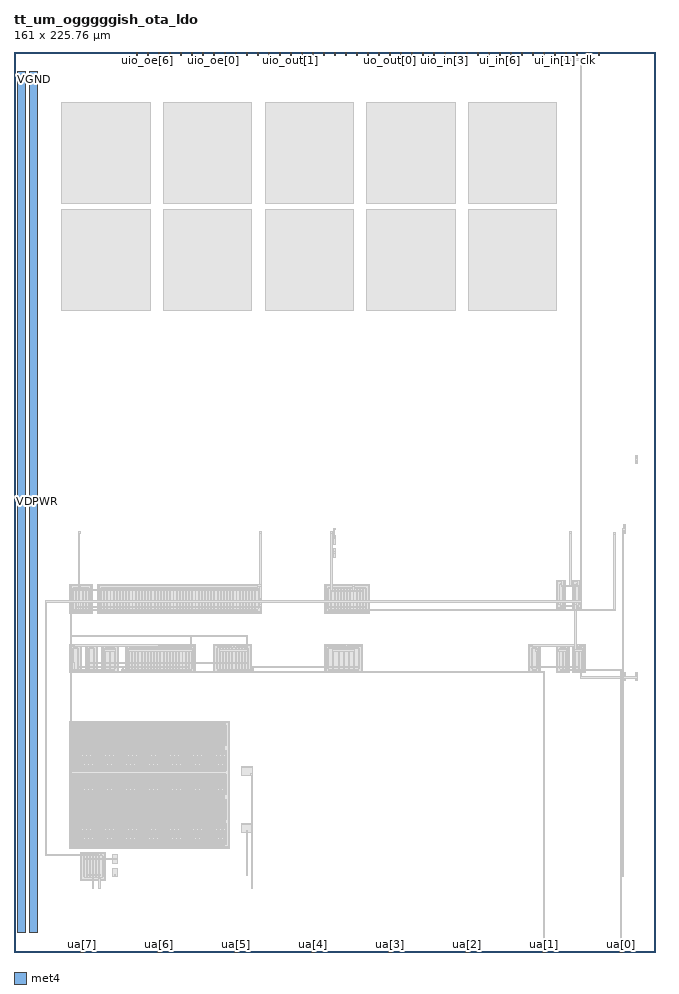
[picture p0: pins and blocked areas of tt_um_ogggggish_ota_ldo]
MACRO tt_um_ogggggish_ota_ldo
  CLASS BLOCK ;
  FOREIGN tt_um_ogggggish_ota_ldo ;
  ORIGIN 0.000 0.000 ;
  SIZE 161.000 BY 225.760 ;
  PIN clk
    DIRECTION INPUT ;
    USE SIGNAL ;
    PORT
      LAYER met4 ;
        RECT 143.830 224.760 144.130 225.760 ;
    END
  END clk
  PIN ena
    DIRECTION INPUT ;
    USE SIGNAL ;
    PORT
      LAYER met4 ;
        RECT 146.590 224.760 146.890 225.760 ;
    END
  END ena
  PIN rst_n
    DIRECTION INPUT ;
    USE SIGNAL ;
    PORT
      LAYER met4 ;
        RECT 141.070 224.760 141.370 225.760 ;
    END
  END rst_n
  PIN ua[0]
    DIRECTION INOUT ;
    USE SIGNAL ;
    ANTENNAGATEAREA 5.000000 ;
    PORT
      LAYER met4 ;
        RECT 151.810 0.000 152.710 1.000 ;
    END
  END ua[0]
  PIN ua[1]
    DIRECTION INOUT ;
    USE SIGNAL ;
    ANTENNAGATEAREA 55.000000 ;
    ANTENNADIFFAREA 1.450000 ;
    PORT
      LAYER met4 ;
        RECT 132.490 0.000 133.390 1.000 ;
    END
  END ua[1]
  PIN ua[2]
    DIRECTION INOUT ;
    USE SIGNAL ;
    ANTENNADIFFAREA 337.250000 ;
    PORT
      LAYER met4 ;
        RECT 113.170 0.000 114.070 1.000 ;
    END
  END ua[2]
  PIN ua[3]
    DIRECTION INOUT ;
    USE SIGNAL ;
    PORT
      LAYER met4 ;
        RECT 93.850 0.000 94.750 1.000 ;
    END
  END ua[3]
  PIN ua[4]
    DIRECTION INOUT ;
    USE SIGNAL ;
    PORT
      LAYER met4 ;
        RECT 74.530 0.000 75.430 1.000 ;
    END
  END ua[4]
  PIN ua[5]
    DIRECTION INOUT ;
    USE SIGNAL ;
    PORT
      LAYER met4 ;
        RECT 55.210 0.000 56.110 1.000 ;
    END
  END ua[5]
  PIN ua[6]
    DIRECTION INOUT ;
    USE SIGNAL ;
    PORT
      LAYER met4 ;
        RECT 35.890 0.000 36.790 1.000 ;
    END
  END ua[6]
  PIN ua[7]
    DIRECTION INOUT ;
    USE SIGNAL ;
    PORT
      LAYER met4 ;
        RECT 16.570 0.000 17.470 1.000 ;
    END
  END ua[7]
  PIN ui_in[0]
    DIRECTION INPUT ;
    USE SIGNAL ;
    ANTENNAGATEAREA 15.000000 ;
    PORT
      LAYER met4 ;
        RECT 138.310 224.760 138.610 225.760 ;
    END
  END ui_in[0]
  PIN ui_in[1]
    DIRECTION INPUT ;
    USE SIGNAL ;
    PORT
      LAYER met4 ;
        RECT 135.550 224.760 135.850 225.760 ;
    END
  END ui_in[1]
  PIN ui_in[2]
    DIRECTION INPUT ;
    USE SIGNAL ;
    PORT
      LAYER met4 ;
        RECT 132.790 224.760 133.090 225.760 ;
    END
  END ui_in[2]
  PIN ui_in[3]
    DIRECTION INPUT ;
    USE SIGNAL ;
    PORT
      LAYER met4 ;
        RECT 130.030 224.760 130.330 225.760 ;
    END
  END ui_in[3]
  PIN ui_in[4]
    DIRECTION INPUT ;
    USE SIGNAL ;
    PORT
      LAYER met4 ;
        RECT 127.270 224.760 127.570 225.760 ;
    END
  END ui_in[4]
  PIN ui_in[5]
    DIRECTION INPUT ;
    USE SIGNAL ;
    PORT
      LAYER met4 ;
        RECT 124.510 224.760 124.810 225.760 ;
    END
  END ui_in[5]
  PIN ui_in[6]
    DIRECTION INPUT ;
    USE SIGNAL ;
    PORT
      LAYER met4 ;
        RECT 121.750 224.760 122.050 225.760 ;
    END
  END ui_in[6]
  PIN ui_in[7]
    DIRECTION INPUT ;
    USE SIGNAL ;
    PORT
      LAYER met4 ;
        RECT 118.990 224.760 119.290 225.760 ;
    END
  END ui_in[7]
  PIN uio_in[0]
    DIRECTION INPUT ;
    USE SIGNAL ;
    PORT
      LAYER met4 ;
        RECT 116.230 224.760 116.530 225.760 ;
    END
  END uio_in[0]
  PIN uio_in[1]
    DIRECTION INPUT ;
    USE SIGNAL ;
    PORT
      LAYER met4 ;
        RECT 113.470 224.760 113.770 225.760 ;
    END
  END uio_in[1]
  PIN uio_in[2]
    DIRECTION INPUT ;
    USE SIGNAL ;
    PORT
      LAYER met4 ;
        RECT 110.710 224.760 111.010 225.760 ;
    END
  END uio_in[2]
  PIN uio_in[3]
    DIRECTION INPUT ;
    USE SIGNAL ;
    PORT
      LAYER met4 ;
        RECT 107.950 224.760 108.250 225.760 ;
    END
  END uio_in[3]
  PIN uio_in[4]
    DIRECTION INPUT ;
    USE SIGNAL ;
    PORT
      LAYER met4 ;
        RECT 105.190 224.760 105.490 225.760 ;
    END
  END uio_in[4]
  PIN uio_in[5]
    DIRECTION INPUT ;
    USE SIGNAL ;
    PORT
      LAYER met4 ;
        RECT 102.430 224.760 102.730 225.760 ;
    END
  END uio_in[5]
  PIN uio_in[6]
    DIRECTION INPUT ;
    USE SIGNAL ;
    PORT
      LAYER met4 ;
        RECT 99.670 224.760 99.970 225.760 ;
    END
  END uio_in[6]
  PIN uio_in[7]
    DIRECTION INPUT ;
    USE SIGNAL ;
    PORT
      LAYER met4 ;
        RECT 96.910 224.760 97.210 225.760 ;
    END
  END uio_in[7]
  PIN uio_oe[0]
    DIRECTION OUTPUT ;
    USE SIGNAL ;
    ANTENNADIFFAREA 65.475197 ;
    PORT
      LAYER met4 ;
        RECT 49.990 224.760 50.290 225.760 ;
    END
  END uio_oe[0]
  PIN uio_oe[1]
    DIRECTION OUTPUT ;
    USE SIGNAL ;
    ANTENNADIFFAREA 65.475197 ;
    PORT
      LAYER met4 ;
        RECT 47.230 224.760 47.530 225.760 ;
    END
  END uio_oe[1]
  PIN uio_oe[2]
    DIRECTION OUTPUT ;
    USE SIGNAL ;
    ANTENNADIFFAREA 65.475197 ;
    PORT
      LAYER met4 ;
        RECT 44.470 224.760 44.770 225.760 ;
    END
  END uio_oe[2]
  PIN uio_oe[3]
    DIRECTION OUTPUT ;
    USE SIGNAL ;
    ANTENNADIFFAREA 65.475197 ;
    PORT
      LAYER met4 ;
        RECT 41.710 224.760 42.010 225.760 ;
    END
  END uio_oe[3]
  PIN uio_oe[4]
    DIRECTION OUTPUT ;
    USE SIGNAL ;
    ANTENNADIFFAREA 65.475197 ;
    PORT
      LAYER met4 ;
        RECT 38.950 224.760 39.250 225.760 ;
    END
  END uio_oe[4]
  PIN uio_oe[5]
    DIRECTION OUTPUT ;
    USE SIGNAL ;
    ANTENNADIFFAREA 65.475197 ;
    PORT
      LAYER met4 ;
        RECT 36.190 224.760 36.490 225.760 ;
    END
  END uio_oe[5]
  PIN uio_oe[6]
    DIRECTION OUTPUT ;
    USE SIGNAL ;
    ANTENNADIFFAREA 65.475197 ;
    PORT
      LAYER met4 ;
        RECT 33.430 224.760 33.730 225.760 ;
    END
  END uio_oe[6]
  PIN uio_oe[7]
    DIRECTION OUTPUT ;
    USE SIGNAL ;
    ANTENNADIFFAREA 65.475197 ;
    PORT
      LAYER met4 ;
        RECT 30.670 224.760 30.970 225.760 ;
    END
  END uio_oe[7]
  PIN uio_out[0]
    DIRECTION OUTPUT ;
    USE SIGNAL ;
    ANTENNADIFFAREA 65.475197 ;
    PORT
      LAYER met4 ;
        RECT 72.070 224.760 72.370 225.760 ;
    END
  END uio_out[0]
  PIN uio_out[1]
    DIRECTION OUTPUT ;
    USE SIGNAL ;
    ANTENNADIFFAREA 65.475197 ;
    PORT
      LAYER met4 ;
        RECT 69.310 224.760 69.610 225.760 ;
    END
  END uio_out[1]
  PIN uio_out[2]
    DIRECTION OUTPUT ;
    USE SIGNAL ;
    ANTENNADIFFAREA 65.475197 ;
    PORT
      LAYER met4 ;
        RECT 66.550 224.760 66.850 225.760 ;
    END
  END uio_out[2]
  PIN uio_out[3]
    DIRECTION OUTPUT ;
    USE SIGNAL ;
    ANTENNADIFFAREA 65.475197 ;
    PORT
      LAYER met4 ;
        RECT 63.790 224.760 64.090 225.760 ;
    END
  END uio_out[3]
  PIN uio_out[4]
    DIRECTION OUTPUT ;
    USE SIGNAL ;
    ANTENNADIFFAREA 65.475197 ;
    PORT
      LAYER met4 ;
        RECT 61.030 224.760 61.330 225.760 ;
    END
  END uio_out[4]
  PIN uio_out[5]
    DIRECTION OUTPUT ;
    USE SIGNAL ;
    ANTENNADIFFAREA 65.475197 ;
    PORT
      LAYER met4 ;
        RECT 58.270 224.760 58.570 225.760 ;
    END
  END uio_out[5]
  PIN uio_out[6]
    DIRECTION OUTPUT ;
    USE SIGNAL ;
    ANTENNADIFFAREA 65.475197 ;
    PORT
      LAYER met4 ;
        RECT 55.510 224.760 55.810 225.760 ;
    END
  END uio_out[6]
  PIN uio_out[7]
    DIRECTION OUTPUT ;
    USE SIGNAL ;
    ANTENNADIFFAREA 65.475197 ;
    PORT
      LAYER met4 ;
        RECT 52.750 224.760 53.050 225.760 ;
    END
  END uio_out[7]
  PIN uo_out[0]
    DIRECTION OUTPUT ;
    USE SIGNAL ;
    ANTENNADIFFAREA 65.475197 ;
    PORT
      LAYER met4 ;
        RECT 94.150 224.760 94.450 225.760 ;
    END
  END uo_out[0]
  PIN uo_out[1]
    DIRECTION OUTPUT ;
    USE SIGNAL ;
    ANTENNADIFFAREA 65.475197 ;
    PORT
      LAYER met4 ;
        RECT 91.390 224.760 91.690 225.760 ;
    END
  END uo_out[1]
  PIN uo_out[2]
    DIRECTION OUTPUT ;
    USE SIGNAL ;
    ANTENNADIFFAREA 65.475197 ;
    PORT
      LAYER met4 ;
        RECT 88.630 224.760 88.930 225.760 ;
    END
  END uo_out[2]
  PIN uo_out[3]
    DIRECTION OUTPUT ;
    USE SIGNAL ;
    ANTENNADIFFAREA 65.475197 ;
    PORT
      LAYER met4 ;
        RECT 85.870 224.760 86.170 225.760 ;
    END
  END uo_out[3]
  PIN uo_out[4]
    DIRECTION OUTPUT ;
    USE SIGNAL ;
    ANTENNADIFFAREA 65.475197 ;
    PORT
      LAYER met4 ;
        RECT 83.110 224.760 83.410 225.760 ;
    END
  END uo_out[4]
  PIN uo_out[5]
    DIRECTION OUTPUT ;
    USE SIGNAL ;
    ANTENNADIFFAREA 65.475197 ;
    PORT
      LAYER met4 ;
        RECT 80.350 224.760 80.650 225.760 ;
    END
  END uo_out[5]
  PIN uo_out[6]
    DIRECTION OUTPUT ;
    USE SIGNAL ;
    ANTENNADIFFAREA 65.475197 ;
    PORT
      LAYER met4 ;
        RECT 77.590 224.760 77.890 225.760 ;
    END
  END uo_out[6]
  PIN uo_out[7]
    DIRECTION OUTPUT ;
    USE SIGNAL ;
    ANTENNADIFFAREA 65.475197 ;
    PORT
      LAYER met4 ;
        RECT 74.830 224.760 75.130 225.760 ;
    END
  END uo_out[7]
  PIN VDPWR
    DIRECTION INOUT ;
    USE POWER ;
    PORT
      LAYER met4 ;
        RECT 1.000 5.005 3.000 220.765 ;
    END
  END VDPWR
  PIN VGND
    DIRECTION INOUT ;
    USE GROUND ;
    PORT
      LAYER met4 ;
        RECT 4.000 5.000 6.000 220.760 ;
    END
  END VGND
  OBS
      LAYER nwell ;
        RECT 14.000 85.000 19.620 92.190 ;
        RECT 21.000 85.000 62.170 92.190 ;
        RECT 78.000 85.000 89.150 92.190 ;
        RECT 136.000 86.000 138.460 93.190 ;
        RECT 140.000 86.000 142.460 93.190 ;
      LAYER pwell ;
        RECT 14.000 70.000 16.960 77.100 ;
        RECT 18.000 70.000 20.960 77.100 ;
        RECT 22.000 70.000 26.250 77.100 ;
        RECT 28.000 70.000 45.470 77.100 ;
      LAYER nwell ;
        RECT 50.000 70.000 59.570 77.190 ;
      LAYER pwell ;
        RECT 78.000 70.000 87.410 77.100 ;
        RECT 129.000 70.000 131.960 77.100 ;
        RECT 136.000 70.000 139.250 77.100 ;
        RECT 140.000 70.000 143.250 77.100 ;
      LAYER nwell ;
        RECT 14.000 26.000 54.070 57.910 ;
      LAYER pwell ;
        RECT 16.650 17.910 23.060 25.010 ;
      LAYER li1 ;
        RECT 156.000 122.495 156.350 124.655 ;
        RECT 153.000 105.000 153.350 107.160 ;
        RECT 80.000 102.200 80.690 104.360 ;
        RECT 80.000 99.000 80.690 101.160 ;
        RECT 137.485 93.010 137.715 93.040 ;
        RECT 141.485 93.010 141.715 93.040 ;
        RECT 136.180 92.840 138.280 93.010 ;
        RECT 16.285 92.010 16.515 92.040 ;
        RECT 61.185 92.010 61.415 92.040 ;
        RECT 85.035 92.010 85.265 92.040 ;
        RECT 14.180 91.840 19.440 92.010 ;
        RECT 14.180 85.350 14.350 91.840 ;
        RECT 16.285 91.810 16.515 91.840 ;
        RECT 14.980 91.330 15.480 91.500 ;
        RECT 15.770 91.330 16.270 91.500 ;
        RECT 16.560 91.330 17.060 91.500 ;
        RECT 17.350 91.330 17.850 91.500 ;
        RECT 18.140 91.330 18.640 91.500 ;
        RECT 14.750 86.075 14.920 91.115 ;
        RECT 15.540 86.075 15.710 91.115 ;
        RECT 16.330 86.075 16.500 91.115 ;
        RECT 17.120 86.075 17.290 91.115 ;
        RECT 17.910 86.075 18.080 91.115 ;
        RECT 18.700 86.075 18.870 91.115 ;
        RECT 14.980 85.690 15.480 85.860 ;
        RECT 15.770 85.690 16.270 85.860 ;
        RECT 16.560 85.690 17.060 85.860 ;
        RECT 17.350 85.690 17.850 85.860 ;
        RECT 18.140 85.690 18.640 85.860 ;
        RECT 19.270 85.350 19.440 91.840 ;
        RECT 14.180 85.180 19.440 85.350 ;
        RECT 21.180 91.840 61.990 92.010 ;
        RECT 21.180 85.350 21.350 91.840 ;
        RECT 61.185 91.810 61.415 91.840 ;
        RECT 21.980 91.330 22.480 91.500 ;
        RECT 22.770 91.330 23.270 91.500 ;
        RECT 23.560 91.330 24.060 91.500 ;
        RECT 24.350 91.330 24.850 91.500 ;
        RECT 25.140 91.330 25.640 91.500 ;
        RECT 25.930 91.330 26.430 91.500 ;
        RECT 26.720 91.330 27.220 91.500 ;
        RECT 27.510 91.330 28.010 91.500 ;
        RECT 28.300 91.330 28.800 91.500 ;
        RECT 29.090 91.330 29.590 91.500 ;
        RECT 29.880 91.330 30.380 91.500 ;
        RECT 30.670 91.330 31.170 91.500 ;
        RECT 31.460 91.330 31.960 91.500 ;
        RECT 32.250 91.330 32.750 91.500 ;
        RECT 33.040 91.330 33.540 91.500 ;
        RECT 33.830 91.330 34.330 91.500 ;
        RECT 34.620 91.330 35.120 91.500 ;
        RECT 35.410 91.330 35.910 91.500 ;
        RECT 36.200 91.330 36.700 91.500 ;
        RECT 36.990 91.330 37.490 91.500 ;
        RECT 37.780 91.330 38.280 91.500 ;
        RECT 38.570 91.330 39.070 91.500 ;
        RECT 39.360 91.330 39.860 91.500 ;
        RECT 40.150 91.330 40.650 91.500 ;
        RECT 40.940 91.330 41.440 91.500 ;
        RECT 41.730 91.330 42.230 91.500 ;
        RECT 42.520 91.330 43.020 91.500 ;
        RECT 43.310 91.330 43.810 91.500 ;
        RECT 44.100 91.330 44.600 91.500 ;
        RECT 44.890 91.330 45.390 91.500 ;
        RECT 45.680 91.330 46.180 91.500 ;
        RECT 46.470 91.330 46.970 91.500 ;
        RECT 47.260 91.330 47.760 91.500 ;
        RECT 48.050 91.330 48.550 91.500 ;
        RECT 48.840 91.330 49.340 91.500 ;
        RECT 49.630 91.330 50.130 91.500 ;
        RECT 50.420 91.330 50.920 91.500 ;
        RECT 51.210 91.330 51.710 91.500 ;
        RECT 52.000 91.330 52.500 91.500 ;
        RECT 52.790 91.330 53.290 91.500 ;
        RECT 53.580 91.330 54.080 91.500 ;
        RECT 54.370 91.330 54.870 91.500 ;
        RECT 55.160 91.330 55.660 91.500 ;
        RECT 55.950 91.330 56.450 91.500 ;
        RECT 56.740 91.330 57.240 91.500 ;
        RECT 57.530 91.330 58.030 91.500 ;
        RECT 58.320 91.330 58.820 91.500 ;
        RECT 59.110 91.330 59.610 91.500 ;
        RECT 59.900 91.330 60.400 91.500 ;
        RECT 60.690 91.330 61.190 91.500 ;
        RECT 21.750 86.075 21.920 91.115 ;
        RECT 22.540 86.075 22.710 91.115 ;
        RECT 23.330 86.075 23.500 91.115 ;
        RECT 24.120 86.075 24.290 91.115 ;
        RECT 24.910 86.075 25.080 91.115 ;
        RECT 25.700 86.075 25.870 91.115 ;
        RECT 26.490 86.075 26.660 91.115 ;
        RECT 27.280 86.075 27.450 91.115 ;
        RECT 28.070 86.075 28.240 91.115 ;
        RECT 28.860 86.075 29.030 91.115 ;
        RECT 29.650 86.075 29.820 91.115 ;
        RECT 30.440 86.075 30.610 91.115 ;
        RECT 31.230 86.075 31.400 91.115 ;
        RECT 32.020 86.075 32.190 91.115 ;
        RECT 32.810 86.075 32.980 91.115 ;
        RECT 33.600 86.075 33.770 91.115 ;
        RECT 34.390 86.075 34.560 91.115 ;
        RECT 35.180 86.075 35.350 91.115 ;
        RECT 35.970 86.075 36.140 91.115 ;
        RECT 36.760 86.075 36.930 91.115 ;
        RECT 37.550 86.075 37.720 91.115 ;
        RECT 38.340 86.075 38.510 91.115 ;
        RECT 39.130 86.075 39.300 91.115 ;
        RECT 39.920 86.075 40.090 91.115 ;
        RECT 40.710 86.075 40.880 91.115 ;
        RECT 41.500 86.075 41.670 91.115 ;
        RECT 42.290 86.075 42.460 91.115 ;
        RECT 43.080 86.075 43.250 91.115 ;
        RECT 43.870 86.075 44.040 91.115 ;
        RECT 44.660 86.075 44.830 91.115 ;
        RECT 45.450 86.075 45.620 91.115 ;
        RECT 46.240 86.075 46.410 91.115 ;
        RECT 47.030 86.075 47.200 91.115 ;
        RECT 47.820 86.075 47.990 91.115 ;
        RECT 48.610 86.075 48.780 91.115 ;
        RECT 49.400 86.075 49.570 91.115 ;
        RECT 50.190 86.075 50.360 91.115 ;
        RECT 50.980 86.075 51.150 91.115 ;
        RECT 51.770 86.075 51.940 91.115 ;
        RECT 52.560 86.075 52.730 91.115 ;
        RECT 53.350 86.075 53.520 91.115 ;
        RECT 54.140 86.075 54.310 91.115 ;
        RECT 54.930 86.075 55.100 91.115 ;
        RECT 55.720 86.075 55.890 91.115 ;
        RECT 56.510 86.075 56.680 91.115 ;
        RECT 57.300 86.075 57.470 91.115 ;
        RECT 58.090 86.075 58.260 91.115 ;
        RECT 58.880 86.075 59.050 91.115 ;
        RECT 59.670 86.075 59.840 91.115 ;
        RECT 60.460 86.075 60.630 91.115 ;
        RECT 61.250 86.075 61.420 91.115 ;
        RECT 21.980 85.690 22.480 85.860 ;
        RECT 22.770 85.690 23.270 85.860 ;
        RECT 23.560 85.690 24.060 85.860 ;
        RECT 24.350 85.690 24.850 85.860 ;
        RECT 25.140 85.690 25.640 85.860 ;
        RECT 25.930 85.690 26.430 85.860 ;
        RECT 26.720 85.690 27.220 85.860 ;
        RECT 27.510 85.690 28.010 85.860 ;
        RECT 28.300 85.690 28.800 85.860 ;
        RECT 29.090 85.690 29.590 85.860 ;
        RECT 29.880 85.690 30.380 85.860 ;
        RECT 30.670 85.690 31.170 85.860 ;
        RECT 31.460 85.690 31.960 85.860 ;
        RECT 32.250 85.690 32.750 85.860 ;
        RECT 33.040 85.690 33.540 85.860 ;
        RECT 33.830 85.690 34.330 85.860 ;
        RECT 34.620 85.690 35.120 85.860 ;
        RECT 35.410 85.690 35.910 85.860 ;
        RECT 36.200 85.690 36.700 85.860 ;
        RECT 36.990 85.690 37.490 85.860 ;
        RECT 37.780 85.690 38.280 85.860 ;
        RECT 38.570 85.690 39.070 85.860 ;
        RECT 39.360 85.690 39.860 85.860 ;
        RECT 40.150 85.690 40.650 85.860 ;
        RECT 40.940 85.690 41.440 85.860 ;
        RECT 41.730 85.690 42.230 85.860 ;
        RECT 42.520 85.690 43.020 85.860 ;
        RECT 43.310 85.690 43.810 85.860 ;
        RECT 44.100 85.690 44.600 85.860 ;
        RECT 44.890 85.690 45.390 85.860 ;
        RECT 45.680 85.690 46.180 85.860 ;
        RECT 46.470 85.690 46.970 85.860 ;
        RECT 47.260 85.690 47.760 85.860 ;
        RECT 48.050 85.690 48.550 85.860 ;
        RECT 48.840 85.690 49.340 85.860 ;
        RECT 49.630 85.690 50.130 85.860 ;
        RECT 50.420 85.690 50.920 85.860 ;
        RECT 51.210 85.690 51.710 85.860 ;
        RECT 52.000 85.690 52.500 85.860 ;
        RECT 52.790 85.690 53.290 85.860 ;
        RECT 53.580 85.690 54.080 85.860 ;
        RECT 54.370 85.690 54.870 85.860 ;
        RECT 55.160 85.690 55.660 85.860 ;
        RECT 55.950 85.690 56.450 85.860 ;
        RECT 56.740 85.690 57.240 85.860 ;
        RECT 57.530 85.690 58.030 85.860 ;
        RECT 58.320 85.690 58.820 85.860 ;
        RECT 59.110 85.690 59.610 85.860 ;
        RECT 59.900 85.690 60.400 85.860 ;
        RECT 60.690 85.690 61.190 85.860 ;
        RECT 61.820 85.350 61.990 91.840 ;
        RECT 21.180 85.180 61.990 85.350 ;
        RECT 78.180 91.840 88.970 92.010 ;
        RECT 78.180 85.350 78.350 91.840 ;
        RECT 85.035 91.810 85.265 91.840 ;
        RECT 78.980 91.330 79.480 91.500 ;
        RECT 79.770 91.330 80.270 91.500 ;
        RECT 80.560 91.330 81.060 91.500 ;
        RECT 81.350 91.330 81.850 91.500 ;
        RECT 82.140 91.330 82.640 91.500 ;
        RECT 82.930 91.330 83.430 91.500 ;
        RECT 83.720 91.330 84.220 91.500 ;
        RECT 84.510 91.330 85.010 91.500 ;
        RECT 85.300 91.330 85.800 91.500 ;
        RECT 86.090 91.330 86.590 91.500 ;
        RECT 86.880 91.330 87.380 91.500 ;
        RECT 87.670 91.330 88.170 91.500 ;
        RECT 78.750 86.075 78.920 91.115 ;
        RECT 79.540 86.075 79.710 91.115 ;
        RECT 80.330 86.075 80.500 91.115 ;
        RECT 81.120 86.075 81.290 91.115 ;
        RECT 81.910 86.075 82.080 91.115 ;
        RECT 82.700 86.075 82.870 91.115 ;
        RECT 83.490 86.075 83.660 91.115 ;
        RECT 84.280 86.075 84.450 91.115 ;
        RECT 85.070 86.075 85.240 91.115 ;
        RECT 85.860 86.075 86.030 91.115 ;
        RECT 86.650 86.075 86.820 91.115 ;
        RECT 87.440 86.075 87.610 91.115 ;
        RECT 88.230 86.075 88.400 91.115 ;
        RECT 78.980 85.690 79.480 85.860 ;
        RECT 79.770 85.690 80.270 85.860 ;
        RECT 80.560 85.690 81.060 85.860 ;
        RECT 81.350 85.690 81.850 85.860 ;
        RECT 82.140 85.690 82.640 85.860 ;
        RECT 82.930 85.690 83.430 85.860 ;
        RECT 83.720 85.690 84.220 85.860 ;
        RECT 84.510 85.690 85.010 85.860 ;
        RECT 85.300 85.690 85.800 85.860 ;
        RECT 86.090 85.690 86.590 85.860 ;
        RECT 86.880 85.690 87.380 85.860 ;
        RECT 87.670 85.690 88.170 85.860 ;
        RECT 88.800 85.350 88.970 91.840 ;
        RECT 136.180 86.350 136.350 92.840 ;
        RECT 137.485 92.810 137.715 92.840 ;
        RECT 136.980 92.330 137.480 92.500 ;
        RECT 136.750 87.075 136.920 92.115 ;
        RECT 137.540 87.075 137.710 92.115 ;
        RECT 136.980 86.690 137.480 86.860 ;
        RECT 138.110 86.350 138.280 92.840 ;
        RECT 136.180 86.180 138.280 86.350 ;
        RECT 140.180 92.840 142.280 93.010 ;
        RECT 140.180 86.350 140.350 92.840 ;
        RECT 141.485 92.810 141.715 92.840 ;
        RECT 140.980 92.330 141.480 92.500 ;
        RECT 140.750 87.075 140.920 92.115 ;
        RECT 141.540 87.075 141.710 92.115 ;
        RECT 140.980 86.690 141.480 86.860 ;
        RECT 142.110 86.350 142.280 92.840 ;
        RECT 140.180 86.180 142.280 86.350 ;
        RECT 78.180 85.180 88.970 85.350 ;
        RECT 58.385 77.010 58.615 77.040 ;
        RECT 15.385 76.920 15.615 76.950 ;
        RECT 18.885 76.920 19.115 76.950 ;
        RECT 23.985 76.920 24.215 76.950 ;
        RECT 35.885 76.920 36.115 76.950 ;
        RECT 14.180 76.750 16.780 76.920 ;
        RECT 14.180 70.350 14.350 76.750 ;
        RECT 15.385 76.720 15.615 76.750 ;
        RECT 14.980 76.240 15.980 76.410 ;
        RECT 14.750 71.030 14.920 76.070 ;
        RECT 16.040 71.030 16.210 76.070 ;
        RECT 14.980 70.690 15.980 70.860 ;
        RECT 16.610 70.350 16.780 76.750 ;
        RECT 14.180 70.180 16.780 70.350 ;
        RECT 18.180 76.750 20.780 76.920 ;
        RECT 18.180 70.350 18.350 76.750 ;
        RECT 18.885 76.720 19.115 76.750 ;
        RECT 18.980 76.240 19.980 76.410 ;
        RECT 18.750 71.030 18.920 76.070 ;
        RECT 20.040 71.030 20.210 76.070 ;
        RECT 18.980 70.690 19.980 70.860 ;
        RECT 20.610 70.350 20.780 76.750 ;
        RECT 18.180 70.180 20.780 70.350 ;
        RECT 22.180 76.750 26.070 76.920 ;
        RECT 22.180 70.350 22.350 76.750 ;
        RECT 23.985 76.720 24.215 76.750 ;
        RECT 22.980 76.240 23.980 76.410 ;
        RECT 24.270 76.240 25.270 76.410 ;
        RECT 22.750 71.030 22.920 76.070 ;
        RECT 24.040 71.030 24.210 76.070 ;
        RECT 25.330 71.030 25.500 76.070 ;
        RECT 22.980 70.690 23.980 70.860 ;
        RECT 24.270 70.690 25.270 70.860 ;
        RECT 25.900 70.350 26.070 76.750 ;
        RECT 22.180 70.180 26.070 70.350 ;
        RECT 28.180 76.750 45.290 76.920 ;
        RECT 28.180 70.350 28.350 76.750 ;
        RECT 35.885 76.720 36.115 76.750 ;
        RECT 28.980 76.240 29.480 76.410 ;
        RECT 29.770 76.240 30.270 76.410 ;
        RECT 30.560 76.240 31.060 76.410 ;
        RECT 31.350 76.240 31.850 76.410 ;
        RECT 32.140 76.240 32.640 76.410 ;
        RECT 32.930 76.240 33.430 76.410 ;
        RECT 33.720 76.240 34.220 76.410 ;
        RECT 34.510 76.240 35.010 76.410 ;
        RECT 35.300 76.240 35.800 76.410 ;
        RECT 36.090 76.240 36.590 76.410 ;
        RECT 36.880 76.240 37.380 76.410 ;
        RECT 37.670 76.240 38.170 76.410 ;
        RECT 38.460 76.240 38.960 76.410 ;
        RECT 39.250 76.240 39.750 76.410 ;
        RECT 40.040 76.240 40.540 76.410 ;
        RECT 40.830 76.240 41.330 76.410 ;
        RECT 41.620 76.240 42.120 76.410 ;
        RECT 42.410 76.240 42.910 76.410 ;
        RECT 43.200 76.240 43.700 76.410 ;
        RECT 43.990 76.240 44.490 76.410 ;
        RECT 28.750 71.030 28.920 76.070 ;
        RECT 29.540 71.030 29.710 76.070 ;
        RECT 30.330 71.030 30.500 76.070 ;
        RECT 31.120 71.030 31.290 76.070 ;
        RECT 31.910 71.030 32.080 76.070 ;
        RECT 32.700 71.030 32.870 76.070 ;
        RECT 33.490 71.030 33.660 76.070 ;
        RECT 34.280 71.030 34.450 76.070 ;
        RECT 35.070 71.030 35.240 76.070 ;
        RECT 35.860 71.030 36.030 76.070 ;
        RECT 36.650 71.030 36.820 76.070 ;
        RECT 37.440 71.030 37.610 76.070 ;
        RECT 38.230 71.030 38.400 76.070 ;
        RECT 39.020 71.030 39.190 76.070 ;
        RECT 39.810 71.030 39.980 76.070 ;
        RECT 40.600 71.030 40.770 76.070 ;
        RECT 41.390 71.030 41.560 76.070 ;
        RECT 42.180 71.030 42.350 76.070 ;
        RECT 42.970 71.030 43.140 76.070 ;
        RECT 43.760 71.030 43.930 76.070 ;
        RECT 44.550 71.030 44.720 76.070 ;
        RECT 28.980 70.690 29.480 70.860 ;
        RECT 29.770 70.690 30.270 70.860 ;
        RECT 30.560 70.690 31.060 70.860 ;
        RECT 31.350 70.690 31.850 70.860 ;
        RECT 32.140 70.690 32.640 70.860 ;
        RECT 32.930 70.690 33.430 70.860 ;
        RECT 33.720 70.690 34.220 70.860 ;
        RECT 34.510 70.690 35.010 70.860 ;
        RECT 35.300 70.690 35.800 70.860 ;
        RECT 36.090 70.690 36.590 70.860 ;
        RECT 36.880 70.690 37.380 70.860 ;
        RECT 37.670 70.690 38.170 70.860 ;
        RECT 38.460 70.690 38.960 70.860 ;
        RECT 39.250 70.690 39.750 70.860 ;
        RECT 40.040 70.690 40.540 70.860 ;
        RECT 40.830 70.690 41.330 70.860 ;
        RECT 41.620 70.690 42.120 70.860 ;
        RECT 42.410 70.690 42.910 70.860 ;
        RECT 43.200 70.690 43.700 70.860 ;
        RECT 43.990 70.690 44.490 70.860 ;
        RECT 45.120 70.350 45.290 76.750 ;
        RECT 28.180 70.180 45.290 70.350 ;
        RECT 50.180 76.840 59.390 77.010 ;
        RECT 83.235 76.920 83.465 76.950 ;
        RECT 130.185 76.920 130.415 76.950 ;
        RECT 137.485 76.920 137.715 76.950 ;
        RECT 141.485 76.920 141.715 76.950 ;
        RECT 50.180 70.350 50.350 76.840 ;
        RECT 58.385 76.810 58.615 76.840 ;
        RECT 50.980 76.330 51.480 76.500 ;
        RECT 51.770 76.330 52.270 76.500 ;
        RECT 52.560 76.330 53.060 76.500 ;
        RECT 53.350 76.330 53.850 76.500 ;
        RECT 54.140 76.330 54.640 76.500 ;
        RECT 54.930 76.330 55.430 76.500 ;
        RECT 55.720 76.330 56.220 76.500 ;
        RECT 56.510 76.330 57.010 76.500 ;
        RECT 57.300 76.330 57.800 76.500 ;
        RECT 58.090 76.330 58.590 76.500 ;
        RECT 50.750 71.075 50.920 76.115 ;
        RECT 51.540 71.075 51.710 76.115 ;
        RECT 52.330 71.075 52.500 76.115 ;
        RECT 53.120 71.075 53.290 76.115 ;
        RECT 53.910 71.075 54.080 76.115 ;
        RECT 54.700 71.075 54.870 76.115 ;
        RECT 55.490 71.075 55.660 76.115 ;
        RECT 56.280 71.075 56.450 76.115 ;
        RECT 57.070 71.075 57.240 76.115 ;
        RECT 57.860 71.075 58.030 76.115 ;
        RECT 58.650 71.075 58.820 76.115 ;
        RECT 50.980 70.690 51.480 70.860 ;
        RECT 51.770 70.690 52.270 70.860 ;
        RECT 52.560 70.690 53.060 70.860 ;
        RECT 53.350 70.690 53.850 70.860 ;
        RECT 54.140 70.690 54.640 70.860 ;
        RECT 54.930 70.690 55.430 70.860 ;
        RECT 55.720 70.690 56.220 70.860 ;
        RECT 56.510 70.690 57.010 70.860 ;
        RECT 57.300 70.690 57.800 70.860 ;
        RECT 58.090 70.690 58.590 70.860 ;
        RECT 59.220 70.350 59.390 76.840 ;
        RECT 50.180 70.180 59.390 70.350 ;
        RECT 78.180 76.750 87.230 76.920 ;
        RECT 78.180 70.350 78.350 76.750 ;
        RECT 83.235 76.720 83.465 76.750 ;
        RECT 78.980 76.240 79.980 76.410 ;
        RECT 80.270 76.240 81.270 76.410 ;
        RECT 81.560 76.240 82.560 76.410 ;
        RECT 82.850 76.240 83.850 76.410 ;
        RECT 84.140 76.240 85.140 76.410 ;
        RECT 85.430 76.240 86.430 76.410 ;
        RECT 78.750 71.030 78.920 76.070 ;
        RECT 80.040 71.030 80.210 76.070 ;
        RECT 81.330 71.030 81.500 76.070 ;
        RECT 82.620 71.030 82.790 76.070 ;
        RECT 83.910 71.030 84.080 76.070 ;
        RECT 85.200 71.030 85.370 76.070 ;
        RECT 86.490 71.030 86.660 76.070 ;
        RECT 78.980 70.690 79.980 70.860 ;
        RECT 80.270 70.690 81.270 70.860 ;
        RECT 81.560 70.690 82.560 70.860 ;
        RECT 82.850 70.690 83.850 70.860 ;
        RECT 84.140 70.690 85.140 70.860 ;
        RECT 85.430 70.690 86.430 70.860 ;
        RECT 87.060 70.350 87.230 76.750 ;
        RECT 78.180 70.180 87.230 70.350 ;
        RECT 129.180 76.750 131.780 76.920 ;
        RECT 129.180 70.350 129.350 76.750 ;
        RECT 130.185 76.720 130.415 76.750 ;
        RECT 129.980 76.240 130.980 76.410 ;
        RECT 129.750 71.030 129.920 76.070 ;
        RECT 131.040 71.030 131.210 76.070 ;
        RECT 129.980 70.690 130.980 70.860 ;
        RECT 131.610 70.350 131.780 76.750 ;
        RECT 129.180 70.180 131.780 70.350 ;
        RECT 136.180 76.750 139.070 76.920 ;
        RECT 136.180 70.350 136.350 76.750 ;
        RECT 137.485 76.720 137.715 76.750 ;
        RECT 136.980 76.240 137.480 76.410 ;
        RECT 137.770 76.240 138.270 76.410 ;
        RECT 136.750 71.030 136.920 76.070 ;
        RECT 137.540 71.030 137.710 76.070 ;
        RECT 138.330 71.030 138.500 76.070 ;
        RECT 136.980 70.690 137.480 70.860 ;
        RECT 137.770 70.690 138.270 70.860 ;
        RECT 138.900 70.350 139.070 76.750 ;
        RECT 136.180 70.180 139.070 70.350 ;
        RECT 140.180 76.750 143.070 76.920 ;
        RECT 140.180 70.350 140.350 76.750 ;
        RECT 141.485 76.720 141.715 76.750 ;
        RECT 140.980 76.240 141.480 76.410 ;
        RECT 141.770 76.240 142.270 76.410 ;
        RECT 140.750 71.030 140.920 76.070 ;
        RECT 141.540 71.030 141.710 76.070 ;
        RECT 142.330 71.030 142.500 76.070 ;
        RECT 140.980 70.690 141.480 70.860 ;
        RECT 141.770 70.690 142.270 70.860 ;
        RECT 142.900 70.350 143.070 76.750 ;
        RECT 140.180 70.180 143.070 70.350 ;
        RECT 153.000 68.000 153.350 70.160 ;
        RECT 156.000 67.995 156.350 70.155 ;
        RECT 14.180 57.560 53.890 57.730 ;
        RECT 14.180 26.350 14.350 57.560 ;
        RECT 15.390 57.050 15.720 57.220 ;
        RECT 16.350 57.050 16.680 57.220 ;
        RECT 17.310 57.050 17.640 57.220 ;
        RECT 18.270 57.050 18.600 57.220 ;
        RECT 19.230 57.050 19.560 57.220 ;
        RECT 20.190 57.050 20.520 57.220 ;
        RECT 21.150 57.050 21.480 57.220 ;
        RECT 22.110 57.050 22.440 57.220 ;
        RECT 23.070 57.050 23.400 57.220 ;
        RECT 24.030 57.050 24.360 57.220 ;
        RECT 24.990 57.050 25.320 57.220 ;
        RECT 25.950 57.050 26.280 57.220 ;
        RECT 26.910 57.050 27.240 57.220 ;
        RECT 27.870 57.050 28.200 57.220 ;
        RECT 28.830 57.050 29.160 57.220 ;
        RECT 29.790 57.050 30.120 57.220 ;
        RECT 30.750 57.050 31.080 57.220 ;
        RECT 31.710 57.050 32.040 57.220 ;
        RECT 32.670 57.050 33.000 57.220 ;
        RECT 33.630 57.050 33.960 57.220 ;
        RECT 34.590 57.050 34.920 57.220 ;
        RECT 35.550 57.050 35.880 57.220 ;
        RECT 36.510 57.050 36.840 57.220 ;
        RECT 37.470 57.050 37.800 57.220 ;
        RECT 38.430 57.050 38.760 57.220 ;
        RECT 39.390 57.050 39.720 57.220 ;
        RECT 40.350 57.050 40.680 57.220 ;
        RECT 41.310 57.050 41.640 57.220 ;
        RECT 42.270 57.050 42.600 57.220 ;
        RECT 43.230 57.050 43.560 57.220 ;
        RECT 44.190 57.050 44.520 57.220 ;
        RECT 45.150 57.050 45.480 57.220 ;
        RECT 46.110 57.050 46.440 57.220 ;
        RECT 47.070 57.050 47.400 57.220 ;
        RECT 48.030 57.050 48.360 57.220 ;
        RECT 48.990 57.050 49.320 57.220 ;
        RECT 49.950 57.050 50.280 57.220 ;
        RECT 50.910 57.050 51.240 57.220 ;
        RECT 51.870 57.050 52.200 57.220 ;
        RECT 52.830 57.050 53.160 57.220 ;
        RECT 14.750 51.795 14.920 56.835 ;
        RECT 15.230 51.795 15.400 56.835 ;
        RECT 15.710 51.795 15.880 56.835 ;
        RECT 16.190 51.795 16.360 56.835 ;
        RECT 16.670 51.795 16.840 56.835 ;
        RECT 17.150 51.795 17.320 56.835 ;
        RECT 17.630 51.795 17.800 56.835 ;
        RECT 18.110 51.795 18.280 56.835 ;
        RECT 18.590 51.795 18.760 56.835 ;
        RECT 19.070 51.795 19.240 56.835 ;
        RECT 19.550 51.795 19.720 56.835 ;
        RECT 20.030 51.795 20.200 56.835 ;
        RECT 20.510 51.795 20.680 56.835 ;
        RECT 20.990 51.795 21.160 56.835 ;
        RECT 21.470 51.795 21.640 56.835 ;
        RECT 21.950 51.795 22.120 56.835 ;
        RECT 22.430 51.795 22.600 56.835 ;
        RECT 22.910 51.795 23.080 56.835 ;
        RECT 23.390 51.795 23.560 56.835 ;
        RECT 23.870 51.795 24.040 56.835 ;
        RECT 24.350 51.795 24.520 56.835 ;
        RECT 24.830 51.795 25.000 56.835 ;
        RECT 25.310 51.795 25.480 56.835 ;
        RECT 25.790 51.795 25.960 56.835 ;
        RECT 26.270 51.795 26.440 56.835 ;
        RECT 26.750 51.795 26.920 56.835 ;
        RECT 27.230 51.795 27.400 56.835 ;
        RECT 27.710 51.795 27.880 56.835 ;
        RECT 28.190 51.795 28.360 56.835 ;
        RECT 28.670 51.795 28.840 56.835 ;
        RECT 29.150 51.795 29.320 56.835 ;
        RECT 29.630 51.795 29.800 56.835 ;
        RECT 30.110 51.795 30.280 56.835 ;
        RECT 30.590 51.795 30.760 56.835 ;
        RECT 31.070 51.795 31.240 56.835 ;
        RECT 31.550 51.795 31.720 56.835 ;
        RECT 32.030 51.795 32.200 56.835 ;
        RECT 32.510 51.795 32.680 56.835 ;
        RECT 32.990 51.795 33.160 56.835 ;
        RECT 33.470 51.795 33.640 56.835 ;
        RECT 33.950 51.795 34.120 56.835 ;
        RECT 34.430 51.795 34.600 56.835 ;
        RECT 34.910 51.795 35.080 56.835 ;
        RECT 35.390 51.795 35.560 56.835 ;
        RECT 35.870 51.795 36.040 56.835 ;
        RECT 36.350 51.795 36.520 56.835 ;
        RECT 36.830 51.795 37.000 56.835 ;
        RECT 37.310 51.795 37.480 56.835 ;
        RECT 37.790 51.795 37.960 56.835 ;
        RECT 38.270 51.795 38.440 56.835 ;
        RECT 38.750 51.795 38.920 56.835 ;
        RECT 39.230 51.795 39.400 56.835 ;
        RECT 39.710 51.795 39.880 56.835 ;
        RECT 40.190 51.795 40.360 56.835 ;
        RECT 40.670 51.795 40.840 56.835 ;
        RECT 41.150 51.795 41.320 56.835 ;
        RECT 41.630 51.795 41.800 56.835 ;
        RECT 42.110 51.795 42.280 56.835 ;
        RECT 42.590 51.795 42.760 56.835 ;
        RECT 43.070 51.795 43.240 56.835 ;
        RECT 43.550 51.795 43.720 56.835 ;
        RECT 44.030 51.795 44.200 56.835 ;
        RECT 44.510 51.795 44.680 56.835 ;
        RECT 44.990 51.795 45.160 56.835 ;
        RECT 45.470 51.795 45.640 56.835 ;
        RECT 45.950 51.795 46.120 56.835 ;
        RECT 46.430 51.795 46.600 56.835 ;
        RECT 46.910 51.795 47.080 56.835 ;
        RECT 47.390 51.795 47.560 56.835 ;
        RECT 47.870 51.795 48.040 56.835 ;
        RECT 48.350 51.795 48.520 56.835 ;
        RECT 48.830 51.795 49.000 56.835 ;
        RECT 49.310 51.795 49.480 56.835 ;
        RECT 49.790 51.795 49.960 56.835 ;
        RECT 50.270 51.795 50.440 56.835 ;
        RECT 50.750 51.795 50.920 56.835 ;
        RECT 51.230 51.795 51.400 56.835 ;
        RECT 51.710 51.795 51.880 56.835 ;
        RECT 52.190 51.795 52.360 56.835 ;
        RECT 52.670 51.795 52.840 56.835 ;
        RECT 53.150 51.795 53.320 56.835 ;
        RECT 14.910 51.410 15.240 51.580 ;
        RECT 15.870 51.410 16.200 51.580 ;
        RECT 16.830 51.410 17.160 51.580 ;
        RECT 17.790 51.410 18.120 51.580 ;
        RECT 18.750 51.410 19.080 51.580 ;
        RECT 19.710 51.410 20.040 51.580 ;
        RECT 20.670 51.410 21.000 51.580 ;
        RECT 21.630 51.410 21.960 51.580 ;
        RECT 22.590 51.410 22.920 51.580 ;
        RECT 23.550 51.410 23.880 51.580 ;
        RECT 24.510 51.410 24.840 51.580 ;
        RECT 25.470 51.410 25.800 51.580 ;
        RECT 26.430 51.410 26.760 51.580 ;
        RECT 27.390 51.410 27.720 51.580 ;
        RECT 28.350 51.410 28.680 51.580 ;
        RECT 29.310 51.410 29.640 51.580 ;
        RECT 30.270 51.410 30.600 51.580 ;
        RECT 31.230 51.410 31.560 51.580 ;
        RECT 32.190 51.410 32.520 51.580 ;
        RECT 33.150 51.410 33.480 51.580 ;
        RECT 34.110 51.410 34.440 51.580 ;
        RECT 35.070 51.410 35.400 51.580 ;
        RECT 36.030 51.410 36.360 51.580 ;
        RECT 36.990 51.410 37.320 51.580 ;
        RECT 37.950 51.410 38.280 51.580 ;
        RECT 38.910 51.410 39.240 51.580 ;
        RECT 39.870 51.410 40.200 51.580 ;
        RECT 40.830 51.410 41.160 51.580 ;
        RECT 41.790 51.410 42.120 51.580 ;
        RECT 42.750 51.410 43.080 51.580 ;
        RECT 43.710 51.410 44.040 51.580 ;
        RECT 44.670 51.410 45.000 51.580 ;
        RECT 45.630 51.410 45.960 51.580 ;
        RECT 46.590 51.410 46.920 51.580 ;
        RECT 47.550 51.410 47.880 51.580 ;
        RECT 48.510 51.410 48.840 51.580 ;
        RECT 49.470 51.410 49.800 51.580 ;
        RECT 50.430 51.410 50.760 51.580 ;
        RECT 51.390 51.410 51.720 51.580 ;
        RECT 52.350 51.410 52.680 51.580 ;
        RECT 14.910 50.870 15.240 51.040 ;
        RECT 15.870 50.870 16.200 51.040 ;
        RECT 16.830 50.870 17.160 51.040 ;
        RECT 17.790 50.870 18.120 51.040 ;
        RECT 18.750 50.870 19.080 51.040 ;
        RECT 19.710 50.870 20.040 51.040 ;
        RECT 20.670 50.870 21.000 51.040 ;
        RECT 21.630 50.870 21.960 51.040 ;
        RECT 22.590 50.870 22.920 51.040 ;
        RECT 23.550 50.870 23.880 51.040 ;
        RECT 24.510 50.870 24.840 51.040 ;
        RECT 25.470 50.870 25.800 51.040 ;
        RECT 26.430 50.870 26.760 51.040 ;
        RECT 27.390 50.870 27.720 51.040 ;
        RECT 28.350 50.870 28.680 51.040 ;
        RECT 29.310 50.870 29.640 51.040 ;
        RECT 30.270 50.870 30.600 51.040 ;
        RECT 31.230 50.870 31.560 51.040 ;
        RECT 32.190 50.870 32.520 51.040 ;
        RECT 33.150 50.870 33.480 51.040 ;
        RECT 34.110 50.870 34.440 51.040 ;
        RECT 35.070 50.870 35.400 51.040 ;
        RECT 36.030 50.870 36.360 51.040 ;
        RECT 36.990 50.870 37.320 51.040 ;
        RECT 37.950 50.870 38.280 51.040 ;
        RECT 38.910 50.870 39.240 51.040 ;
        RECT 39.870 50.870 40.200 51.040 ;
        RECT 40.830 50.870 41.160 51.040 ;
        RECT 41.790 50.870 42.120 51.040 ;
        RECT 42.750 50.870 43.080 51.040 ;
        RECT 43.710 50.870 44.040 51.040 ;
        RECT 44.670 50.870 45.000 51.040 ;
        RECT 45.630 50.870 45.960 51.040 ;
        RECT 46.590 50.870 46.920 51.040 ;
        RECT 47.550 50.870 47.880 51.040 ;
        RECT 48.510 50.870 48.840 51.040 ;
        RECT 49.470 50.870 49.800 51.040 ;
        RECT 50.430 50.870 50.760 51.040 ;
        RECT 51.390 50.870 51.720 51.040 ;
        RECT 52.350 50.870 52.680 51.040 ;
        RECT 14.750 45.615 14.920 50.655 ;
        RECT 15.230 45.615 15.400 50.655 ;
        RECT 15.710 45.615 15.880 50.655 ;
        RECT 16.190 45.615 16.360 50.655 ;
        RECT 16.670 45.615 16.840 50.655 ;
        RECT 17.150 45.615 17.320 50.655 ;
        RECT 17.630 45.615 17.800 50.655 ;
        RECT 18.110 45.615 18.280 50.655 ;
        RECT 18.590 45.615 18.760 50.655 ;
        RECT 19.070 45.615 19.240 50.655 ;
        RECT 19.550 45.615 19.720 50.655 ;
        RECT 20.030 45.615 20.200 50.655 ;
        RECT 20.510 45.615 20.680 50.655 ;
        RECT 20.990 45.615 21.160 50.655 ;
        RECT 21.470 45.615 21.640 50.655 ;
        RECT 21.950 45.615 22.120 50.655 ;
        RECT 22.430 45.615 22.600 50.655 ;
        RECT 22.910 45.615 23.080 50.655 ;
        RECT 23.390 45.615 23.560 50.655 ;
        RECT 23.870 45.615 24.040 50.655 ;
        RECT 24.350 45.615 24.520 50.655 ;
        RECT 24.830 45.615 25.000 50.655 ;
        RECT 25.310 45.615 25.480 50.655 ;
        RECT 25.790 45.615 25.960 50.655 ;
        RECT 26.270 45.615 26.440 50.655 ;
        RECT 26.750 45.615 26.920 50.655 ;
        RECT 27.230 45.615 27.400 50.655 ;
        RECT 27.710 45.615 27.880 50.655 ;
        RECT 28.190 45.615 28.360 50.655 ;
        RECT 28.670 45.615 28.840 50.655 ;
        RECT 29.150 45.615 29.320 50.655 ;
        RECT 29.630 45.615 29.800 50.655 ;
        RECT 30.110 45.615 30.280 50.655 ;
        RECT 30.590 45.615 30.760 50.655 ;
        RECT 31.070 45.615 31.240 50.655 ;
        RECT 31.550 45.615 31.720 50.655 ;
        RECT 32.030 45.615 32.200 50.655 ;
        RECT 32.510 45.615 32.680 50.655 ;
        RECT 32.990 45.615 33.160 50.655 ;
        RECT 33.470 45.615 33.640 50.655 ;
        RECT 33.950 45.615 34.120 50.655 ;
        RECT 34.430 45.615 34.600 50.655 ;
        RECT 34.910 45.615 35.080 50.655 ;
        RECT 35.390 45.615 35.560 50.655 ;
        RECT 35.870 45.615 36.040 50.655 ;
        RECT 36.350 45.615 36.520 50.655 ;
        RECT 36.830 45.615 37.000 50.655 ;
        RECT 37.310 45.615 37.480 50.655 ;
        RECT 37.790 45.615 37.960 50.655 ;
        RECT 38.270 45.615 38.440 50.655 ;
        RECT 38.750 45.615 38.920 50.655 ;
        RECT 39.230 45.615 39.400 50.655 ;
        RECT 39.710 45.615 39.880 50.655 ;
        RECT 40.190 45.615 40.360 50.655 ;
        RECT 40.670 45.615 40.840 50.655 ;
        RECT 41.150 45.615 41.320 50.655 ;
        RECT 41.630 45.615 41.800 50.655 ;
        RECT 42.110 45.615 42.280 50.655 ;
        RECT 42.590 45.615 42.760 50.655 ;
        RECT 43.070 45.615 43.240 50.655 ;
        RECT 43.550 45.615 43.720 50.655 ;
        RECT 44.030 45.615 44.200 50.655 ;
        RECT 44.510 45.615 44.680 50.655 ;
        RECT 44.990 45.615 45.160 50.655 ;
        RECT 45.470 45.615 45.640 50.655 ;
        RECT 45.950 45.615 46.120 50.655 ;
        RECT 46.430 45.615 46.600 50.655 ;
        RECT 46.910 45.615 47.080 50.655 ;
        RECT 47.390 45.615 47.560 50.655 ;
        RECT 47.870 45.615 48.040 50.655 ;
        RECT 48.350 45.615 48.520 50.655 ;
        RECT 48.830 45.615 49.000 50.655 ;
        RECT 49.310 45.615 49.480 50.655 ;
        RECT 49.790 45.615 49.960 50.655 ;
        RECT 50.270 45.615 50.440 50.655 ;
        RECT 50.750 45.615 50.920 50.655 ;
        RECT 51.230 45.615 51.400 50.655 ;
        RECT 51.710 45.615 51.880 50.655 ;
        RECT 52.190 45.615 52.360 50.655 ;
        RECT 52.670 45.615 52.840 50.655 ;
        RECT 53.150 45.615 53.320 50.655 ;
        RECT 15.390 45.230 15.720 45.400 ;
        RECT 16.350 45.230 16.680 45.400 ;
        RECT 17.310 45.230 17.640 45.400 ;
        RECT 18.270 45.230 18.600 45.400 ;
        RECT 19.230 45.230 19.560 45.400 ;
        RECT 20.190 45.230 20.520 45.400 ;
        RECT 21.150 45.230 21.480 45.400 ;
        RECT 22.110 45.230 22.440 45.400 ;
        RECT 23.070 45.230 23.400 45.400 ;
        RECT 24.030 45.230 24.360 45.400 ;
        RECT 24.990 45.230 25.320 45.400 ;
        RECT 25.950 45.230 26.280 45.400 ;
        RECT 26.910 45.230 27.240 45.400 ;
        RECT 27.870 45.230 28.200 45.400 ;
        RECT 28.830 45.230 29.160 45.400 ;
        RECT 29.790 45.230 30.120 45.400 ;
        RECT 30.750 45.230 31.080 45.400 ;
        RECT 31.710 45.230 32.040 45.400 ;
        RECT 32.670 45.230 33.000 45.400 ;
        RECT 33.630 45.230 33.960 45.400 ;
        RECT 34.590 45.230 34.920 45.400 ;
        RECT 35.550 45.230 35.880 45.400 ;
        RECT 36.510 45.230 36.840 45.400 ;
        RECT 37.470 45.230 37.800 45.400 ;
        RECT 38.430 45.230 38.760 45.400 ;
        RECT 39.390 45.230 39.720 45.400 ;
        RECT 40.350 45.230 40.680 45.400 ;
        RECT 41.310 45.230 41.640 45.400 ;
        RECT 42.270 45.230 42.600 45.400 ;
        RECT 43.230 45.230 43.560 45.400 ;
        RECT 44.190 45.230 44.520 45.400 ;
        RECT 45.150 45.230 45.480 45.400 ;
        RECT 46.110 45.230 46.440 45.400 ;
        RECT 47.070 45.230 47.400 45.400 ;
        RECT 48.030 45.230 48.360 45.400 ;
        RECT 48.990 45.230 49.320 45.400 ;
        RECT 49.950 45.230 50.280 45.400 ;
        RECT 50.910 45.230 51.240 45.400 ;
        RECT 51.870 45.230 52.200 45.400 ;
        RECT 52.830 45.230 53.160 45.400 ;
        RECT 15.390 44.690 15.720 44.860 ;
        RECT 16.350 44.690 16.680 44.860 ;
        RECT 17.310 44.690 17.640 44.860 ;
        RECT 18.270 44.690 18.600 44.860 ;
        RECT 19.230 44.690 19.560 44.860 ;
        RECT 20.190 44.690 20.520 44.860 ;
        RECT 21.150 44.690 21.480 44.860 ;
        RECT 22.110 44.690 22.440 44.860 ;
        RECT 23.070 44.690 23.400 44.860 ;
        RECT 24.030 44.690 24.360 44.860 ;
        RECT 24.990 44.690 25.320 44.860 ;
        RECT 25.950 44.690 26.280 44.860 ;
        RECT 26.910 44.690 27.240 44.860 ;
        RECT 27.870 44.690 28.200 44.860 ;
        RECT 28.830 44.690 29.160 44.860 ;
        RECT 29.790 44.690 30.120 44.860 ;
        RECT 30.750 44.690 31.080 44.860 ;
        RECT 31.710 44.690 32.040 44.860 ;
        RECT 32.670 44.690 33.000 44.860 ;
        RECT 33.630 44.690 33.960 44.860 ;
        RECT 34.590 44.690 34.920 44.860 ;
        RECT 35.550 44.690 35.880 44.860 ;
        RECT 36.510 44.690 36.840 44.860 ;
        RECT 37.470 44.690 37.800 44.860 ;
        RECT 38.430 44.690 38.760 44.860 ;
        RECT 39.390 44.690 39.720 44.860 ;
        RECT 40.350 44.690 40.680 44.860 ;
        RECT 41.310 44.690 41.640 44.860 ;
        RECT 42.270 44.690 42.600 44.860 ;
        RECT 43.230 44.690 43.560 44.860 ;
        RECT 44.190 44.690 44.520 44.860 ;
        RECT 45.150 44.690 45.480 44.860 ;
        RECT 46.110 44.690 46.440 44.860 ;
        RECT 47.070 44.690 47.400 44.860 ;
        RECT 48.030 44.690 48.360 44.860 ;
        RECT 48.990 44.690 49.320 44.860 ;
        RECT 49.950 44.690 50.280 44.860 ;
        RECT 50.910 44.690 51.240 44.860 ;
        RECT 51.870 44.690 52.200 44.860 ;
        RECT 52.830 44.690 53.160 44.860 ;
        RECT 14.750 39.435 14.920 44.475 ;
        RECT 15.230 39.435 15.400 44.475 ;
        RECT 15.710 39.435 15.880 44.475 ;
        RECT 16.190 39.435 16.360 44.475 ;
        RECT 16.670 39.435 16.840 44.475 ;
        RECT 17.150 39.435 17.320 44.475 ;
        RECT 17.630 39.435 17.800 44.475 ;
        RECT 18.110 39.435 18.280 44.475 ;
        RECT 18.590 39.435 18.760 44.475 ;
        RECT 19.070 39.435 19.240 44.475 ;
        RECT 19.550 39.435 19.720 44.475 ;
        RECT 20.030 39.435 20.200 44.475 ;
        RECT 20.510 39.435 20.680 44.475 ;
        RECT 20.990 39.435 21.160 44.475 ;
        RECT 21.470 39.435 21.640 44.475 ;
        RECT 21.950 39.435 22.120 44.475 ;
        RECT 22.430 39.435 22.600 44.475 ;
        RECT 22.910 39.435 23.080 44.475 ;
        RECT 23.390 39.435 23.560 44.475 ;
        RECT 23.870 39.435 24.040 44.475 ;
        RECT 24.350 39.435 24.520 44.475 ;
        RECT 24.830 39.435 25.000 44.475 ;
        RECT 25.310 39.435 25.480 44.475 ;
        RECT 25.790 39.435 25.960 44.475 ;
        RECT 26.270 39.435 26.440 44.475 ;
        RECT 26.750 39.435 26.920 44.475 ;
        RECT 27.230 39.435 27.400 44.475 ;
        RECT 27.710 39.435 27.880 44.475 ;
        RECT 28.190 39.435 28.360 44.475 ;
        RECT 28.670 39.435 28.840 44.475 ;
        RECT 29.150 39.435 29.320 44.475 ;
        RECT 29.630 39.435 29.800 44.475 ;
        RECT 30.110 39.435 30.280 44.475 ;
        RECT 30.590 39.435 30.760 44.475 ;
        RECT 31.070 39.435 31.240 44.475 ;
        RECT 31.550 39.435 31.720 44.475 ;
        RECT 32.030 39.435 32.200 44.475 ;
        RECT 32.510 39.435 32.680 44.475 ;
        RECT 32.990 39.435 33.160 44.475 ;
        RECT 33.470 39.435 33.640 44.475 ;
        RECT 33.950 39.435 34.120 44.475 ;
        RECT 34.430 39.435 34.600 44.475 ;
        RECT 34.910 39.435 35.080 44.475 ;
        RECT 35.390 39.435 35.560 44.475 ;
        RECT 35.870 39.435 36.040 44.475 ;
        RECT 36.350 39.435 36.520 44.475 ;
        RECT 36.830 39.435 37.000 44.475 ;
        RECT 37.310 39.435 37.480 44.475 ;
        RECT 37.790 39.435 37.960 44.475 ;
        RECT 38.270 39.435 38.440 44.475 ;
        RECT 38.750 39.435 38.920 44.475 ;
        RECT 39.230 39.435 39.400 44.475 ;
        RECT 39.710 39.435 39.880 44.475 ;
        RECT 40.190 39.435 40.360 44.475 ;
        RECT 40.670 39.435 40.840 44.475 ;
        RECT 41.150 39.435 41.320 44.475 ;
        RECT 41.630 39.435 41.800 44.475 ;
        RECT 42.110 39.435 42.280 44.475 ;
        RECT 42.590 39.435 42.760 44.475 ;
        RECT 43.070 39.435 43.240 44.475 ;
        RECT 43.550 39.435 43.720 44.475 ;
        RECT 44.030 39.435 44.200 44.475 ;
        RECT 44.510 39.435 44.680 44.475 ;
        RECT 44.990 39.435 45.160 44.475 ;
        RECT 45.470 39.435 45.640 44.475 ;
        RECT 45.950 39.435 46.120 44.475 ;
        RECT 46.430 39.435 46.600 44.475 ;
        RECT 46.910 39.435 47.080 44.475 ;
        RECT 47.390 39.435 47.560 44.475 ;
        RECT 47.870 39.435 48.040 44.475 ;
        RECT 48.350 39.435 48.520 44.475 ;
        RECT 48.830 39.435 49.000 44.475 ;
        RECT 49.310 39.435 49.480 44.475 ;
        RECT 49.790 39.435 49.960 44.475 ;
        RECT 50.270 39.435 50.440 44.475 ;
        RECT 50.750 39.435 50.920 44.475 ;
        RECT 51.230 39.435 51.400 44.475 ;
        RECT 51.710 39.435 51.880 44.475 ;
        RECT 52.190 39.435 52.360 44.475 ;
        RECT 52.670 39.435 52.840 44.475 ;
        RECT 53.150 39.435 53.320 44.475 ;
        RECT 14.910 39.050 15.240 39.220 ;
        RECT 15.870 39.050 16.200 39.220 ;
        RECT 16.830 39.050 17.160 39.220 ;
        RECT 17.790 39.050 18.120 39.220 ;
        RECT 18.750 39.050 19.080 39.220 ;
        RECT 19.710 39.050 20.040 39.220 ;
        RECT 20.670 39.050 21.000 39.220 ;
        RECT 21.630 39.050 21.960 39.220 ;
        RECT 22.590 39.050 22.920 39.220 ;
        RECT 23.550 39.050 23.880 39.220 ;
        RECT 24.510 39.050 24.840 39.220 ;
        RECT 25.470 39.050 25.800 39.220 ;
        RECT 26.430 39.050 26.760 39.220 ;
        RECT 27.390 39.050 27.720 39.220 ;
        RECT 28.350 39.050 28.680 39.220 ;
        RECT 29.310 39.050 29.640 39.220 ;
        RECT 30.270 39.050 30.600 39.220 ;
        RECT 31.230 39.050 31.560 39.220 ;
        RECT 32.190 39.050 32.520 39.220 ;
        RECT 33.150 39.050 33.480 39.220 ;
        RECT 34.110 39.050 34.440 39.220 ;
        RECT 35.070 39.050 35.400 39.220 ;
        RECT 36.030 39.050 36.360 39.220 ;
        RECT 36.990 39.050 37.320 39.220 ;
        RECT 37.950 39.050 38.280 39.220 ;
        RECT 38.910 39.050 39.240 39.220 ;
        RECT 39.870 39.050 40.200 39.220 ;
        RECT 40.830 39.050 41.160 39.220 ;
        RECT 41.790 39.050 42.120 39.220 ;
        RECT 42.750 39.050 43.080 39.220 ;
        RECT 43.710 39.050 44.040 39.220 ;
        RECT 44.670 39.050 45.000 39.220 ;
        RECT 45.630 39.050 45.960 39.220 ;
        RECT 46.590 39.050 46.920 39.220 ;
        RECT 47.550 39.050 47.880 39.220 ;
        RECT 48.510 39.050 48.840 39.220 ;
        RECT 49.470 39.050 49.800 39.220 ;
        RECT 50.430 39.050 50.760 39.220 ;
        RECT 51.390 39.050 51.720 39.220 ;
        RECT 52.350 39.050 52.680 39.220 ;
        RECT 14.910 38.510 15.240 38.680 ;
        RECT 15.870 38.510 16.200 38.680 ;
        RECT 16.830 38.510 17.160 38.680 ;
        RECT 17.790 38.510 18.120 38.680 ;
        RECT 18.750 38.510 19.080 38.680 ;
        RECT 19.710 38.510 20.040 38.680 ;
        RECT 20.670 38.510 21.000 38.680 ;
        RECT 21.630 38.510 21.960 38.680 ;
        RECT 22.590 38.510 22.920 38.680 ;
        RECT 23.550 38.510 23.880 38.680 ;
        RECT 24.510 38.510 24.840 38.680 ;
        RECT 25.470 38.510 25.800 38.680 ;
        RECT 26.430 38.510 26.760 38.680 ;
        RECT 27.390 38.510 27.720 38.680 ;
        RECT 28.350 38.510 28.680 38.680 ;
        RECT 29.310 38.510 29.640 38.680 ;
        RECT 30.270 38.510 30.600 38.680 ;
        RECT 31.230 38.510 31.560 38.680 ;
        RECT 32.190 38.510 32.520 38.680 ;
        RECT 33.150 38.510 33.480 38.680 ;
        RECT 34.110 38.510 34.440 38.680 ;
        RECT 35.070 38.510 35.400 38.680 ;
        RECT 36.030 38.510 36.360 38.680 ;
        RECT 36.990 38.510 37.320 38.680 ;
        RECT 37.950 38.510 38.280 38.680 ;
        RECT 38.910 38.510 39.240 38.680 ;
        RECT 39.870 38.510 40.200 38.680 ;
        RECT 40.830 38.510 41.160 38.680 ;
        RECT 41.790 38.510 42.120 38.680 ;
        RECT 42.750 38.510 43.080 38.680 ;
        RECT 43.710 38.510 44.040 38.680 ;
        RECT 44.670 38.510 45.000 38.680 ;
        RECT 45.630 38.510 45.960 38.680 ;
        RECT 46.590 38.510 46.920 38.680 ;
        RECT 47.550 38.510 47.880 38.680 ;
        RECT 48.510 38.510 48.840 38.680 ;
        RECT 49.470 38.510 49.800 38.680 ;
        RECT 50.430 38.510 50.760 38.680 ;
        RECT 51.390 38.510 51.720 38.680 ;
        RECT 52.350 38.510 52.680 38.680 ;
        RECT 14.750 33.255 14.920 38.295 ;
        RECT 15.230 33.255 15.400 38.295 ;
        RECT 15.710 33.255 15.880 38.295 ;
        RECT 16.190 33.255 16.360 38.295 ;
        RECT 16.670 33.255 16.840 38.295 ;
        RECT 17.150 33.255 17.320 38.295 ;
        RECT 17.630 33.255 17.800 38.295 ;
        RECT 18.110 33.255 18.280 38.295 ;
        RECT 18.590 33.255 18.760 38.295 ;
        RECT 19.070 33.255 19.240 38.295 ;
        RECT 19.550 33.255 19.720 38.295 ;
        RECT 20.030 33.255 20.200 38.295 ;
        RECT 20.510 33.255 20.680 38.295 ;
        RECT 20.990 33.255 21.160 38.295 ;
        RECT 21.470 33.255 21.640 38.295 ;
        RECT 21.950 33.255 22.120 38.295 ;
        RECT 22.430 33.255 22.600 38.295 ;
        RECT 22.910 33.255 23.080 38.295 ;
        RECT 23.390 33.255 23.560 38.295 ;
        RECT 23.870 33.255 24.040 38.295 ;
        RECT 24.350 33.255 24.520 38.295 ;
        RECT 24.830 33.255 25.000 38.295 ;
        RECT 25.310 33.255 25.480 38.295 ;
        RECT 25.790 33.255 25.960 38.295 ;
        RECT 26.270 33.255 26.440 38.295 ;
        RECT 26.750 33.255 26.920 38.295 ;
        RECT 27.230 33.255 27.400 38.295 ;
        RECT 27.710 33.255 27.880 38.295 ;
        RECT 28.190 33.255 28.360 38.295 ;
        RECT 28.670 33.255 28.840 38.295 ;
        RECT 29.150 33.255 29.320 38.295 ;
        RECT 29.630 33.255 29.800 38.295 ;
        RECT 30.110 33.255 30.280 38.295 ;
        RECT 30.590 33.255 30.760 38.295 ;
        RECT 31.070 33.255 31.240 38.295 ;
        RECT 31.550 33.255 31.720 38.295 ;
        RECT 32.030 33.255 32.200 38.295 ;
        RECT 32.510 33.255 32.680 38.295 ;
        RECT 32.990 33.255 33.160 38.295 ;
        RECT 33.470 33.255 33.640 38.295 ;
        RECT 33.950 33.255 34.120 38.295 ;
        RECT 34.430 33.255 34.600 38.295 ;
        RECT 34.910 33.255 35.080 38.295 ;
        RECT 35.390 33.255 35.560 38.295 ;
        RECT 35.870 33.255 36.040 38.295 ;
        RECT 36.350 33.255 36.520 38.295 ;
        RECT 36.830 33.255 37.000 38.295 ;
        RECT 37.310 33.255 37.480 38.295 ;
        RECT 37.790 33.255 37.960 38.295 ;
        RECT 38.270 33.255 38.440 38.295 ;
        RECT 38.750 33.255 38.920 38.295 ;
        RECT 39.230 33.255 39.400 38.295 ;
        RECT 39.710 33.255 39.880 38.295 ;
        RECT 40.190 33.255 40.360 38.295 ;
        RECT 40.670 33.255 40.840 38.295 ;
        RECT 41.150 33.255 41.320 38.295 ;
        RECT 41.630 33.255 41.800 38.295 ;
        RECT 42.110 33.255 42.280 38.295 ;
        RECT 42.590 33.255 42.760 38.295 ;
        RECT 43.070 33.255 43.240 38.295 ;
        RECT 43.550 33.255 43.720 38.295 ;
        RECT 44.030 33.255 44.200 38.295 ;
        RECT 44.510 33.255 44.680 38.295 ;
        RECT 44.990 33.255 45.160 38.295 ;
        RECT 45.470 33.255 45.640 38.295 ;
        RECT 45.950 33.255 46.120 38.295 ;
        RECT 46.430 33.255 46.600 38.295 ;
        RECT 46.910 33.255 47.080 38.295 ;
        RECT 47.390 33.255 47.560 38.295 ;
        RECT 47.870 33.255 48.040 38.295 ;
        RECT 48.350 33.255 48.520 38.295 ;
        RECT 48.830 33.255 49.000 38.295 ;
        RECT 49.310 33.255 49.480 38.295 ;
        RECT 49.790 33.255 49.960 38.295 ;
        RECT 50.270 33.255 50.440 38.295 ;
        RECT 50.750 33.255 50.920 38.295 ;
        RECT 51.230 33.255 51.400 38.295 ;
        RECT 51.710 33.255 51.880 38.295 ;
        RECT 52.190 33.255 52.360 38.295 ;
        RECT 52.670 33.255 52.840 38.295 ;
        RECT 53.150 33.255 53.320 38.295 ;
        RECT 15.390 32.870 15.720 33.040 ;
        RECT 16.350 32.870 16.680 33.040 ;
        RECT 17.310 32.870 17.640 33.040 ;
        RECT 18.270 32.870 18.600 33.040 ;
        RECT 19.230 32.870 19.560 33.040 ;
        RECT 20.190 32.870 20.520 33.040 ;
        RECT 21.150 32.870 21.480 33.040 ;
        RECT 22.110 32.870 22.440 33.040 ;
        RECT 23.070 32.870 23.400 33.040 ;
        RECT 24.030 32.870 24.360 33.040 ;
        RECT 24.990 32.870 25.320 33.040 ;
        RECT 25.950 32.870 26.280 33.040 ;
        RECT 26.910 32.870 27.240 33.040 ;
        RECT 27.870 32.870 28.200 33.040 ;
        RECT 28.830 32.870 29.160 33.040 ;
        RECT 29.790 32.870 30.120 33.040 ;
        RECT 30.750 32.870 31.080 33.040 ;
        RECT 31.710 32.870 32.040 33.040 ;
        RECT 32.670 32.870 33.000 33.040 ;
        RECT 33.630 32.870 33.960 33.040 ;
        RECT 34.590 32.870 34.920 33.040 ;
        RECT 35.550 32.870 35.880 33.040 ;
        RECT 36.510 32.870 36.840 33.040 ;
        RECT 37.470 32.870 37.800 33.040 ;
        RECT 38.430 32.870 38.760 33.040 ;
        RECT 39.390 32.870 39.720 33.040 ;
        RECT 40.350 32.870 40.680 33.040 ;
        RECT 41.310 32.870 41.640 33.040 ;
        RECT 42.270 32.870 42.600 33.040 ;
        RECT 43.230 32.870 43.560 33.040 ;
        RECT 44.190 32.870 44.520 33.040 ;
        RECT 45.150 32.870 45.480 33.040 ;
        RECT 46.110 32.870 46.440 33.040 ;
        RECT 47.070 32.870 47.400 33.040 ;
        RECT 48.030 32.870 48.360 33.040 ;
        RECT 48.990 32.870 49.320 33.040 ;
        RECT 49.950 32.870 50.280 33.040 ;
        RECT 50.910 32.870 51.240 33.040 ;
        RECT 51.870 32.870 52.200 33.040 ;
        RECT 52.830 32.870 53.160 33.040 ;
        RECT 15.390 32.330 15.720 32.500 ;
        RECT 16.350 32.330 16.680 32.500 ;
        RECT 17.310 32.330 17.640 32.500 ;
        RECT 18.270 32.330 18.600 32.500 ;
        RECT 19.230 32.330 19.560 32.500 ;
        RECT 20.190 32.330 20.520 32.500 ;
        RECT 21.150 32.330 21.480 32.500 ;
        RECT 22.110 32.330 22.440 32.500 ;
        RECT 23.070 32.330 23.400 32.500 ;
        RECT 24.030 32.330 24.360 32.500 ;
        RECT 24.990 32.330 25.320 32.500 ;
        RECT 25.950 32.330 26.280 32.500 ;
        RECT 26.910 32.330 27.240 32.500 ;
        RECT 27.870 32.330 28.200 32.500 ;
        RECT 28.830 32.330 29.160 32.500 ;
        RECT 29.790 32.330 30.120 32.500 ;
        RECT 30.750 32.330 31.080 32.500 ;
        RECT 31.710 32.330 32.040 32.500 ;
        RECT 32.670 32.330 33.000 32.500 ;
        RECT 33.630 32.330 33.960 32.500 ;
        RECT 34.590 32.330 34.920 32.500 ;
        RECT 35.550 32.330 35.880 32.500 ;
        RECT 36.510 32.330 36.840 32.500 ;
        RECT 37.470 32.330 37.800 32.500 ;
        RECT 38.430 32.330 38.760 32.500 ;
        RECT 39.390 32.330 39.720 32.500 ;
        RECT 40.350 32.330 40.680 32.500 ;
        RECT 41.310 32.330 41.640 32.500 ;
        RECT 42.270 32.330 42.600 32.500 ;
        RECT 43.230 32.330 43.560 32.500 ;
        RECT 44.190 32.330 44.520 32.500 ;
        RECT 45.150 32.330 45.480 32.500 ;
        RECT 46.110 32.330 46.440 32.500 ;
        RECT 47.070 32.330 47.400 32.500 ;
        RECT 48.030 32.330 48.360 32.500 ;
        RECT 48.990 32.330 49.320 32.500 ;
        RECT 49.950 32.330 50.280 32.500 ;
        RECT 50.910 32.330 51.240 32.500 ;
        RECT 51.870 32.330 52.200 32.500 ;
        RECT 52.830 32.330 53.160 32.500 ;
        RECT 14.750 27.075 14.920 32.115 ;
        RECT 15.230 27.075 15.400 32.115 ;
        RECT 15.710 27.075 15.880 32.115 ;
        RECT 16.190 27.075 16.360 32.115 ;
        RECT 16.670 27.075 16.840 32.115 ;
        RECT 17.150 27.075 17.320 32.115 ;
        RECT 17.630 27.075 17.800 32.115 ;
        RECT 18.110 27.075 18.280 32.115 ;
        RECT 18.590 27.075 18.760 32.115 ;
        RECT 19.070 27.075 19.240 32.115 ;
        RECT 19.550 27.075 19.720 32.115 ;
        RECT 20.030 27.075 20.200 32.115 ;
        RECT 20.510 27.075 20.680 32.115 ;
        RECT 20.990 27.075 21.160 32.115 ;
        RECT 21.470 27.075 21.640 32.115 ;
        RECT 21.950 27.075 22.120 32.115 ;
        RECT 22.430 27.075 22.600 32.115 ;
        RECT 22.910 27.075 23.080 32.115 ;
        RECT 23.390 27.075 23.560 32.115 ;
        RECT 23.870 27.075 24.040 32.115 ;
        RECT 24.350 27.075 24.520 32.115 ;
        RECT 24.830 27.075 25.000 32.115 ;
        RECT 25.310 27.075 25.480 32.115 ;
        RECT 25.790 27.075 25.960 32.115 ;
        RECT 26.270 27.075 26.440 32.115 ;
        RECT 26.750 27.075 26.920 32.115 ;
        RECT 27.230 27.075 27.400 32.115 ;
        RECT 27.710 27.075 27.880 32.115 ;
        RECT 28.190 27.075 28.360 32.115 ;
        RECT 28.670 27.075 28.840 32.115 ;
        RECT 29.150 27.075 29.320 32.115 ;
        RECT 29.630 27.075 29.800 32.115 ;
        RECT 30.110 27.075 30.280 32.115 ;
        RECT 30.590 27.075 30.760 32.115 ;
        RECT 31.070 27.075 31.240 32.115 ;
        RECT 31.550 27.075 31.720 32.115 ;
        RECT 32.030 27.075 32.200 32.115 ;
        RECT 32.510 27.075 32.680 32.115 ;
        RECT 32.990 27.075 33.160 32.115 ;
        RECT 33.470 27.075 33.640 32.115 ;
        RECT 33.950 27.075 34.120 32.115 ;
        RECT 34.430 27.075 34.600 32.115 ;
        RECT 34.910 27.075 35.080 32.115 ;
        RECT 35.390 27.075 35.560 32.115 ;
        RECT 35.870 27.075 36.040 32.115 ;
        RECT 36.350 27.075 36.520 32.115 ;
        RECT 36.830 27.075 37.000 32.115 ;
        RECT 37.310 27.075 37.480 32.115 ;
        RECT 37.790 27.075 37.960 32.115 ;
        RECT 38.270 27.075 38.440 32.115 ;
        RECT 38.750 27.075 38.920 32.115 ;
        RECT 39.230 27.075 39.400 32.115 ;
        RECT 39.710 27.075 39.880 32.115 ;
        RECT 40.190 27.075 40.360 32.115 ;
        RECT 40.670 27.075 40.840 32.115 ;
        RECT 41.150 27.075 41.320 32.115 ;
        RECT 41.630 27.075 41.800 32.115 ;
        RECT 42.110 27.075 42.280 32.115 ;
        RECT 42.590 27.075 42.760 32.115 ;
        RECT 43.070 27.075 43.240 32.115 ;
        RECT 43.550 27.075 43.720 32.115 ;
        RECT 44.030 27.075 44.200 32.115 ;
        RECT 44.510 27.075 44.680 32.115 ;
        RECT 44.990 27.075 45.160 32.115 ;
        RECT 45.470 27.075 45.640 32.115 ;
        RECT 45.950 27.075 46.120 32.115 ;
        RECT 46.430 27.075 46.600 32.115 ;
        RECT 46.910 27.075 47.080 32.115 ;
        RECT 47.390 27.075 47.560 32.115 ;
        RECT 47.870 27.075 48.040 32.115 ;
        RECT 48.350 27.075 48.520 32.115 ;
        RECT 48.830 27.075 49.000 32.115 ;
        RECT 49.310 27.075 49.480 32.115 ;
        RECT 49.790 27.075 49.960 32.115 ;
        RECT 50.270 27.075 50.440 32.115 ;
        RECT 50.750 27.075 50.920 32.115 ;
        RECT 51.230 27.075 51.400 32.115 ;
        RECT 51.710 27.075 51.880 32.115 ;
        RECT 52.190 27.075 52.360 32.115 ;
        RECT 52.670 27.075 52.840 32.115 ;
        RECT 53.150 27.075 53.320 32.115 ;
        RECT 14.910 26.690 15.240 26.860 ;
        RECT 15.870 26.690 16.200 26.860 ;
        RECT 16.830 26.690 17.160 26.860 ;
        RECT 17.790 26.690 18.120 26.860 ;
        RECT 18.750 26.690 19.080 26.860 ;
        RECT 19.710 26.690 20.040 26.860 ;
        RECT 20.670 26.690 21.000 26.860 ;
        RECT 21.630 26.690 21.960 26.860 ;
        RECT 22.590 26.690 22.920 26.860 ;
        RECT 23.550 26.690 23.880 26.860 ;
        RECT 24.510 26.690 24.840 26.860 ;
        RECT 25.470 26.690 25.800 26.860 ;
        RECT 26.430 26.690 26.760 26.860 ;
        RECT 27.390 26.690 27.720 26.860 ;
        RECT 28.350 26.690 28.680 26.860 ;
        RECT 29.310 26.690 29.640 26.860 ;
        RECT 30.270 26.690 30.600 26.860 ;
        RECT 31.230 26.690 31.560 26.860 ;
        RECT 32.190 26.690 32.520 26.860 ;
        RECT 33.150 26.690 33.480 26.860 ;
        RECT 34.110 26.690 34.440 26.860 ;
        RECT 35.070 26.690 35.400 26.860 ;
        RECT 36.030 26.690 36.360 26.860 ;
        RECT 36.990 26.690 37.320 26.860 ;
        RECT 37.950 26.690 38.280 26.860 ;
        RECT 38.910 26.690 39.240 26.860 ;
        RECT 39.870 26.690 40.200 26.860 ;
        RECT 40.830 26.690 41.160 26.860 ;
        RECT 41.790 26.690 42.120 26.860 ;
        RECT 42.750 26.690 43.080 26.860 ;
        RECT 43.710 26.690 44.040 26.860 ;
        RECT 44.670 26.690 45.000 26.860 ;
        RECT 45.630 26.690 45.960 26.860 ;
        RECT 46.590 26.690 46.920 26.860 ;
        RECT 47.550 26.690 47.880 26.860 ;
        RECT 48.510 26.690 48.840 26.860 ;
        RECT 49.470 26.690 49.800 26.860 ;
        RECT 50.430 26.690 50.760 26.860 ;
        RECT 51.390 26.690 51.720 26.860 ;
        RECT 52.350 26.690 52.680 26.860 ;
        RECT 53.085 26.350 53.315 26.380 ;
        RECT 53.720 26.350 53.890 57.560 ;
        RECT 57.000 44.300 59.850 46.460 ;
        RECT 57.000 30.000 59.850 32.160 ;
        RECT 14.180 26.180 53.890 26.350 ;
        RECT 53.085 26.150 53.315 26.180 ;
        RECT 16.830 24.660 22.880 24.830 ;
        RECT 16.830 18.260 17.000 24.660 ;
        RECT 17.630 24.150 18.130 24.320 ;
        RECT 18.420 24.150 18.920 24.320 ;
        RECT 19.210 24.150 19.710 24.320 ;
        RECT 20.000 24.150 20.500 24.320 ;
        RECT 20.790 24.150 21.290 24.320 ;
        RECT 21.580 24.150 22.080 24.320 ;
        RECT 17.400 18.940 17.570 23.980 ;
        RECT 18.190 18.940 18.360 23.980 ;
        RECT 18.980 18.940 19.150 23.980 ;
        RECT 19.770 18.940 19.940 23.980 ;
        RECT 20.560 18.940 20.730 23.980 ;
        RECT 21.350 18.940 21.520 23.980 ;
        RECT 22.140 18.940 22.310 23.980 ;
        RECT 17.630 18.600 18.130 18.770 ;
        RECT 18.420 18.600 18.920 18.770 ;
        RECT 19.210 18.600 19.710 18.770 ;
        RECT 20.000 18.600 20.500 18.770 ;
        RECT 20.790 18.600 21.290 18.770 ;
        RECT 21.580 18.600 22.080 18.770 ;
        RECT 21.385 18.260 21.615 18.310 ;
        RECT 22.710 18.260 22.880 24.660 ;
        RECT 24.610 22.260 26.020 24.420 ;
        RECT 24.610 18.900 26.020 21.060 ;
        RECT 16.830 18.090 22.880 18.260 ;
        RECT 21.385 18.080 21.615 18.090 ;
      LAYER met1 ;
        RECT 156.050 123.760 156.300 124.625 ;
        RECT 156.015 123.440 156.335 123.760 ;
        RECT 156.050 122.520 156.300 123.440 ;
        RECT 153.050 106.160 153.300 107.130 ;
        RECT 152.985 105.840 153.365 106.160 ;
        RECT 153.050 105.025 153.300 105.840 ;
        RECT 80.050 102.225 80.640 104.330 ;
        RECT 80.050 99.030 80.640 101.135 ;
        RECT 137.420 92.745 137.780 93.105 ;
        RECT 141.420 92.745 141.780 93.105 ;
        RECT 137.000 92.300 137.460 92.530 ;
        RECT 141.000 92.300 141.460 92.530 ;
        RECT 16.220 91.745 16.580 92.105 ;
        RECT 61.120 91.745 61.480 92.105 ;
        RECT 84.970 91.745 85.330 92.105 ;
        RECT 15.000 91.500 15.460 91.530 ;
        RECT 15.790 91.500 16.250 91.530 ;
        RECT 16.580 91.500 17.040 91.530 ;
        RECT 17.370 91.500 17.830 91.530 ;
        RECT 18.160 91.500 18.620 91.530 ;
        RECT 22.000 91.500 22.460 91.530 ;
        RECT 22.790 91.500 23.250 91.530 ;
        RECT 23.580 91.500 24.040 91.530 ;
        RECT 24.370 91.500 24.830 91.530 ;
        RECT 25.160 91.500 25.620 91.530 ;
        RECT 25.950 91.500 26.410 91.530 ;
        RECT 26.740 91.500 27.200 91.530 ;
        RECT 27.530 91.500 27.990 91.530 ;
        RECT 28.320 91.500 28.780 91.530 ;
        RECT 29.110 91.500 29.570 91.530 ;
        RECT 29.900 91.500 30.360 91.530 ;
        RECT 30.690 91.500 31.150 91.530 ;
        RECT 31.480 91.500 31.940 91.530 ;
        RECT 32.270 91.500 32.730 91.530 ;
        RECT 33.060 91.500 33.520 91.530 ;
        RECT 33.850 91.500 34.310 91.530 ;
        RECT 34.640 91.500 35.100 91.530 ;
        RECT 35.430 91.500 35.890 91.530 ;
        RECT 36.220 91.500 36.680 91.530 ;
        RECT 37.010 91.500 37.470 91.530 ;
        RECT 37.800 91.500 38.260 91.530 ;
        RECT 38.590 91.500 39.050 91.530 ;
        RECT 39.380 91.500 39.840 91.530 ;
        RECT 40.170 91.500 40.630 91.530 ;
        RECT 40.960 91.500 41.420 91.530 ;
        RECT 41.750 91.500 42.210 91.530 ;
        RECT 42.540 91.500 43.000 91.530 ;
        RECT 43.330 91.500 43.790 91.530 ;
        RECT 44.120 91.500 44.580 91.530 ;
        RECT 44.910 91.500 45.370 91.530 ;
        RECT 45.700 91.500 46.160 91.530 ;
        RECT 46.490 91.500 46.950 91.530 ;
        RECT 47.280 91.500 47.740 91.530 ;
        RECT 48.070 91.500 48.530 91.530 ;
        RECT 48.860 91.500 49.320 91.530 ;
        RECT 49.650 91.500 50.110 91.530 ;
        RECT 50.440 91.500 50.900 91.530 ;
        RECT 51.230 91.500 51.690 91.530 ;
        RECT 52.020 91.500 52.480 91.530 ;
        RECT 52.810 91.500 53.270 91.530 ;
        RECT 53.600 91.500 54.060 91.530 ;
        RECT 54.390 91.500 54.850 91.530 ;
        RECT 55.180 91.500 55.640 91.530 ;
        RECT 55.970 91.500 56.430 91.530 ;
        RECT 56.760 91.500 57.220 91.530 ;
        RECT 57.550 91.500 58.010 91.530 ;
        RECT 58.340 91.500 58.800 91.530 ;
        RECT 59.130 91.500 59.590 91.530 ;
        RECT 59.920 91.500 60.380 91.530 ;
        RECT 60.710 91.500 61.170 91.530 ;
        RECT 79.000 91.500 79.460 91.530 ;
        RECT 79.790 91.500 80.250 91.530 ;
        RECT 80.580 91.500 81.040 91.530 ;
        RECT 81.370 91.500 81.830 91.530 ;
        RECT 82.160 91.500 82.620 91.530 ;
        RECT 82.950 91.500 83.410 91.530 ;
        RECT 83.740 91.500 84.200 91.530 ;
        RECT 84.530 91.500 84.990 91.530 ;
        RECT 85.320 91.500 85.780 91.530 ;
        RECT 86.110 91.500 86.570 91.530 ;
        RECT 86.900 91.500 87.360 91.530 ;
        RECT 87.690 91.500 88.150 91.530 ;
        RECT 14.980 91.330 18.640 91.500 ;
        RECT 21.980 91.330 61.190 91.500 ;
        RECT 78.980 91.330 88.170 91.500 ;
        RECT 15.000 91.300 15.460 91.330 ;
        RECT 15.790 91.300 16.250 91.330 ;
        RECT 16.580 91.300 17.040 91.330 ;
        RECT 17.370 91.300 17.830 91.330 ;
        RECT 18.160 91.300 18.620 91.330 ;
        RECT 22.000 91.300 22.460 91.330 ;
        RECT 22.790 91.300 23.250 91.330 ;
        RECT 23.580 91.300 24.040 91.330 ;
        RECT 24.370 91.300 24.830 91.330 ;
        RECT 25.160 91.300 25.620 91.330 ;
        RECT 25.950 91.300 26.410 91.330 ;
        RECT 26.740 91.300 27.200 91.330 ;
        RECT 27.530 91.300 27.990 91.330 ;
        RECT 28.320 91.300 28.780 91.330 ;
        RECT 29.110 91.300 29.570 91.330 ;
        RECT 29.900 91.300 30.360 91.330 ;
        RECT 30.690 91.300 31.150 91.330 ;
        RECT 31.480 91.300 31.940 91.330 ;
        RECT 32.270 91.300 32.730 91.330 ;
        RECT 33.060 91.300 33.520 91.330 ;
        RECT 33.850 91.300 34.310 91.330 ;
        RECT 34.640 91.300 35.100 91.330 ;
        RECT 35.430 91.300 35.890 91.330 ;
        RECT 36.220 91.300 36.680 91.330 ;
        RECT 37.010 91.300 37.470 91.330 ;
        RECT 37.800 91.300 38.260 91.330 ;
        RECT 38.590 91.300 39.050 91.330 ;
        RECT 39.380 91.300 39.840 91.330 ;
        RECT 40.170 91.300 40.630 91.330 ;
        RECT 40.960 91.300 41.420 91.330 ;
        RECT 41.750 91.300 42.210 91.330 ;
        RECT 42.540 91.300 43.000 91.330 ;
        RECT 43.330 91.300 43.790 91.330 ;
        RECT 44.120 91.300 44.580 91.330 ;
        RECT 44.910 91.300 45.370 91.330 ;
        RECT 45.700 91.300 46.160 91.330 ;
        RECT 46.490 91.300 46.950 91.330 ;
        RECT 47.280 91.300 47.740 91.330 ;
        RECT 48.070 91.300 48.530 91.330 ;
        RECT 48.860 91.300 49.320 91.330 ;
        RECT 49.650 91.300 50.110 91.330 ;
        RECT 50.440 91.300 50.900 91.330 ;
        RECT 51.230 91.300 51.690 91.330 ;
        RECT 52.020 91.300 52.480 91.330 ;
        RECT 52.810 91.300 53.270 91.330 ;
        RECT 53.600 91.300 54.060 91.330 ;
        RECT 54.390 91.300 54.850 91.330 ;
        RECT 55.180 91.300 55.640 91.330 ;
        RECT 55.970 91.300 56.430 91.330 ;
        RECT 56.760 91.300 57.220 91.330 ;
        RECT 57.550 91.300 58.010 91.330 ;
        RECT 58.340 91.300 58.800 91.330 ;
        RECT 59.130 91.300 59.590 91.330 ;
        RECT 59.920 91.300 60.380 91.330 ;
        RECT 60.710 91.300 61.170 91.330 ;
        RECT 79.000 91.300 79.460 91.330 ;
        RECT 79.790 91.300 80.250 91.330 ;
        RECT 80.580 91.300 81.040 91.330 ;
        RECT 81.370 91.300 81.830 91.330 ;
        RECT 82.160 91.300 82.620 91.330 ;
        RECT 82.950 91.300 83.410 91.330 ;
        RECT 83.740 91.300 84.200 91.330 ;
        RECT 84.530 91.300 84.990 91.330 ;
        RECT 85.320 91.300 85.780 91.330 ;
        RECT 86.110 91.300 86.570 91.330 ;
        RECT 86.900 91.300 87.360 91.330 ;
        RECT 87.690 91.300 88.150 91.330 ;
        RECT 14.720 87.600 14.950 91.095 ;
        RECT 14.685 85.890 14.985 87.600 ;
        RECT 15.510 86.650 15.740 91.095 ;
        RECT 16.300 87.600 16.530 91.095 ;
        RECT 15.465 86.300 15.785 86.650 ;
        RECT 15.510 86.095 15.740 86.300 ;
        RECT 16.265 85.890 16.565 87.600 ;
        RECT 17.090 86.650 17.320 91.095 ;
        RECT 17.880 87.600 18.110 91.095 ;
        RECT 17.045 86.300 17.365 86.650 ;
        RECT 17.090 86.095 17.320 86.300 ;
        RECT 17.845 85.890 18.145 87.600 ;
        RECT 18.670 86.650 18.900 91.095 ;
        RECT 21.720 90.950 21.950 91.095 ;
        RECT 21.675 90.600 21.995 90.950 ;
        RECT 18.625 86.300 18.945 86.650 ;
        RECT 18.670 86.095 18.900 86.300 ;
        RECT 21.720 86.095 21.950 90.600 ;
        RECT 22.510 86.650 22.740 91.095 ;
        RECT 23.300 90.950 23.530 91.095 ;
        RECT 23.255 90.600 23.575 90.950 ;
        RECT 22.465 86.300 22.785 86.650 ;
        RECT 22.510 86.095 22.740 86.300 ;
        RECT 23.300 86.095 23.530 90.600 ;
        RECT 24.090 86.650 24.320 91.095 ;
        RECT 24.880 90.950 25.110 91.095 ;
        RECT 24.835 90.600 25.155 90.950 ;
        RECT 24.045 86.300 24.365 86.650 ;
        RECT 24.090 86.095 24.320 86.300 ;
        RECT 24.880 86.095 25.110 90.600 ;
        RECT 25.670 86.650 25.900 91.095 ;
        RECT 26.460 90.950 26.690 91.095 ;
        RECT 26.415 90.600 26.735 90.950 ;
        RECT 25.625 86.300 25.945 86.650 ;
        RECT 25.670 86.095 25.900 86.300 ;
        RECT 26.460 86.095 26.690 90.600 ;
        RECT 27.250 86.650 27.480 91.095 ;
        RECT 28.040 90.950 28.270 91.095 ;
        RECT 27.995 90.600 28.315 90.950 ;
        RECT 27.205 86.300 27.525 86.650 ;
        RECT 27.250 86.095 27.480 86.300 ;
        RECT 28.040 86.095 28.270 90.600 ;
        RECT 28.830 86.650 29.060 91.095 ;
        RECT 29.620 90.950 29.850 91.095 ;
        RECT 29.575 90.600 29.895 90.950 ;
        RECT 28.785 86.300 29.105 86.650 ;
        RECT 28.830 86.095 29.060 86.300 ;
        RECT 29.620 86.095 29.850 90.600 ;
        RECT 30.410 86.650 30.640 91.095 ;
        RECT 31.200 90.950 31.430 91.095 ;
        RECT 31.155 90.600 31.475 90.950 ;
        RECT 30.365 86.300 30.685 86.650 ;
        RECT 30.410 86.095 30.640 86.300 ;
        RECT 31.200 86.095 31.430 90.600 ;
        RECT 31.990 86.650 32.220 91.095 ;
        RECT 32.780 90.950 33.010 91.095 ;
        RECT 32.735 90.600 33.055 90.950 ;
        RECT 31.945 86.300 32.265 86.650 ;
        RECT 31.990 86.095 32.220 86.300 ;
        RECT 32.780 86.095 33.010 90.600 ;
        RECT 33.570 86.650 33.800 91.095 ;
        RECT 34.360 90.950 34.590 91.095 ;
        RECT 34.315 90.600 34.635 90.950 ;
        RECT 33.525 86.300 33.845 86.650 ;
        RECT 33.570 86.095 33.800 86.300 ;
        RECT 34.360 86.095 34.590 90.600 ;
        RECT 35.150 86.650 35.380 91.095 ;
        RECT 35.940 90.950 36.170 91.095 ;
        RECT 35.895 90.600 36.215 90.950 ;
        RECT 35.105 86.300 35.425 86.650 ;
        RECT 35.150 86.095 35.380 86.300 ;
        RECT 35.940 86.095 36.170 90.600 ;
        RECT 36.730 86.650 36.960 91.095 ;
        RECT 37.520 90.950 37.750 91.095 ;
        RECT 37.475 90.600 37.795 90.950 ;
        RECT 36.685 86.300 37.005 86.650 ;
        RECT 36.730 86.095 36.960 86.300 ;
        RECT 37.520 86.095 37.750 90.600 ;
        RECT 38.310 86.650 38.540 91.095 ;
        RECT 39.100 90.950 39.330 91.095 ;
        RECT 39.055 90.600 39.375 90.950 ;
        RECT 38.265 86.300 38.585 86.650 ;
        RECT 38.310 86.095 38.540 86.300 ;
        RECT 39.100 86.095 39.330 90.600 ;
        RECT 39.890 86.650 40.120 91.095 ;
        RECT 40.680 90.950 40.910 91.095 ;
        RECT 40.635 90.600 40.955 90.950 ;
        RECT 39.845 86.300 40.165 86.650 ;
        RECT 39.890 86.095 40.120 86.300 ;
        RECT 40.680 86.095 40.910 90.600 ;
        RECT 41.470 86.650 41.700 91.095 ;
        RECT 42.260 90.950 42.490 91.095 ;
        RECT 42.215 90.600 42.535 90.950 ;
        RECT 41.425 86.300 41.745 86.650 ;
        RECT 41.470 86.095 41.700 86.300 ;
        RECT 42.260 86.095 42.490 90.600 ;
        RECT 43.050 86.650 43.280 91.095 ;
        RECT 43.840 90.950 44.070 91.095 ;
        RECT 43.795 90.600 44.115 90.950 ;
        RECT 43.005 86.300 43.325 86.650 ;
        RECT 43.050 86.095 43.280 86.300 ;
        RECT 43.840 86.095 44.070 90.600 ;
        RECT 44.630 86.650 44.860 91.095 ;
        RECT 45.420 90.950 45.650 91.095 ;
        RECT 45.375 90.600 45.695 90.950 ;
        RECT 44.585 86.300 44.905 86.650 ;
        RECT 44.630 86.095 44.860 86.300 ;
        RECT 45.420 86.095 45.650 90.600 ;
        RECT 46.210 86.650 46.440 91.095 ;
        RECT 47.000 90.950 47.230 91.095 ;
        RECT 46.955 90.600 47.275 90.950 ;
        RECT 46.165 86.300 46.485 86.650 ;
        RECT 46.210 86.095 46.440 86.300 ;
        RECT 47.000 86.095 47.230 90.600 ;
        RECT 47.790 86.650 48.020 91.095 ;
        RECT 48.580 90.950 48.810 91.095 ;
        RECT 48.535 90.600 48.855 90.950 ;
        RECT 47.745 86.300 48.065 86.650 ;
        RECT 47.790 86.095 48.020 86.300 ;
        RECT 48.580 86.095 48.810 90.600 ;
        RECT 49.370 86.650 49.600 91.095 ;
        RECT 50.160 90.950 50.390 91.095 ;
        RECT 50.115 90.600 50.435 90.950 ;
        RECT 49.325 86.300 49.645 86.650 ;
        RECT 49.370 86.095 49.600 86.300 ;
        RECT 50.160 86.095 50.390 90.600 ;
        RECT 50.950 86.650 51.180 91.095 ;
        RECT 51.740 90.950 51.970 91.095 ;
        RECT 51.695 90.600 52.015 90.950 ;
        RECT 50.905 86.300 51.225 86.650 ;
        RECT 50.950 86.095 51.180 86.300 ;
        RECT 51.740 86.095 51.970 90.600 ;
        RECT 52.530 86.650 52.760 91.095 ;
        RECT 53.320 90.950 53.550 91.095 ;
        RECT 53.275 90.600 53.595 90.950 ;
        RECT 52.485 86.300 52.805 86.650 ;
        RECT 52.530 86.095 52.760 86.300 ;
        RECT 53.320 86.095 53.550 90.600 ;
        RECT 54.110 86.650 54.340 91.095 ;
        RECT 54.900 90.950 55.130 91.095 ;
        RECT 54.855 90.600 55.175 90.950 ;
        RECT 54.065 86.300 54.385 86.650 ;
        RECT 54.110 86.095 54.340 86.300 ;
        RECT 54.900 86.095 55.130 90.600 ;
        RECT 55.690 86.650 55.920 91.095 ;
        RECT 56.480 90.950 56.710 91.095 ;
        RECT 56.435 90.600 56.755 90.950 ;
        RECT 55.645 86.300 55.965 86.650 ;
        RECT 55.690 86.095 55.920 86.300 ;
        RECT 56.480 86.095 56.710 90.600 ;
        RECT 57.270 86.650 57.500 91.095 ;
        RECT 58.060 90.950 58.290 91.095 ;
        RECT 58.015 90.600 58.335 90.950 ;
        RECT 57.225 86.300 57.545 86.650 ;
        RECT 57.270 86.095 57.500 86.300 ;
        RECT 58.060 86.095 58.290 90.600 ;
        RECT 58.850 86.650 59.080 91.095 ;
        RECT 59.640 90.950 59.870 91.095 ;
        RECT 59.595 90.600 59.915 90.950 ;
        RECT 58.805 86.300 59.125 86.650 ;
        RECT 58.850 86.095 59.080 86.300 ;
        RECT 59.640 86.095 59.870 90.600 ;
        RECT 60.430 86.650 60.660 91.095 ;
        RECT 61.220 90.950 61.450 91.095 ;
        RECT 61.175 90.600 61.495 90.950 ;
        RECT 60.385 86.300 60.705 86.650 ;
        RECT 60.430 86.095 60.660 86.300 ;
        RECT 61.220 86.095 61.450 90.600 ;
        RECT 78.720 86.660 78.950 91.095 ;
        RECT 79.510 90.660 79.740 91.095 ;
        RECT 79.465 90.340 79.785 90.660 ;
        RECT 78.675 86.340 78.995 86.660 ;
        RECT 78.720 86.095 78.950 86.340 ;
        RECT 79.510 86.095 79.740 90.340 ;
        RECT 80.300 86.660 80.530 91.095 ;
        RECT 81.090 90.660 81.320 91.095 ;
        RECT 81.045 90.340 81.365 90.660 ;
        RECT 80.255 86.340 80.575 86.660 ;
        RECT 80.300 86.095 80.530 86.340 ;
        RECT 81.090 86.095 81.320 90.340 ;
        RECT 81.880 86.660 82.110 91.095 ;
        RECT 82.670 90.660 82.900 91.095 ;
        RECT 82.625 90.340 82.945 90.660 ;
        RECT 81.835 86.340 82.155 86.660 ;
        RECT 81.880 86.095 82.110 86.340 ;
        RECT 82.670 86.095 82.900 90.340 ;
        RECT 83.460 86.660 83.690 91.095 ;
        RECT 84.250 90.660 84.480 91.095 ;
        RECT 84.205 90.340 84.525 90.660 ;
        RECT 83.415 86.340 83.735 86.660 ;
        RECT 83.460 86.095 83.690 86.340 ;
        RECT 84.250 86.095 84.480 90.340 ;
        RECT 85.040 86.660 85.270 91.095 ;
        RECT 85.830 90.660 86.060 91.095 ;
        RECT 85.785 90.340 86.105 90.660 ;
        RECT 84.995 86.340 85.315 86.660 ;
        RECT 85.040 86.095 85.270 86.340 ;
        RECT 85.830 86.095 86.060 90.340 ;
        RECT 86.620 86.660 86.850 91.095 ;
        RECT 87.410 90.660 87.640 91.095 ;
        RECT 87.365 90.340 87.685 90.660 ;
        RECT 86.575 86.340 86.895 86.660 ;
        RECT 86.620 86.095 86.850 86.340 ;
        RECT 87.410 86.095 87.640 90.340 ;
        RECT 88.200 86.660 88.430 91.095 ;
        RECT 136.720 87.590 136.950 92.095 ;
        RECT 137.510 91.950 137.740 92.095 ;
        RECT 137.465 91.600 137.785 91.950 ;
        RECT 136.645 87.210 137.025 87.590 ;
        RECT 136.720 87.095 136.950 87.210 ;
        RECT 137.510 87.095 137.740 91.600 ;
        RECT 140.720 87.610 140.950 92.095 ;
        RECT 141.510 91.950 141.740 92.095 ;
        RECT 141.465 91.600 141.785 91.950 ;
        RECT 140.675 87.290 140.995 87.610 ;
        RECT 140.720 87.095 140.950 87.290 ;
        RECT 141.510 87.095 141.740 91.600 ;
        RECT 137.120 86.890 137.480 86.955 ;
        RECT 137.000 86.860 137.480 86.890 ;
        RECT 141.000 86.860 141.460 86.890 ;
        RECT 136.980 86.690 141.480 86.860 ;
        RECT 137.000 86.660 137.480 86.690 ;
        RECT 141.000 86.660 141.460 86.690 ;
        RECT 88.155 86.340 88.475 86.660 ;
        RECT 137.120 86.595 137.480 86.660 ;
        RECT 88.200 86.095 88.430 86.340 ;
        RECT 14.685 85.860 15.460 85.890 ;
        RECT 15.790 85.860 17.040 85.890 ;
        RECT 17.370 85.860 18.620 85.890 ;
        RECT 22.000 85.860 22.460 85.890 ;
        RECT 22.790 85.860 23.250 85.890 ;
        RECT 23.580 85.860 24.040 85.890 ;
        RECT 24.370 85.860 24.830 85.890 ;
        RECT 25.160 85.860 25.620 85.890 ;
        RECT 25.950 85.860 26.410 85.890 ;
        RECT 26.740 85.860 27.200 85.890 ;
        RECT 27.530 85.860 27.990 85.890 ;
        RECT 28.320 85.860 28.780 85.890 ;
        RECT 29.110 85.860 29.570 85.890 ;
        RECT 29.900 85.860 30.360 85.890 ;
        RECT 30.690 85.860 31.150 85.890 ;
        RECT 31.480 85.860 31.940 85.890 ;
        RECT 32.270 85.860 32.730 85.890 ;
        RECT 33.060 85.860 33.520 85.890 ;
        RECT 33.850 85.860 34.310 85.890 ;
        RECT 34.640 85.860 35.100 85.890 ;
        RECT 35.430 85.860 35.890 85.890 ;
        RECT 36.220 85.860 36.680 85.890 ;
        RECT 37.010 85.860 37.470 85.890 ;
        RECT 37.800 85.860 38.260 85.890 ;
        RECT 38.590 85.860 39.050 85.890 ;
        RECT 39.380 85.860 39.840 85.890 ;
        RECT 40.170 85.860 40.630 85.890 ;
        RECT 40.960 85.860 41.420 85.890 ;
        RECT 41.750 85.860 42.210 85.890 ;
        RECT 42.540 85.860 43.000 85.890 ;
        RECT 43.330 85.860 43.790 85.890 ;
        RECT 44.120 85.860 44.580 85.890 ;
        RECT 44.910 85.860 45.370 85.890 ;
        RECT 45.700 85.860 46.160 85.890 ;
        RECT 46.490 85.860 46.950 85.890 ;
        RECT 47.280 85.860 47.740 85.890 ;
        RECT 48.070 85.860 48.530 85.890 ;
        RECT 48.860 85.860 49.320 85.890 ;
        RECT 49.650 85.860 50.110 85.890 ;
        RECT 50.440 85.860 50.900 85.890 ;
        RECT 51.230 85.860 51.690 85.890 ;
        RECT 52.020 85.860 52.480 85.890 ;
        RECT 52.810 85.860 53.270 85.890 ;
        RECT 53.600 85.860 54.060 85.890 ;
        RECT 54.390 85.860 54.850 85.890 ;
        RECT 55.180 85.860 55.640 85.890 ;
        RECT 55.970 85.860 56.430 85.890 ;
        RECT 56.760 85.860 57.220 85.890 ;
        RECT 57.550 85.860 58.010 85.890 ;
        RECT 58.340 85.860 58.800 85.890 ;
        RECT 59.130 85.860 59.590 85.890 ;
        RECT 59.920 85.860 60.380 85.890 ;
        RECT 60.710 85.860 61.170 85.890 ;
        RECT 79.000 85.860 79.460 85.890 ;
        RECT 79.790 85.860 80.250 85.890 ;
        RECT 80.580 85.860 81.040 85.890 ;
        RECT 81.370 85.860 81.830 85.890 ;
        RECT 82.160 85.860 82.620 85.890 ;
        RECT 82.950 85.860 83.410 85.890 ;
        RECT 83.740 85.860 84.200 85.890 ;
        RECT 84.530 85.860 84.990 85.890 ;
        RECT 85.320 85.860 85.780 85.890 ;
        RECT 86.110 85.860 86.570 85.890 ;
        RECT 86.900 85.860 87.360 85.890 ;
        RECT 87.690 85.860 88.150 85.890 ;
        RECT 89.390 85.860 89.740 85.950 ;
        RECT 14.685 85.690 61.190 85.860 ;
        RECT 78.980 85.690 89.740 85.860 ;
        RECT 15.000 85.660 15.460 85.690 ;
        RECT 15.790 85.660 16.250 85.690 ;
        RECT 16.580 85.660 17.040 85.690 ;
        RECT 17.370 85.660 17.830 85.690 ;
        RECT 18.160 85.660 18.620 85.690 ;
        RECT 22.000 85.660 22.460 85.690 ;
        RECT 22.685 85.660 23.250 85.690 ;
        RECT 23.580 85.660 24.040 85.690 ;
        RECT 24.370 85.660 24.830 85.690 ;
        RECT 25.160 85.660 25.620 85.690 ;
        RECT 25.950 85.660 26.410 85.690 ;
        RECT 26.740 85.660 27.200 85.690 ;
        RECT 27.530 85.660 27.990 85.690 ;
        RECT 28.320 85.660 28.780 85.690 ;
        RECT 29.110 85.660 29.570 85.690 ;
        RECT 29.900 85.660 30.360 85.690 ;
        RECT 30.690 85.660 31.150 85.690 ;
        RECT 31.480 85.660 31.940 85.690 ;
        RECT 32.270 85.660 32.730 85.690 ;
        RECT 33.060 85.660 33.520 85.690 ;
        RECT 33.850 85.660 34.310 85.690 ;
        RECT 34.640 85.660 35.100 85.690 ;
        RECT 35.430 85.660 35.890 85.690 ;
        RECT 36.220 85.660 36.680 85.690 ;
        RECT 37.010 85.660 37.470 85.690 ;
        RECT 37.800 85.660 38.260 85.690 ;
        RECT 38.590 85.660 39.050 85.690 ;
        RECT 39.380 85.660 39.840 85.690 ;
        RECT 40.170 85.660 40.630 85.690 ;
        RECT 40.960 85.660 41.420 85.690 ;
        RECT 41.750 85.660 42.210 85.690 ;
        RECT 42.540 85.660 43.000 85.690 ;
        RECT 43.330 85.660 43.790 85.690 ;
        RECT 44.120 85.660 44.580 85.690 ;
        RECT 44.910 85.660 45.370 85.690 ;
        RECT 45.700 85.660 46.160 85.690 ;
        RECT 46.490 85.660 46.950 85.690 ;
        RECT 47.280 85.660 47.740 85.690 ;
        RECT 48.070 85.660 48.530 85.690 ;
        RECT 48.860 85.660 49.320 85.690 ;
        RECT 49.650 85.660 50.110 85.690 ;
        RECT 50.440 85.660 50.900 85.690 ;
        RECT 51.230 85.660 51.690 85.690 ;
        RECT 52.020 85.660 52.480 85.690 ;
        RECT 52.810 85.660 53.270 85.690 ;
        RECT 53.600 85.660 54.060 85.690 ;
        RECT 54.390 85.660 54.850 85.690 ;
        RECT 55.180 85.660 55.640 85.690 ;
        RECT 55.970 85.660 56.430 85.690 ;
        RECT 56.760 85.660 57.220 85.690 ;
        RECT 57.550 85.660 58.010 85.690 ;
        RECT 58.340 85.660 58.800 85.690 ;
        RECT 59.130 85.660 59.590 85.690 ;
        RECT 59.920 85.660 60.380 85.690 ;
        RECT 60.710 85.660 61.170 85.690 ;
        RECT 79.000 85.660 79.460 85.690 ;
        RECT 79.790 85.660 80.250 85.690 ;
        RECT 80.580 85.660 81.040 85.690 ;
        RECT 81.370 85.660 81.830 85.690 ;
        RECT 82.160 85.660 82.620 85.690 ;
        RECT 82.950 85.660 83.410 85.690 ;
        RECT 83.740 85.660 84.200 85.690 ;
        RECT 84.530 85.660 84.990 85.690 ;
        RECT 85.320 85.660 85.780 85.690 ;
        RECT 86.110 85.660 86.570 85.690 ;
        RECT 86.900 85.660 87.360 85.690 ;
        RECT 87.690 85.660 88.150 85.690 ;
        RECT 22.685 85.270 22.985 85.660 ;
        RECT 89.390 85.600 89.740 85.690 ;
        RECT 22.650 84.900 23.020 85.270 ;
        RECT 15.320 76.655 15.680 77.015 ;
        RECT 18.820 76.655 19.180 77.015 ;
        RECT 23.920 76.655 24.280 77.015 ;
        RECT 35.820 76.655 36.180 77.015 ;
        RECT 58.320 76.745 58.680 77.105 ;
        RECT 83.170 76.655 83.530 77.015 ;
        RECT 130.120 76.655 130.480 77.015 ;
        RECT 137.420 76.655 137.780 77.015 ;
        RECT 141.420 76.655 141.780 77.015 ;
        RECT 51.000 76.500 51.460 76.530 ;
        RECT 51.790 76.500 52.250 76.530 ;
        RECT 52.580 76.500 53.040 76.530 ;
        RECT 53.370 76.500 53.830 76.530 ;
        RECT 54.160 76.500 54.620 76.530 ;
        RECT 54.950 76.500 55.410 76.530 ;
        RECT 55.740 76.500 56.200 76.530 ;
        RECT 56.530 76.500 56.990 76.530 ;
        RECT 57.320 76.500 57.780 76.530 ;
        RECT 58.110 76.500 58.570 76.530 ;
        RECT 15.000 76.210 15.960 76.440 ;
        RECT 19.000 76.210 19.960 76.440 ;
        RECT 23.000 76.410 23.960 76.440 ;
        RECT 24.290 76.410 25.250 76.440 ;
        RECT 29.000 76.410 29.460 76.440 ;
        RECT 29.790 76.410 30.250 76.440 ;
        RECT 30.580 76.410 31.040 76.440 ;
        RECT 31.370 76.410 31.830 76.440 ;
        RECT 32.160 76.410 32.620 76.440 ;
        RECT 32.950 76.410 33.410 76.440 ;
        RECT 33.740 76.410 34.200 76.440 ;
        RECT 34.530 76.410 34.990 76.440 ;
        RECT 35.320 76.410 35.780 76.440 ;
        RECT 36.110 76.410 36.570 76.440 ;
        RECT 36.900 76.410 37.360 76.440 ;
        RECT 37.690 76.410 38.150 76.440 ;
        RECT 38.480 76.410 38.940 76.440 ;
        RECT 39.270 76.410 39.730 76.440 ;
        RECT 40.060 76.410 40.520 76.440 ;
        RECT 40.850 76.410 41.310 76.440 ;
        RECT 41.640 76.410 42.100 76.440 ;
        RECT 42.430 76.410 42.890 76.440 ;
        RECT 43.220 76.410 43.680 76.440 ;
        RECT 44.010 76.410 44.470 76.440 ;
        RECT 22.980 76.240 25.270 76.410 ;
        RECT 28.980 76.240 44.490 76.410 ;
        RECT 50.980 76.330 58.590 76.500 ;
        RECT 79.000 76.410 79.960 76.440 ;
        RECT 80.290 76.410 81.250 76.440 ;
        RECT 81.580 76.410 82.540 76.440 ;
        RECT 82.870 76.410 83.830 76.440 ;
        RECT 84.160 76.410 85.120 76.440 ;
        RECT 85.450 76.410 86.410 76.440 ;
        RECT 51.000 76.300 51.460 76.330 ;
        RECT 51.790 76.300 52.250 76.330 ;
        RECT 52.580 76.300 53.040 76.330 ;
        RECT 53.370 76.300 53.830 76.330 ;
        RECT 54.160 76.300 54.620 76.330 ;
        RECT 54.950 76.300 55.410 76.330 ;
        RECT 55.740 76.300 56.200 76.330 ;
        RECT 56.530 76.300 56.990 76.330 ;
        RECT 57.320 76.300 57.780 76.330 ;
        RECT 58.110 76.300 58.570 76.330 ;
        RECT 78.980 76.240 86.430 76.410 ;
        RECT 23.000 76.210 23.960 76.240 ;
        RECT 24.290 76.210 25.250 76.240 ;
        RECT 29.000 76.210 29.460 76.240 ;
        RECT 29.790 76.210 30.250 76.240 ;
        RECT 30.580 76.210 31.040 76.240 ;
        RECT 31.370 76.210 31.830 76.240 ;
        RECT 32.160 76.210 32.620 76.240 ;
        RECT 32.950 76.210 33.410 76.240 ;
        RECT 33.740 76.210 34.200 76.240 ;
        RECT 34.530 76.210 34.990 76.240 ;
        RECT 35.320 76.210 35.780 76.240 ;
        RECT 36.110 76.210 36.570 76.240 ;
        RECT 36.900 76.210 37.360 76.240 ;
        RECT 37.690 76.210 38.150 76.240 ;
        RECT 38.480 76.210 38.940 76.240 ;
        RECT 39.270 76.210 39.730 76.240 ;
        RECT 40.060 76.210 40.520 76.240 ;
        RECT 40.850 76.210 41.310 76.240 ;
        RECT 41.640 76.210 42.100 76.240 ;
        RECT 42.430 76.210 42.890 76.240 ;
        RECT 43.220 76.210 43.680 76.240 ;
        RECT 44.010 76.210 44.470 76.240 ;
        RECT 79.000 76.210 79.960 76.240 ;
        RECT 80.290 76.210 81.250 76.240 ;
        RECT 81.580 76.210 82.540 76.240 ;
        RECT 82.870 76.210 83.830 76.240 ;
        RECT 84.160 76.210 85.120 76.240 ;
        RECT 85.450 76.210 86.410 76.240 ;
        RECT 130.000 76.210 130.960 76.440 ;
        RECT 137.000 76.410 137.460 76.440 ;
        RECT 137.790 76.410 138.250 76.440 ;
        RECT 141.000 76.410 141.460 76.440 ;
        RECT 141.790 76.410 142.250 76.440 ;
        RECT 136.980 76.240 138.270 76.410 ;
        RECT 140.980 76.240 142.270 76.410 ;
        RECT 137.000 76.210 137.460 76.240 ;
        RECT 137.790 76.210 138.250 76.240 ;
        RECT 141.000 76.210 141.460 76.240 ;
        RECT 141.790 76.210 142.250 76.240 ;
        RECT 14.720 72.500 14.950 76.050 ;
        RECT 14.720 70.890 15.200 72.500 ;
        RECT 16.010 71.650 16.240 76.050 ;
        RECT 18.720 72.650 18.950 76.050 ;
        RECT 18.675 72.300 18.995 72.650 ;
        RECT 15.965 71.300 16.285 71.650 ;
        RECT 16.010 71.050 16.240 71.300 ;
        RECT 18.720 71.050 18.950 72.300 ;
        RECT 20.010 71.650 20.240 76.050 ;
        RECT 22.720 75.760 22.950 76.050 ;
        RECT 22.675 75.440 22.995 75.760 ;
        RECT 19.965 71.300 20.285 71.650 ;
        RECT 20.010 71.050 20.240 71.300 ;
        RECT 22.720 71.050 22.950 75.440 ;
        RECT 24.010 71.650 24.240 76.050 ;
        RECT 25.300 75.760 25.530 76.050 ;
        RECT 28.720 75.760 28.950 76.050 ;
        RECT 25.255 75.440 25.575 75.760 ;
        RECT 28.675 75.440 28.995 75.760 ;
        RECT 23.965 71.300 24.285 71.650 ;
        RECT 24.010 71.050 24.240 71.300 ;
        RECT 25.300 71.050 25.530 75.440 ;
        RECT 28.720 71.050 28.950 75.440 ;
        RECT 29.510 71.650 29.740 76.050 ;
        RECT 30.300 75.760 30.530 76.050 ;
        RECT 30.255 75.440 30.575 75.760 ;
        RECT 29.465 71.300 29.785 71.650 ;
        RECT 29.510 71.050 29.740 71.300 ;
        RECT 30.300 71.050 30.530 75.440 ;
        RECT 31.090 71.650 31.320 76.050 ;
        RECT 31.880 75.760 32.110 76.050 ;
        RECT 31.835 75.440 32.155 75.760 ;
        RECT 31.045 71.300 31.365 71.650 ;
        RECT 31.090 71.050 31.320 71.300 ;
        RECT 31.880 71.050 32.110 75.440 ;
        RECT 32.670 71.650 32.900 76.050 ;
        RECT 33.460 75.760 33.690 76.050 ;
        RECT 33.415 75.440 33.735 75.760 ;
        RECT 32.625 71.300 32.945 71.650 ;
        RECT 32.670 71.050 32.900 71.300 ;
        RECT 33.460 71.050 33.690 75.440 ;
        RECT 34.250 71.650 34.480 76.050 ;
        RECT 35.040 75.760 35.270 76.050 ;
        RECT 34.995 75.440 35.315 75.760 ;
        RECT 34.205 71.300 34.525 71.650 ;
        RECT 34.250 71.050 34.480 71.300 ;
        RECT 35.040 71.050 35.270 75.440 ;
        RECT 35.830 71.650 36.060 76.050 ;
        RECT 36.620 75.760 36.850 76.050 ;
        RECT 36.575 75.440 36.895 75.760 ;
        RECT 35.785 71.300 36.105 71.650 ;
        RECT 35.830 71.050 36.060 71.300 ;
        RECT 36.620 71.050 36.850 75.440 ;
        RECT 37.410 71.650 37.640 76.050 ;
        RECT 38.200 75.760 38.430 76.050 ;
        RECT 38.155 75.440 38.475 75.760 ;
        RECT 37.365 71.300 37.685 71.650 ;
        RECT 37.410 71.050 37.640 71.300 ;
        RECT 38.200 71.050 38.430 75.440 ;
        RECT 38.990 71.650 39.220 76.050 ;
        RECT 39.780 75.760 40.010 76.050 ;
        RECT 39.735 75.440 40.055 75.760 ;
        RECT 38.945 71.300 39.265 71.650 ;
        RECT 38.990 71.050 39.220 71.300 ;
        RECT 39.780 71.050 40.010 75.440 ;
        RECT 40.570 71.650 40.800 76.050 ;
        RECT 41.360 75.760 41.590 76.050 ;
        RECT 41.315 75.440 41.635 75.760 ;
        RECT 40.525 71.300 40.845 71.650 ;
        RECT 40.570 71.050 40.800 71.300 ;
        RECT 41.360 71.050 41.590 75.440 ;
        RECT 42.150 71.650 42.380 76.050 ;
        RECT 42.940 75.760 43.170 76.050 ;
        RECT 42.895 75.440 43.215 75.760 ;
        RECT 42.105 71.300 42.425 71.650 ;
        RECT 42.150 71.050 42.380 71.300 ;
        RECT 42.940 71.050 43.170 75.440 ;
        RECT 43.730 71.650 43.960 76.050 ;
        RECT 44.520 75.760 44.750 76.050 ;
        RECT 44.475 75.440 44.795 75.760 ;
        RECT 43.685 71.300 44.005 71.650 ;
        RECT 43.730 71.050 43.960 71.300 ;
        RECT 44.520 71.050 44.750 75.440 ;
        RECT 50.720 72.650 50.950 76.095 ;
        RECT 51.510 75.760 51.740 76.095 ;
        RECT 51.465 75.440 51.785 75.760 ;
        RECT 50.675 72.300 50.995 72.650 ;
        RECT 50.720 71.095 50.950 72.300 ;
        RECT 51.510 71.095 51.740 75.440 ;
        RECT 52.300 72.650 52.530 76.095 ;
        RECT 53.090 75.760 53.320 76.095 ;
        RECT 53.045 75.440 53.365 75.760 ;
        RECT 52.255 72.300 52.575 72.650 ;
        RECT 52.300 71.095 52.530 72.300 ;
        RECT 53.090 71.095 53.320 75.440 ;
        RECT 53.880 72.650 54.110 76.095 ;
        RECT 54.670 75.760 54.900 76.095 ;
        RECT 54.625 75.440 54.945 75.760 ;
        RECT 53.835 72.300 54.155 72.650 ;
        RECT 53.880 71.095 54.110 72.300 ;
        RECT 54.670 71.095 54.900 75.440 ;
        RECT 55.460 72.650 55.690 76.095 ;
        RECT 56.250 75.760 56.480 76.095 ;
        RECT 56.205 75.440 56.525 75.760 ;
        RECT 55.415 72.300 55.735 72.650 ;
        RECT 55.460 71.095 55.690 72.300 ;
        RECT 56.250 71.095 56.480 75.440 ;
        RECT 57.040 72.650 57.270 76.095 ;
        RECT 57.830 75.760 58.060 76.095 ;
        RECT 57.785 75.440 58.105 75.760 ;
        RECT 56.995 72.300 57.315 72.650 ;
        RECT 57.040 71.095 57.270 72.300 ;
        RECT 57.830 71.095 58.060 75.440 ;
        RECT 58.620 72.650 58.850 76.095 ;
        RECT 58.575 72.300 58.895 72.650 ;
        RECT 58.620 71.095 58.850 72.300 ;
        RECT 14.720 70.860 15.960 70.890 ;
        RECT 19.000 70.860 19.960 70.890 ;
        RECT 23.000 70.860 23.960 70.890 ;
        RECT 24.290 70.860 25.250 70.890 ;
        RECT 27.160 70.860 27.540 71.035 ;
        RECT 29.000 70.860 29.460 70.890 ;
        RECT 29.790 70.860 30.250 70.890 ;
        RECT 30.580 70.860 31.040 70.890 ;
        RECT 31.370 70.860 31.830 70.890 ;
        RECT 32.160 70.860 32.620 70.890 ;
        RECT 32.950 70.860 33.410 70.890 ;
        RECT 33.740 70.860 34.200 70.890 ;
        RECT 34.530 70.860 34.990 70.890 ;
        RECT 35.320 70.860 35.780 70.890 ;
        RECT 36.110 70.860 36.570 70.890 ;
        RECT 36.900 70.860 37.360 70.890 ;
        RECT 37.690 70.860 38.150 70.890 ;
        RECT 38.480 70.860 38.940 70.890 ;
        RECT 39.270 70.860 39.730 70.890 ;
        RECT 40.060 70.860 40.520 70.890 ;
        RECT 40.850 70.860 41.310 70.890 ;
        RECT 41.640 70.860 42.100 70.890 ;
        RECT 42.430 70.860 42.890 70.890 ;
        RECT 43.220 70.860 43.680 70.890 ;
        RECT 44.010 70.860 44.470 70.890 ;
        RECT 51.000 70.860 51.460 70.890 ;
        RECT 51.790 70.860 52.250 70.890 ;
        RECT 52.580 70.860 53.040 70.890 ;
        RECT 53.370 70.860 53.830 70.890 ;
        RECT 54.160 70.860 54.620 70.890 ;
        RECT 54.950 70.860 55.410 70.890 ;
        RECT 55.740 70.860 56.200 70.890 ;
        RECT 56.530 70.860 56.990 70.890 ;
        RECT 57.320 70.860 57.780 70.890 ;
        RECT 58.110 70.860 58.570 70.890 ;
        RECT 59.760 70.860 60.140 71.640 ;
        RECT 78.720 71.610 78.950 76.050 ;
        RECT 80.010 75.760 80.240 76.050 ;
        RECT 79.965 75.440 80.285 75.760 ;
        RECT 78.675 71.290 78.995 71.610 ;
        RECT 78.720 71.050 78.950 71.290 ;
        RECT 80.010 71.050 80.240 75.440 ;
        RECT 81.300 71.610 81.530 76.050 ;
        RECT 82.590 75.760 82.820 76.050 ;
        RECT 82.545 75.440 82.865 75.760 ;
        RECT 81.255 71.290 81.575 71.610 ;
        RECT 81.300 71.050 81.530 71.290 ;
        RECT 82.590 71.050 82.820 75.440 ;
        RECT 83.880 71.610 84.110 76.050 ;
        RECT 85.170 75.760 85.400 76.050 ;
        RECT 85.125 75.440 85.445 75.760 ;
        RECT 83.835 71.290 84.155 71.610 ;
        RECT 83.880 71.050 84.110 71.290 ;
        RECT 85.170 71.050 85.400 75.440 ;
        RECT 86.460 71.610 86.690 76.050 ;
        RECT 129.720 71.650 129.950 76.050 ;
        RECT 131.010 75.775 131.240 76.050 ;
        RECT 136.720 75.790 136.950 76.050 ;
        RECT 130.965 75.425 131.285 75.775 ;
        RECT 86.415 71.290 86.735 71.610 ;
        RECT 129.675 71.300 129.995 71.650 ;
        RECT 86.460 71.050 86.690 71.290 ;
        RECT 129.720 71.050 129.950 71.300 ;
        RECT 131.010 71.050 131.240 75.425 ;
        RECT 136.645 75.410 137.025 75.790 ;
        RECT 136.720 71.050 136.950 75.410 ;
        RECT 137.510 71.650 137.740 76.050 ;
        RECT 138.300 75.790 138.530 76.050 ;
        RECT 138.225 75.410 138.605 75.790 ;
        RECT 140.720 75.760 140.950 76.050 ;
        RECT 140.675 75.440 140.995 75.760 ;
        RECT 137.465 71.300 137.785 71.650 ;
        RECT 137.510 71.050 137.740 71.300 ;
        RECT 138.300 71.050 138.530 75.410 ;
        RECT 140.720 71.050 140.950 75.440 ;
        RECT 141.510 71.650 141.740 76.050 ;
        RECT 142.300 75.760 142.530 76.050 ;
        RECT 142.265 75.440 142.565 75.760 ;
        RECT 141.465 71.300 141.785 71.650 ;
        RECT 141.510 71.050 141.740 71.300 ;
        RECT 142.300 71.050 142.530 75.440 ;
        RECT 79.000 70.860 79.960 70.890 ;
        RECT 80.290 70.860 81.250 70.890 ;
        RECT 81.580 70.860 82.540 70.890 ;
        RECT 82.870 70.860 83.830 70.890 ;
        RECT 84.160 70.860 85.120 70.890 ;
        RECT 85.450 70.860 86.410 70.890 ;
        RECT 14.720 70.690 25.270 70.860 ;
        RECT 27.000 70.690 44.490 70.860 ;
        RECT 50.980 70.690 60.140 70.860 ;
        RECT 78.980 70.690 86.430 70.860 ;
        RECT 15.000 70.660 15.960 70.690 ;
        RECT 19.000 70.660 19.960 70.690 ;
        RECT 23.000 70.660 23.960 70.690 ;
        RECT 24.290 70.660 25.250 70.690 ;
        RECT 15.300 70.000 15.660 70.660 ;
        RECT 27.160 70.655 27.540 70.690 ;
        RECT 29.000 70.660 29.460 70.690 ;
        RECT 29.790 70.660 30.250 70.690 ;
        RECT 30.580 70.660 31.040 70.690 ;
        RECT 31.370 70.660 31.830 70.690 ;
        RECT 32.160 70.660 32.620 70.690 ;
        RECT 32.950 70.660 33.410 70.690 ;
        RECT 33.740 70.660 34.200 70.690 ;
        RECT 34.530 70.660 34.990 70.690 ;
        RECT 35.320 70.660 35.780 70.690 ;
        RECT 36.110 70.660 36.570 70.690 ;
        RECT 36.900 70.660 37.360 70.690 ;
        RECT 37.690 70.660 38.150 70.690 ;
        RECT 38.480 70.660 38.940 70.690 ;
        RECT 39.270 70.660 39.730 70.690 ;
        RECT 40.060 70.660 40.520 70.690 ;
        RECT 40.850 70.660 41.310 70.690 ;
        RECT 41.640 70.660 42.100 70.690 ;
        RECT 42.430 70.660 42.890 70.690 ;
        RECT 43.220 70.660 43.680 70.690 ;
        RECT 44.010 70.660 44.470 70.690 ;
        RECT 51.000 70.660 51.460 70.690 ;
        RECT 51.790 70.660 52.250 70.690 ;
        RECT 52.580 70.660 53.040 70.690 ;
        RECT 53.370 70.660 53.830 70.690 ;
        RECT 54.160 70.660 54.620 70.690 ;
        RECT 54.950 70.660 55.410 70.690 ;
        RECT 55.740 70.660 56.200 70.690 ;
        RECT 56.530 70.660 56.990 70.690 ;
        RECT 57.320 70.660 57.780 70.690 ;
        RECT 58.110 70.660 58.570 70.690 ;
        RECT 79.000 70.660 79.960 70.690 ;
        RECT 80.290 70.660 81.250 70.690 ;
        RECT 81.580 70.660 82.540 70.690 ;
        RECT 82.870 70.660 83.830 70.690 ;
        RECT 84.160 70.660 85.120 70.690 ;
        RECT 85.450 70.660 86.410 70.690 ;
        RECT 130.000 70.660 130.960 70.890 ;
        RECT 137.000 70.860 138.250 70.890 ;
        RECT 141.000 70.860 141.460 70.890 ;
        RECT 141.790 70.860 142.250 70.890 ;
        RECT 136.980 70.690 138.270 70.860 ;
        RECT 140.980 70.690 142.270 70.860 ;
        RECT 137.000 70.660 138.250 70.690 ;
        RECT 141.000 70.660 141.460 70.690 ;
        RECT 141.790 70.660 142.270 70.690 ;
        RECT 80.590 70.000 80.950 70.660 ;
        RECT 130.300 70.000 130.660 70.660 ;
        RECT 137.420 70.540 137.790 70.660 ;
        RECT 141.980 69.000 142.270 70.660 ;
        RECT 153.050 69.000 153.300 70.135 ;
        RECT 156.050 69.000 156.300 70.130 ;
        RECT 141.980 68.500 156.300 69.000 ;
        RECT 153.050 68.030 153.300 68.500 ;
        RECT 156.050 68.025 156.300 68.500 ;
        RECT 14.140 57.260 14.460 57.295 ;
        RECT 14.140 57.015 53.140 57.260 ;
        RECT 14.140 56.975 14.460 57.015 ;
        RECT 14.720 53.320 14.950 56.815 ;
        RECT 15.200 55.620 15.430 56.815 ;
        RECT 15.155 55.300 15.475 55.620 ;
        RECT 14.675 53.000 14.995 53.320 ;
        RECT 14.720 51.815 14.950 53.000 ;
        RECT 15.200 51.815 15.430 55.300 ;
        RECT 15.680 53.320 15.910 56.815 ;
        RECT 16.160 55.620 16.390 56.815 ;
        RECT 16.115 55.300 16.435 55.620 ;
        RECT 15.635 53.000 15.955 53.320 ;
        RECT 15.680 51.815 15.910 53.000 ;
        RECT 16.160 51.815 16.390 55.300 ;
        RECT 16.640 53.320 16.870 56.815 ;
        RECT 17.120 55.620 17.350 56.815 ;
        RECT 17.075 55.300 17.395 55.620 ;
        RECT 16.595 53.000 16.915 53.320 ;
        RECT 16.640 51.815 16.870 53.000 ;
        RECT 17.120 51.815 17.350 55.300 ;
        RECT 17.600 53.320 17.830 56.815 ;
        RECT 18.080 55.620 18.310 56.815 ;
        RECT 18.035 55.300 18.355 55.620 ;
        RECT 17.555 53.000 17.875 53.320 ;
        RECT 17.600 51.815 17.830 53.000 ;
        RECT 18.080 51.815 18.310 55.300 ;
        RECT 18.560 53.320 18.790 56.815 ;
        RECT 19.040 55.620 19.270 56.815 ;
        RECT 18.995 55.300 19.315 55.620 ;
        RECT 18.515 53.000 18.835 53.320 ;
        RECT 18.560 51.815 18.790 53.000 ;
        RECT 19.040 51.815 19.270 55.300 ;
        RECT 19.520 53.320 19.750 56.815 ;
        RECT 20.000 55.620 20.230 56.815 ;
        RECT 19.955 55.300 20.275 55.620 ;
        RECT 19.475 53.000 19.795 53.320 ;
        RECT 19.520 51.815 19.750 53.000 ;
        RECT 20.000 51.815 20.230 55.300 ;
        RECT 20.480 53.320 20.710 56.815 ;
        RECT 20.960 55.620 21.190 56.815 ;
        RECT 20.915 55.300 21.235 55.620 ;
        RECT 20.435 53.000 20.755 53.320 ;
        RECT 20.480 51.815 20.710 53.000 ;
        RECT 20.960 51.815 21.190 55.300 ;
        RECT 21.440 53.320 21.670 56.815 ;
        RECT 21.920 55.620 22.150 56.815 ;
        RECT 21.875 55.300 22.195 55.620 ;
        RECT 21.395 53.000 21.715 53.320 ;
        RECT 21.440 51.815 21.670 53.000 ;
        RECT 21.920 51.815 22.150 55.300 ;
        RECT 22.400 53.320 22.630 56.815 ;
        RECT 22.880 55.620 23.110 56.815 ;
        RECT 22.835 55.300 23.155 55.620 ;
        RECT 22.355 53.000 22.675 53.320 ;
        RECT 22.400 51.815 22.630 53.000 ;
        RECT 22.880 51.815 23.110 55.300 ;
        RECT 23.360 53.320 23.590 56.815 ;
        RECT 23.840 55.620 24.070 56.815 ;
        RECT 23.795 55.300 24.115 55.620 ;
        RECT 23.315 53.000 23.635 53.320 ;
        RECT 23.360 51.815 23.590 53.000 ;
        RECT 23.840 51.815 24.070 55.300 ;
        RECT 24.320 53.320 24.550 56.815 ;
        RECT 24.800 55.620 25.030 56.815 ;
        RECT 24.755 55.300 25.075 55.620 ;
        RECT 24.275 53.000 24.595 53.320 ;
        RECT 24.320 51.815 24.550 53.000 ;
        RECT 24.800 51.815 25.030 55.300 ;
        RECT 25.280 53.320 25.510 56.815 ;
        RECT 25.760 55.620 25.990 56.815 ;
        RECT 25.715 55.300 26.035 55.620 ;
        RECT 25.235 53.000 25.555 53.320 ;
        RECT 25.280 51.815 25.510 53.000 ;
        RECT 25.760 51.815 25.990 55.300 ;
        RECT 26.240 53.320 26.470 56.815 ;
        RECT 26.720 55.620 26.950 56.815 ;
        RECT 26.675 55.300 26.995 55.620 ;
        RECT 26.195 53.000 26.515 53.320 ;
        RECT 26.240 51.815 26.470 53.000 ;
        RECT 26.720 51.815 26.950 55.300 ;
        RECT 27.200 53.320 27.430 56.815 ;
        RECT 27.680 55.620 27.910 56.815 ;
        RECT 27.635 55.300 27.955 55.620 ;
        RECT 27.155 53.000 27.475 53.320 ;
        RECT 27.200 51.815 27.430 53.000 ;
        RECT 27.680 51.815 27.910 55.300 ;
        RECT 28.160 53.320 28.390 56.815 ;
        RECT 28.640 55.620 28.870 56.815 ;
        RECT 28.595 55.300 28.915 55.620 ;
        RECT 28.115 53.000 28.435 53.320 ;
        RECT 28.160 51.815 28.390 53.000 ;
        RECT 28.640 51.815 28.870 55.300 ;
        RECT 29.120 53.320 29.350 56.815 ;
        RECT 29.600 55.620 29.830 56.815 ;
        RECT 29.555 55.300 29.875 55.620 ;
        RECT 29.075 53.000 29.395 53.320 ;
        RECT 29.120 51.815 29.350 53.000 ;
        RECT 29.600 51.815 29.830 55.300 ;
        RECT 30.080 53.320 30.310 56.815 ;
        RECT 30.560 55.620 30.790 56.815 ;
        RECT 30.515 55.300 30.835 55.620 ;
        RECT 30.035 53.000 30.355 53.320 ;
        RECT 30.080 51.815 30.310 53.000 ;
        RECT 30.560 51.815 30.790 55.300 ;
        RECT 31.040 53.320 31.270 56.815 ;
        RECT 31.520 55.620 31.750 56.815 ;
        RECT 31.475 55.300 31.795 55.620 ;
        RECT 30.995 53.000 31.315 53.320 ;
        RECT 31.040 51.815 31.270 53.000 ;
        RECT 31.520 51.815 31.750 55.300 ;
        RECT 32.000 53.320 32.230 56.815 ;
        RECT 32.480 55.620 32.710 56.815 ;
        RECT 32.435 55.300 32.755 55.620 ;
        RECT 31.955 53.000 32.275 53.320 ;
        RECT 32.000 51.815 32.230 53.000 ;
        RECT 32.480 51.815 32.710 55.300 ;
        RECT 32.960 53.320 33.190 56.815 ;
        RECT 33.440 55.620 33.670 56.815 ;
        RECT 33.395 55.300 33.715 55.620 ;
        RECT 32.915 53.000 33.235 53.320 ;
        RECT 32.960 51.815 33.190 53.000 ;
        RECT 33.440 51.815 33.670 55.300 ;
        RECT 33.920 53.320 34.150 56.815 ;
        RECT 34.400 55.620 34.630 56.815 ;
        RECT 34.355 55.300 34.675 55.620 ;
        RECT 33.875 53.000 34.195 53.320 ;
        RECT 33.920 51.815 34.150 53.000 ;
        RECT 34.400 51.815 34.630 55.300 ;
        RECT 34.880 53.320 35.110 56.815 ;
        RECT 35.360 55.620 35.590 56.815 ;
        RECT 35.315 55.300 35.635 55.620 ;
        RECT 34.835 53.000 35.155 53.320 ;
        RECT 34.880 51.815 35.110 53.000 ;
        RECT 35.360 51.815 35.590 55.300 ;
        RECT 35.840 53.320 36.070 56.815 ;
        RECT 36.320 55.620 36.550 56.815 ;
        RECT 36.275 55.300 36.595 55.620 ;
        RECT 35.795 53.000 36.115 53.320 ;
        RECT 35.840 51.815 36.070 53.000 ;
        RECT 36.320 51.815 36.550 55.300 ;
        RECT 36.800 53.320 37.030 56.815 ;
        RECT 37.280 55.620 37.510 56.815 ;
        RECT 37.235 55.300 37.555 55.620 ;
        RECT 36.755 53.000 37.075 53.320 ;
        RECT 36.800 51.815 37.030 53.000 ;
        RECT 37.280 51.815 37.510 55.300 ;
        RECT 37.760 53.320 37.990 56.815 ;
        RECT 38.240 55.620 38.470 56.815 ;
        RECT 38.195 55.300 38.515 55.620 ;
        RECT 37.715 53.000 38.035 53.320 ;
        RECT 37.760 51.815 37.990 53.000 ;
        RECT 38.240 51.815 38.470 55.300 ;
        RECT 38.720 53.320 38.950 56.815 ;
        RECT 39.200 55.620 39.430 56.815 ;
        RECT 39.155 55.300 39.475 55.620 ;
        RECT 38.675 53.000 38.995 53.320 ;
        RECT 38.720 51.815 38.950 53.000 ;
        RECT 39.200 51.815 39.430 55.300 ;
        RECT 39.680 53.320 39.910 56.815 ;
        RECT 40.160 55.620 40.390 56.815 ;
        RECT 40.115 55.300 40.435 55.620 ;
        RECT 39.635 53.000 39.955 53.320 ;
        RECT 39.680 51.815 39.910 53.000 ;
        RECT 40.160 51.815 40.390 55.300 ;
        RECT 40.640 53.320 40.870 56.815 ;
        RECT 41.120 55.620 41.350 56.815 ;
        RECT 41.075 55.300 41.395 55.620 ;
        RECT 40.595 53.000 40.915 53.320 ;
        RECT 40.640 51.815 40.870 53.000 ;
        RECT 41.120 51.815 41.350 55.300 ;
        RECT 41.600 53.320 41.830 56.815 ;
        RECT 42.080 55.620 42.310 56.815 ;
        RECT 42.035 55.300 42.355 55.620 ;
        RECT 41.555 53.000 41.875 53.320 ;
        RECT 41.600 51.815 41.830 53.000 ;
        RECT 42.080 51.815 42.310 55.300 ;
        RECT 42.560 53.320 42.790 56.815 ;
        RECT 43.040 55.620 43.270 56.815 ;
        RECT 42.995 55.300 43.315 55.620 ;
        RECT 42.515 53.000 42.835 53.320 ;
        RECT 42.560 51.815 42.790 53.000 ;
        RECT 43.040 51.815 43.270 55.300 ;
        RECT 43.520 53.320 43.750 56.815 ;
        RECT 44.000 55.620 44.230 56.815 ;
        RECT 43.955 55.300 44.275 55.620 ;
        RECT 43.475 53.000 43.795 53.320 ;
        RECT 43.520 51.815 43.750 53.000 ;
        RECT 44.000 51.815 44.230 55.300 ;
        RECT 44.480 53.320 44.710 56.815 ;
        RECT 44.960 55.620 45.190 56.815 ;
        RECT 44.915 55.300 45.235 55.620 ;
        RECT 44.435 53.000 44.755 53.320 ;
        RECT 44.480 51.815 44.710 53.000 ;
        RECT 44.960 51.815 45.190 55.300 ;
        RECT 45.440 53.320 45.670 56.815 ;
        RECT 45.920 55.620 46.150 56.815 ;
        RECT 45.875 55.300 46.195 55.620 ;
        RECT 45.395 53.000 45.715 53.320 ;
        RECT 45.440 51.815 45.670 53.000 ;
        RECT 45.920 51.815 46.150 55.300 ;
        RECT 46.400 53.320 46.630 56.815 ;
        RECT 46.880 55.620 47.110 56.815 ;
        RECT 46.835 55.300 47.155 55.620 ;
        RECT 46.355 53.000 46.675 53.320 ;
        RECT 46.400 51.815 46.630 53.000 ;
        RECT 46.880 51.815 47.110 55.300 ;
        RECT 47.360 53.320 47.590 56.815 ;
        RECT 47.840 55.620 48.070 56.815 ;
        RECT 47.795 55.300 48.115 55.620 ;
        RECT 47.315 53.000 47.635 53.320 ;
        RECT 47.360 51.815 47.590 53.000 ;
        RECT 47.840 51.815 48.070 55.300 ;
        RECT 48.320 53.320 48.550 56.815 ;
        RECT 48.800 55.620 49.030 56.815 ;
        RECT 48.755 55.300 49.075 55.620 ;
        RECT 48.275 53.000 48.595 53.320 ;
        RECT 48.320 51.815 48.550 53.000 ;
        RECT 48.800 51.815 49.030 55.300 ;
        RECT 49.280 53.320 49.510 56.815 ;
        RECT 49.760 55.620 49.990 56.815 ;
        RECT 49.715 55.300 50.035 55.620 ;
        RECT 49.235 53.000 49.555 53.320 ;
        RECT 49.280 51.815 49.510 53.000 ;
        RECT 49.760 51.815 49.990 55.300 ;
        RECT 50.240 53.320 50.470 56.815 ;
        RECT 50.720 55.620 50.950 56.815 ;
        RECT 50.675 55.300 50.995 55.620 ;
        RECT 50.195 53.000 50.515 53.320 ;
        RECT 50.240 51.815 50.470 53.000 ;
        RECT 50.720 51.815 50.950 55.300 ;
        RECT 51.200 53.320 51.430 56.815 ;
        RECT 51.680 55.620 51.910 56.815 ;
        RECT 51.635 55.300 51.955 55.620 ;
        RECT 51.155 53.000 51.475 53.320 ;
        RECT 51.200 51.815 51.430 53.000 ;
        RECT 51.680 51.815 51.910 55.300 ;
        RECT 52.160 53.320 52.390 56.815 ;
        RECT 52.640 55.620 52.870 56.815 ;
        RECT 52.595 55.300 52.915 55.620 ;
        RECT 52.115 53.000 52.435 53.320 ;
        RECT 52.160 51.815 52.390 53.000 ;
        RECT 52.640 51.815 52.870 55.300 ;
        RECT 53.120 53.320 53.350 56.815 ;
        RECT 53.075 53.000 53.395 53.320 ;
        RECT 53.120 51.815 53.350 53.000 ;
        RECT 14.140 51.615 14.460 51.650 ;
        RECT 14.925 51.615 52.660 51.620 ;
        RECT 14.140 51.375 52.660 51.615 ;
        RECT 14.140 51.370 15.500 51.375 ;
        RECT 14.140 51.330 14.460 51.370 ;
        RECT 14.140 51.080 14.460 51.115 ;
        RECT 14.140 51.075 15.500 51.080 ;
        RECT 14.140 50.835 52.660 51.075 ;
        RECT 14.140 50.795 14.460 50.835 ;
        RECT 14.925 50.830 52.660 50.835 ;
        RECT 14.720 47.140 14.950 50.635 ;
        RECT 15.200 49.440 15.430 50.635 ;
        RECT 15.155 49.120 15.475 49.440 ;
        RECT 14.675 46.820 14.995 47.140 ;
        RECT 14.720 45.635 14.950 46.820 ;
        RECT 15.200 45.635 15.430 49.120 ;
        RECT 15.680 47.140 15.910 50.635 ;
        RECT 16.160 49.440 16.390 50.635 ;
        RECT 16.115 49.120 16.435 49.440 ;
        RECT 15.635 46.820 15.955 47.140 ;
        RECT 15.680 45.635 15.910 46.820 ;
        RECT 16.160 45.635 16.390 49.120 ;
        RECT 16.640 47.140 16.870 50.635 ;
        RECT 17.120 49.440 17.350 50.635 ;
        RECT 17.075 49.120 17.395 49.440 ;
        RECT 16.595 46.820 16.915 47.140 ;
        RECT 16.640 45.635 16.870 46.820 ;
        RECT 17.120 45.635 17.350 49.120 ;
        RECT 17.600 47.140 17.830 50.635 ;
        RECT 18.080 49.440 18.310 50.635 ;
        RECT 18.035 49.120 18.355 49.440 ;
        RECT 17.555 46.820 17.875 47.140 ;
        RECT 17.600 45.635 17.830 46.820 ;
        RECT 18.080 45.635 18.310 49.120 ;
        RECT 18.560 47.140 18.790 50.635 ;
        RECT 19.040 49.440 19.270 50.635 ;
        RECT 18.995 49.120 19.315 49.440 ;
        RECT 18.515 46.820 18.835 47.140 ;
        RECT 18.560 45.635 18.790 46.820 ;
        RECT 19.040 45.635 19.270 49.120 ;
        RECT 19.520 47.140 19.750 50.635 ;
        RECT 20.000 49.440 20.230 50.635 ;
        RECT 19.955 49.120 20.275 49.440 ;
        RECT 19.475 46.820 19.795 47.140 ;
        RECT 19.520 45.635 19.750 46.820 ;
        RECT 20.000 45.635 20.230 49.120 ;
        RECT 20.480 47.140 20.710 50.635 ;
        RECT 20.960 49.440 21.190 50.635 ;
        RECT 20.915 49.120 21.235 49.440 ;
        RECT 20.435 46.820 20.755 47.140 ;
        RECT 20.480 45.635 20.710 46.820 ;
        RECT 20.960 45.635 21.190 49.120 ;
        RECT 21.440 47.140 21.670 50.635 ;
        RECT 21.920 49.440 22.150 50.635 ;
        RECT 21.875 49.120 22.195 49.440 ;
        RECT 21.395 46.820 21.715 47.140 ;
        RECT 21.440 45.635 21.670 46.820 ;
        RECT 21.920 45.635 22.150 49.120 ;
        RECT 22.400 47.140 22.630 50.635 ;
        RECT 22.880 49.440 23.110 50.635 ;
        RECT 22.835 49.120 23.155 49.440 ;
        RECT 22.355 46.820 22.675 47.140 ;
        RECT 22.400 45.635 22.630 46.820 ;
        RECT 22.880 45.635 23.110 49.120 ;
        RECT 23.360 47.140 23.590 50.635 ;
        RECT 23.840 49.440 24.070 50.635 ;
        RECT 23.795 49.120 24.115 49.440 ;
        RECT 23.315 46.820 23.635 47.140 ;
        RECT 23.360 45.635 23.590 46.820 ;
        RECT 23.840 45.635 24.070 49.120 ;
        RECT 24.320 47.140 24.550 50.635 ;
        RECT 24.800 49.440 25.030 50.635 ;
        RECT 24.755 49.120 25.075 49.440 ;
        RECT 24.275 46.820 24.595 47.140 ;
        RECT 24.320 45.635 24.550 46.820 ;
        RECT 24.800 45.635 25.030 49.120 ;
        RECT 25.280 47.140 25.510 50.635 ;
        RECT 25.760 49.440 25.990 50.635 ;
        RECT 25.715 49.120 26.035 49.440 ;
        RECT 25.235 46.820 25.555 47.140 ;
        RECT 25.280 45.635 25.510 46.820 ;
        RECT 25.760 45.635 25.990 49.120 ;
        RECT 26.240 47.140 26.470 50.635 ;
        RECT 26.720 49.440 26.950 50.635 ;
        RECT 26.675 49.120 26.995 49.440 ;
        RECT 26.195 46.820 26.515 47.140 ;
        RECT 26.240 45.635 26.470 46.820 ;
        RECT 26.720 45.635 26.950 49.120 ;
        RECT 27.200 47.140 27.430 50.635 ;
        RECT 27.680 49.440 27.910 50.635 ;
        RECT 27.635 49.120 27.955 49.440 ;
        RECT 27.155 46.820 27.475 47.140 ;
        RECT 27.200 45.635 27.430 46.820 ;
        RECT 27.680 45.635 27.910 49.120 ;
        RECT 28.160 47.140 28.390 50.635 ;
        RECT 28.640 49.440 28.870 50.635 ;
        RECT 28.595 49.120 28.915 49.440 ;
        RECT 28.115 46.820 28.435 47.140 ;
        RECT 28.160 45.635 28.390 46.820 ;
        RECT 28.640 45.635 28.870 49.120 ;
        RECT 29.120 47.140 29.350 50.635 ;
        RECT 29.600 49.440 29.830 50.635 ;
        RECT 29.555 49.120 29.875 49.440 ;
        RECT 29.075 46.820 29.395 47.140 ;
        RECT 29.120 45.635 29.350 46.820 ;
        RECT 29.600 45.635 29.830 49.120 ;
        RECT 30.080 47.140 30.310 50.635 ;
        RECT 30.560 49.440 30.790 50.635 ;
        RECT 30.515 49.120 30.835 49.440 ;
        RECT 30.035 46.820 30.355 47.140 ;
        RECT 30.080 45.635 30.310 46.820 ;
        RECT 30.560 45.635 30.790 49.120 ;
        RECT 31.040 47.140 31.270 50.635 ;
        RECT 31.520 49.440 31.750 50.635 ;
        RECT 31.475 49.120 31.795 49.440 ;
        RECT 30.995 46.820 31.315 47.140 ;
        RECT 31.040 45.635 31.270 46.820 ;
        RECT 31.520 45.635 31.750 49.120 ;
        RECT 32.000 47.140 32.230 50.635 ;
        RECT 32.480 49.440 32.710 50.635 ;
        RECT 32.435 49.120 32.755 49.440 ;
        RECT 31.955 46.820 32.275 47.140 ;
        RECT 32.000 45.635 32.230 46.820 ;
        RECT 32.480 45.635 32.710 49.120 ;
        RECT 32.960 47.140 33.190 50.635 ;
        RECT 33.440 49.440 33.670 50.635 ;
        RECT 33.395 49.120 33.715 49.440 ;
        RECT 32.915 46.820 33.235 47.140 ;
        RECT 32.960 45.635 33.190 46.820 ;
        RECT 33.440 45.635 33.670 49.120 ;
        RECT 33.920 47.140 34.150 50.635 ;
        RECT 34.400 49.440 34.630 50.635 ;
        RECT 34.355 49.120 34.675 49.440 ;
        RECT 33.875 46.820 34.195 47.140 ;
        RECT 33.920 45.635 34.150 46.820 ;
        RECT 34.400 45.635 34.630 49.120 ;
        RECT 34.880 47.140 35.110 50.635 ;
        RECT 35.360 49.440 35.590 50.635 ;
        RECT 35.315 49.120 35.635 49.440 ;
        RECT 34.835 46.820 35.155 47.140 ;
        RECT 34.880 45.635 35.110 46.820 ;
        RECT 35.360 45.635 35.590 49.120 ;
        RECT 35.840 47.140 36.070 50.635 ;
        RECT 36.320 49.440 36.550 50.635 ;
        RECT 36.275 49.120 36.595 49.440 ;
        RECT 35.795 46.820 36.115 47.140 ;
        RECT 35.840 45.635 36.070 46.820 ;
        RECT 36.320 45.635 36.550 49.120 ;
        RECT 36.800 47.140 37.030 50.635 ;
        RECT 37.280 49.440 37.510 50.635 ;
        RECT 37.235 49.120 37.555 49.440 ;
        RECT 36.755 46.820 37.075 47.140 ;
        RECT 36.800 45.635 37.030 46.820 ;
        RECT 37.280 45.635 37.510 49.120 ;
        RECT 37.760 47.140 37.990 50.635 ;
        RECT 38.240 49.440 38.470 50.635 ;
        RECT 38.195 49.120 38.515 49.440 ;
        RECT 37.715 46.820 38.035 47.140 ;
        RECT 37.760 45.635 37.990 46.820 ;
        RECT 38.240 45.635 38.470 49.120 ;
        RECT 38.720 47.140 38.950 50.635 ;
        RECT 39.200 49.440 39.430 50.635 ;
        RECT 39.155 49.120 39.475 49.440 ;
        RECT 38.675 46.820 38.995 47.140 ;
        RECT 38.720 45.635 38.950 46.820 ;
        RECT 39.200 45.635 39.430 49.120 ;
        RECT 39.680 47.140 39.910 50.635 ;
        RECT 40.160 49.440 40.390 50.635 ;
        RECT 40.115 49.120 40.435 49.440 ;
        RECT 39.635 46.820 39.955 47.140 ;
        RECT 39.680 45.635 39.910 46.820 ;
        RECT 40.160 45.635 40.390 49.120 ;
        RECT 40.640 47.140 40.870 50.635 ;
        RECT 41.120 49.440 41.350 50.635 ;
        RECT 41.075 49.120 41.395 49.440 ;
        RECT 40.595 46.820 40.915 47.140 ;
        RECT 40.640 45.635 40.870 46.820 ;
        RECT 41.120 45.635 41.350 49.120 ;
        RECT 41.600 47.140 41.830 50.635 ;
        RECT 42.080 49.440 42.310 50.635 ;
        RECT 42.035 49.120 42.355 49.440 ;
        RECT 41.555 46.820 41.875 47.140 ;
        RECT 41.600 45.635 41.830 46.820 ;
        RECT 42.080 45.635 42.310 49.120 ;
        RECT 42.560 47.140 42.790 50.635 ;
        RECT 43.040 49.440 43.270 50.635 ;
        RECT 42.995 49.120 43.315 49.440 ;
        RECT 42.515 46.820 42.835 47.140 ;
        RECT 42.560 45.635 42.790 46.820 ;
        RECT 43.040 45.635 43.270 49.120 ;
        RECT 43.520 47.140 43.750 50.635 ;
        RECT 44.000 49.440 44.230 50.635 ;
        RECT 43.955 49.120 44.275 49.440 ;
        RECT 43.475 46.820 43.795 47.140 ;
        RECT 43.520 45.635 43.750 46.820 ;
        RECT 44.000 45.635 44.230 49.120 ;
        RECT 44.480 47.140 44.710 50.635 ;
        RECT 44.960 49.440 45.190 50.635 ;
        RECT 44.915 49.120 45.235 49.440 ;
        RECT 44.435 46.820 44.755 47.140 ;
        RECT 44.480 45.635 44.710 46.820 ;
        RECT 44.960 45.635 45.190 49.120 ;
        RECT 45.440 47.140 45.670 50.635 ;
        RECT 45.920 49.440 46.150 50.635 ;
        RECT 45.875 49.120 46.195 49.440 ;
        RECT 45.395 46.820 45.715 47.140 ;
        RECT 45.440 45.635 45.670 46.820 ;
        RECT 45.920 45.635 46.150 49.120 ;
        RECT 46.400 47.140 46.630 50.635 ;
        RECT 46.880 49.440 47.110 50.635 ;
        RECT 46.835 49.120 47.155 49.440 ;
        RECT 46.355 46.820 46.675 47.140 ;
        RECT 46.400 45.635 46.630 46.820 ;
        RECT 46.880 45.635 47.110 49.120 ;
        RECT 47.360 47.140 47.590 50.635 ;
        RECT 47.840 49.440 48.070 50.635 ;
        RECT 47.795 49.120 48.115 49.440 ;
        RECT 47.315 46.820 47.635 47.140 ;
        RECT 47.360 45.635 47.590 46.820 ;
        RECT 47.840 45.635 48.070 49.120 ;
        RECT 48.320 47.140 48.550 50.635 ;
        RECT 48.800 49.440 49.030 50.635 ;
        RECT 48.755 49.120 49.075 49.440 ;
        RECT 48.275 46.820 48.595 47.140 ;
        RECT 48.320 45.635 48.550 46.820 ;
        RECT 48.800 45.635 49.030 49.120 ;
        RECT 49.280 47.140 49.510 50.635 ;
        RECT 49.760 49.440 49.990 50.635 ;
        RECT 49.715 49.120 50.035 49.440 ;
        RECT 49.235 46.820 49.555 47.140 ;
        RECT 49.280 45.635 49.510 46.820 ;
        RECT 49.760 45.635 49.990 49.120 ;
        RECT 50.240 47.140 50.470 50.635 ;
        RECT 50.720 49.440 50.950 50.635 ;
        RECT 50.675 49.120 50.995 49.440 ;
        RECT 50.195 46.820 50.515 47.140 ;
        RECT 50.240 45.635 50.470 46.820 ;
        RECT 50.720 45.635 50.950 49.120 ;
        RECT 51.200 47.140 51.430 50.635 ;
        RECT 51.680 49.440 51.910 50.635 ;
        RECT 51.635 49.120 51.955 49.440 ;
        RECT 51.155 46.820 51.475 47.140 ;
        RECT 51.200 45.635 51.430 46.820 ;
        RECT 51.680 45.635 51.910 49.120 ;
        RECT 52.160 47.140 52.390 50.635 ;
        RECT 52.640 49.440 52.870 50.635 ;
        RECT 52.595 49.120 52.915 49.440 ;
        RECT 52.115 46.820 52.435 47.140 ;
        RECT 52.160 45.635 52.390 46.820 ;
        RECT 52.640 45.635 52.870 49.120 ;
        RECT 53.120 47.140 53.350 50.635 ;
        RECT 53.075 46.820 53.395 47.140 ;
        RECT 53.120 45.635 53.350 46.820 ;
        RECT 14.140 45.435 14.460 45.470 ;
        RECT 15.405 45.435 53.140 45.440 ;
        RECT 14.140 45.195 53.140 45.435 ;
        RECT 14.140 45.190 15.500 45.195 ;
        RECT 14.140 45.150 14.460 45.190 ;
        RECT 14.140 44.895 14.460 44.930 ;
        RECT 14.140 44.650 53.140 44.895 ;
        RECT 14.140 44.610 14.460 44.650 ;
        RECT 14.720 40.960 14.950 44.455 ;
        RECT 15.200 43.260 15.430 44.455 ;
        RECT 15.155 42.940 15.475 43.260 ;
        RECT 14.675 40.640 14.995 40.960 ;
        RECT 14.720 39.455 14.950 40.640 ;
        RECT 15.200 39.455 15.430 42.940 ;
        RECT 15.680 40.960 15.910 44.455 ;
        RECT 16.160 43.260 16.390 44.455 ;
        RECT 16.115 42.940 16.435 43.260 ;
        RECT 15.635 40.640 15.955 40.960 ;
        RECT 15.680 39.455 15.910 40.640 ;
        RECT 16.160 39.455 16.390 42.940 ;
        RECT 16.640 40.960 16.870 44.455 ;
        RECT 17.120 43.260 17.350 44.455 ;
        RECT 17.075 42.940 17.395 43.260 ;
        RECT 16.595 40.640 16.915 40.960 ;
        RECT 16.640 39.455 16.870 40.640 ;
        RECT 17.120 39.455 17.350 42.940 ;
        RECT 17.600 40.960 17.830 44.455 ;
        RECT 18.080 43.260 18.310 44.455 ;
        RECT 18.035 42.940 18.355 43.260 ;
        RECT 17.555 40.640 17.875 40.960 ;
        RECT 17.600 39.455 17.830 40.640 ;
        RECT 18.080 39.455 18.310 42.940 ;
        RECT 18.560 40.960 18.790 44.455 ;
        RECT 19.040 43.260 19.270 44.455 ;
        RECT 18.995 42.940 19.315 43.260 ;
        RECT 18.515 40.640 18.835 40.960 ;
        RECT 18.560 39.455 18.790 40.640 ;
        RECT 19.040 39.455 19.270 42.940 ;
        RECT 19.520 40.960 19.750 44.455 ;
        RECT 20.000 43.260 20.230 44.455 ;
        RECT 19.955 42.940 20.275 43.260 ;
        RECT 19.475 40.640 19.795 40.960 ;
        RECT 19.520 39.455 19.750 40.640 ;
        RECT 20.000 39.455 20.230 42.940 ;
        RECT 20.480 40.960 20.710 44.455 ;
        RECT 20.960 43.260 21.190 44.455 ;
        RECT 20.915 42.940 21.235 43.260 ;
        RECT 20.435 40.640 20.755 40.960 ;
        RECT 20.480 39.455 20.710 40.640 ;
        RECT 20.960 39.455 21.190 42.940 ;
        RECT 21.440 40.960 21.670 44.455 ;
        RECT 21.920 43.260 22.150 44.455 ;
        RECT 21.875 42.940 22.195 43.260 ;
        RECT 21.395 40.640 21.715 40.960 ;
        RECT 21.440 39.455 21.670 40.640 ;
        RECT 21.920 39.455 22.150 42.940 ;
        RECT 22.400 40.960 22.630 44.455 ;
        RECT 22.880 43.260 23.110 44.455 ;
        RECT 22.835 42.940 23.155 43.260 ;
        RECT 22.355 40.640 22.675 40.960 ;
        RECT 22.400 39.455 22.630 40.640 ;
        RECT 22.880 39.455 23.110 42.940 ;
        RECT 23.360 40.960 23.590 44.455 ;
        RECT 23.840 43.260 24.070 44.455 ;
        RECT 23.795 42.940 24.115 43.260 ;
        RECT 23.315 40.640 23.635 40.960 ;
        RECT 23.360 39.455 23.590 40.640 ;
        RECT 23.840 39.455 24.070 42.940 ;
        RECT 24.320 40.960 24.550 44.455 ;
        RECT 24.800 43.260 25.030 44.455 ;
        RECT 24.755 42.940 25.075 43.260 ;
        RECT 24.275 40.640 24.595 40.960 ;
        RECT 24.320 39.455 24.550 40.640 ;
        RECT 24.800 39.455 25.030 42.940 ;
        RECT 25.280 40.960 25.510 44.455 ;
        RECT 25.760 43.260 25.990 44.455 ;
        RECT 25.715 42.940 26.035 43.260 ;
        RECT 25.235 40.640 25.555 40.960 ;
        RECT 25.280 39.455 25.510 40.640 ;
        RECT 25.760 39.455 25.990 42.940 ;
        RECT 26.240 40.960 26.470 44.455 ;
        RECT 26.720 43.260 26.950 44.455 ;
        RECT 26.675 42.940 26.995 43.260 ;
        RECT 26.195 40.640 26.515 40.960 ;
        RECT 26.240 39.455 26.470 40.640 ;
        RECT 26.720 39.455 26.950 42.940 ;
        RECT 27.200 40.960 27.430 44.455 ;
        RECT 27.680 43.260 27.910 44.455 ;
        RECT 27.635 42.940 27.955 43.260 ;
        RECT 27.155 40.640 27.475 40.960 ;
        RECT 27.200 39.455 27.430 40.640 ;
        RECT 27.680 39.455 27.910 42.940 ;
        RECT 28.160 40.960 28.390 44.455 ;
        RECT 28.640 43.260 28.870 44.455 ;
        RECT 28.595 42.940 28.915 43.260 ;
        RECT 28.115 40.640 28.435 40.960 ;
        RECT 28.160 39.455 28.390 40.640 ;
        RECT 28.640 39.455 28.870 42.940 ;
        RECT 29.120 40.960 29.350 44.455 ;
        RECT 29.600 43.260 29.830 44.455 ;
        RECT 29.555 42.940 29.875 43.260 ;
        RECT 29.075 40.640 29.395 40.960 ;
        RECT 29.120 39.455 29.350 40.640 ;
        RECT 29.600 39.455 29.830 42.940 ;
        RECT 30.080 40.960 30.310 44.455 ;
        RECT 30.560 43.260 30.790 44.455 ;
        RECT 30.515 42.940 30.835 43.260 ;
        RECT 30.035 40.640 30.355 40.960 ;
        RECT 30.080 39.455 30.310 40.640 ;
        RECT 30.560 39.455 30.790 42.940 ;
        RECT 31.040 40.960 31.270 44.455 ;
        RECT 31.520 43.260 31.750 44.455 ;
        RECT 31.475 42.940 31.795 43.260 ;
        RECT 30.995 40.640 31.315 40.960 ;
        RECT 31.040 39.455 31.270 40.640 ;
        RECT 31.520 39.455 31.750 42.940 ;
        RECT 32.000 40.960 32.230 44.455 ;
        RECT 32.480 43.260 32.710 44.455 ;
        RECT 32.435 42.940 32.755 43.260 ;
        RECT 31.955 40.640 32.275 40.960 ;
        RECT 32.000 39.455 32.230 40.640 ;
        RECT 32.480 39.455 32.710 42.940 ;
        RECT 32.960 40.960 33.190 44.455 ;
        RECT 33.440 43.260 33.670 44.455 ;
        RECT 33.395 42.940 33.715 43.260 ;
        RECT 32.915 40.640 33.235 40.960 ;
        RECT 32.960 39.455 33.190 40.640 ;
        RECT 33.440 39.455 33.670 42.940 ;
        RECT 33.920 40.960 34.150 44.455 ;
        RECT 34.400 43.260 34.630 44.455 ;
        RECT 34.355 42.940 34.675 43.260 ;
        RECT 33.875 40.640 34.195 40.960 ;
        RECT 33.920 39.455 34.150 40.640 ;
        RECT 34.400 39.455 34.630 42.940 ;
        RECT 34.880 40.960 35.110 44.455 ;
        RECT 35.360 43.260 35.590 44.455 ;
        RECT 35.315 42.940 35.635 43.260 ;
        RECT 34.835 40.640 35.155 40.960 ;
        RECT 34.880 39.455 35.110 40.640 ;
        RECT 35.360 39.455 35.590 42.940 ;
        RECT 35.840 40.960 36.070 44.455 ;
        RECT 36.320 43.260 36.550 44.455 ;
        RECT 36.275 42.940 36.595 43.260 ;
        RECT 35.795 40.640 36.115 40.960 ;
        RECT 35.840 39.455 36.070 40.640 ;
        RECT 36.320 39.455 36.550 42.940 ;
        RECT 36.800 40.960 37.030 44.455 ;
        RECT 37.280 43.260 37.510 44.455 ;
        RECT 37.235 42.940 37.555 43.260 ;
        RECT 36.755 40.640 37.075 40.960 ;
        RECT 36.800 39.455 37.030 40.640 ;
        RECT 37.280 39.455 37.510 42.940 ;
        RECT 37.760 40.960 37.990 44.455 ;
        RECT 38.240 43.260 38.470 44.455 ;
        RECT 38.195 42.940 38.515 43.260 ;
        RECT 37.715 40.640 38.035 40.960 ;
        RECT 37.760 39.455 37.990 40.640 ;
        RECT 38.240 39.455 38.470 42.940 ;
        RECT 38.720 40.960 38.950 44.455 ;
        RECT 39.200 43.260 39.430 44.455 ;
        RECT 39.155 42.940 39.475 43.260 ;
        RECT 38.675 40.640 38.995 40.960 ;
        RECT 38.720 39.455 38.950 40.640 ;
        RECT 39.200 39.455 39.430 42.940 ;
        RECT 39.680 40.960 39.910 44.455 ;
        RECT 40.160 43.260 40.390 44.455 ;
        RECT 40.115 42.940 40.435 43.260 ;
        RECT 39.635 40.640 39.955 40.960 ;
        RECT 39.680 39.455 39.910 40.640 ;
        RECT 40.160 39.455 40.390 42.940 ;
        RECT 40.640 40.960 40.870 44.455 ;
        RECT 41.120 43.260 41.350 44.455 ;
        RECT 41.075 42.940 41.395 43.260 ;
        RECT 40.595 40.640 40.915 40.960 ;
        RECT 40.640 39.455 40.870 40.640 ;
        RECT 41.120 39.455 41.350 42.940 ;
        RECT 41.600 40.960 41.830 44.455 ;
        RECT 42.080 43.260 42.310 44.455 ;
        RECT 42.035 42.940 42.355 43.260 ;
        RECT 41.555 40.640 41.875 40.960 ;
        RECT 41.600 39.455 41.830 40.640 ;
        RECT 42.080 39.455 42.310 42.940 ;
        RECT 42.560 40.960 42.790 44.455 ;
        RECT 43.040 43.260 43.270 44.455 ;
        RECT 42.995 42.940 43.315 43.260 ;
        RECT 42.515 40.640 42.835 40.960 ;
        RECT 42.560 39.455 42.790 40.640 ;
        RECT 43.040 39.455 43.270 42.940 ;
        RECT 43.520 40.960 43.750 44.455 ;
        RECT 44.000 43.260 44.230 44.455 ;
        RECT 43.955 42.940 44.275 43.260 ;
        RECT 43.475 40.640 43.795 40.960 ;
        RECT 43.520 39.455 43.750 40.640 ;
        RECT 44.000 39.455 44.230 42.940 ;
        RECT 44.480 40.960 44.710 44.455 ;
        RECT 44.960 43.260 45.190 44.455 ;
        RECT 44.915 42.940 45.235 43.260 ;
        RECT 44.435 40.640 44.755 40.960 ;
        RECT 44.480 39.455 44.710 40.640 ;
        RECT 44.960 39.455 45.190 42.940 ;
        RECT 45.440 40.960 45.670 44.455 ;
        RECT 45.920 43.260 46.150 44.455 ;
        RECT 45.875 42.940 46.195 43.260 ;
        RECT 45.395 40.640 45.715 40.960 ;
        RECT 45.440 39.455 45.670 40.640 ;
        RECT 45.920 39.455 46.150 42.940 ;
        RECT 46.400 40.960 46.630 44.455 ;
        RECT 46.880 43.260 47.110 44.455 ;
        RECT 46.835 42.940 47.155 43.260 ;
        RECT 46.355 40.640 46.675 40.960 ;
        RECT 46.400 39.455 46.630 40.640 ;
        RECT 46.880 39.455 47.110 42.940 ;
        RECT 47.360 40.960 47.590 44.455 ;
        RECT 47.840 43.260 48.070 44.455 ;
        RECT 47.795 42.940 48.115 43.260 ;
        RECT 47.315 40.640 47.635 40.960 ;
        RECT 47.360 39.455 47.590 40.640 ;
        RECT 47.840 39.455 48.070 42.940 ;
        RECT 48.320 40.960 48.550 44.455 ;
        RECT 48.800 43.260 49.030 44.455 ;
        RECT 48.755 42.940 49.075 43.260 ;
        RECT 48.275 40.640 48.595 40.960 ;
        RECT 48.320 39.455 48.550 40.640 ;
        RECT 48.800 39.455 49.030 42.940 ;
        RECT 49.280 40.960 49.510 44.455 ;
        RECT 49.760 43.260 49.990 44.455 ;
        RECT 49.715 42.940 50.035 43.260 ;
        RECT 49.235 40.640 49.555 40.960 ;
        RECT 49.280 39.455 49.510 40.640 ;
        RECT 49.760 39.455 49.990 42.940 ;
        RECT 50.240 40.960 50.470 44.455 ;
        RECT 50.720 43.260 50.950 44.455 ;
        RECT 50.675 42.940 50.995 43.260 ;
        RECT 50.195 40.640 50.515 40.960 ;
        RECT 50.240 39.455 50.470 40.640 ;
        RECT 50.720 39.455 50.950 42.940 ;
        RECT 51.200 40.960 51.430 44.455 ;
        RECT 51.680 43.260 51.910 44.455 ;
        RECT 51.635 42.940 51.955 43.260 ;
        RECT 51.155 40.640 51.475 40.960 ;
        RECT 51.200 39.455 51.430 40.640 ;
        RECT 51.680 39.455 51.910 42.940 ;
        RECT 52.160 40.960 52.390 44.455 ;
        RECT 52.640 43.260 52.870 44.455 ;
        RECT 52.595 42.940 52.915 43.260 ;
        RECT 52.115 40.640 52.435 40.960 ;
        RECT 52.160 39.455 52.390 40.640 ;
        RECT 52.640 39.455 52.870 42.940 ;
        RECT 53.120 40.960 53.350 44.455 ;
        RECT 57.020 44.355 59.830 46.400 ;
        RECT 59.420 44.290 59.800 44.355 ;
        RECT 53.075 40.640 53.395 40.960 ;
        RECT 53.120 39.455 53.350 40.640 ;
        RECT 14.140 39.255 14.460 39.290 ;
        RECT 14.925 39.255 52.660 39.260 ;
        RECT 14.140 39.015 52.660 39.255 ;
        RECT 14.140 39.010 15.500 39.015 ;
        RECT 14.140 38.970 14.460 39.010 ;
        RECT 14.140 38.715 14.460 38.750 ;
        RECT 14.925 38.715 52.660 38.720 ;
        RECT 14.140 38.475 52.660 38.715 ;
        RECT 14.140 38.470 15.500 38.475 ;
        RECT 14.140 38.430 14.460 38.470 ;
        RECT 14.720 34.780 14.950 38.275 ;
        RECT 15.200 37.080 15.430 38.275 ;
        RECT 15.155 36.760 15.475 37.080 ;
        RECT 14.675 34.460 14.995 34.780 ;
        RECT 14.720 33.275 14.950 34.460 ;
        RECT 15.200 33.275 15.430 36.760 ;
        RECT 15.680 34.780 15.910 38.275 ;
        RECT 16.160 37.080 16.390 38.275 ;
        RECT 16.115 36.760 16.435 37.080 ;
        RECT 15.635 34.460 15.955 34.780 ;
        RECT 15.680 33.275 15.910 34.460 ;
        RECT 16.160 33.275 16.390 36.760 ;
        RECT 16.640 34.780 16.870 38.275 ;
        RECT 17.120 37.080 17.350 38.275 ;
        RECT 17.075 36.760 17.395 37.080 ;
        RECT 16.595 34.460 16.915 34.780 ;
        RECT 16.640 33.275 16.870 34.460 ;
        RECT 17.120 33.275 17.350 36.760 ;
        RECT 17.600 34.780 17.830 38.275 ;
        RECT 18.080 37.080 18.310 38.275 ;
        RECT 18.035 36.760 18.355 37.080 ;
        RECT 17.555 34.460 17.875 34.780 ;
        RECT 17.600 33.275 17.830 34.460 ;
        RECT 18.080 33.275 18.310 36.760 ;
        RECT 18.560 34.780 18.790 38.275 ;
        RECT 19.040 37.080 19.270 38.275 ;
        RECT 18.995 36.760 19.315 37.080 ;
        RECT 18.515 34.460 18.835 34.780 ;
        RECT 18.560 33.275 18.790 34.460 ;
        RECT 19.040 33.275 19.270 36.760 ;
        RECT 19.520 34.780 19.750 38.275 ;
        RECT 20.000 37.080 20.230 38.275 ;
        RECT 19.955 36.760 20.275 37.080 ;
        RECT 19.475 34.460 19.795 34.780 ;
        RECT 19.520 33.275 19.750 34.460 ;
        RECT 20.000 33.275 20.230 36.760 ;
        RECT 20.480 34.780 20.710 38.275 ;
        RECT 20.960 37.080 21.190 38.275 ;
        RECT 20.915 36.760 21.235 37.080 ;
        RECT 20.435 34.460 20.755 34.780 ;
        RECT 20.480 33.275 20.710 34.460 ;
        RECT 20.960 33.275 21.190 36.760 ;
        RECT 21.440 34.780 21.670 38.275 ;
        RECT 21.920 37.080 22.150 38.275 ;
        RECT 21.875 36.760 22.195 37.080 ;
        RECT 21.395 34.460 21.715 34.780 ;
        RECT 21.440 33.275 21.670 34.460 ;
        RECT 21.920 33.275 22.150 36.760 ;
        RECT 22.400 34.780 22.630 38.275 ;
        RECT 22.880 37.080 23.110 38.275 ;
        RECT 22.835 36.760 23.155 37.080 ;
        RECT 22.355 34.460 22.675 34.780 ;
        RECT 22.400 33.275 22.630 34.460 ;
        RECT 22.880 33.275 23.110 36.760 ;
        RECT 23.360 34.780 23.590 38.275 ;
        RECT 23.840 37.080 24.070 38.275 ;
        RECT 23.795 36.760 24.115 37.080 ;
        RECT 23.315 34.460 23.635 34.780 ;
        RECT 23.360 33.275 23.590 34.460 ;
        RECT 23.840 33.275 24.070 36.760 ;
        RECT 24.320 34.780 24.550 38.275 ;
        RECT 24.800 37.080 25.030 38.275 ;
        RECT 24.755 36.760 25.075 37.080 ;
        RECT 24.275 34.460 24.595 34.780 ;
        RECT 24.320 33.275 24.550 34.460 ;
        RECT 24.800 33.275 25.030 36.760 ;
        RECT 25.280 34.780 25.510 38.275 ;
        RECT 25.760 37.080 25.990 38.275 ;
        RECT 25.715 36.760 26.035 37.080 ;
        RECT 25.235 34.460 25.555 34.780 ;
        RECT 25.280 33.275 25.510 34.460 ;
        RECT 25.760 33.275 25.990 36.760 ;
        RECT 26.240 34.780 26.470 38.275 ;
        RECT 26.720 37.080 26.950 38.275 ;
        RECT 26.675 36.760 26.995 37.080 ;
        RECT 26.195 34.460 26.515 34.780 ;
        RECT 26.240 33.275 26.470 34.460 ;
        RECT 26.720 33.275 26.950 36.760 ;
        RECT 27.200 34.780 27.430 38.275 ;
        RECT 27.680 37.080 27.910 38.275 ;
        RECT 27.635 36.760 27.955 37.080 ;
        RECT 27.155 34.460 27.475 34.780 ;
        RECT 27.200 33.275 27.430 34.460 ;
        RECT 27.680 33.275 27.910 36.760 ;
        RECT 28.160 34.780 28.390 38.275 ;
        RECT 28.640 37.080 28.870 38.275 ;
        RECT 28.595 36.760 28.915 37.080 ;
        RECT 28.115 34.460 28.435 34.780 ;
        RECT 28.160 33.275 28.390 34.460 ;
        RECT 28.640 33.275 28.870 36.760 ;
        RECT 29.120 34.780 29.350 38.275 ;
        RECT 29.600 37.080 29.830 38.275 ;
        RECT 29.555 36.760 29.875 37.080 ;
        RECT 29.075 34.460 29.395 34.780 ;
        RECT 29.120 33.275 29.350 34.460 ;
        RECT 29.600 33.275 29.830 36.760 ;
        RECT 30.080 34.780 30.310 38.275 ;
        RECT 30.560 37.080 30.790 38.275 ;
        RECT 30.515 36.760 30.835 37.080 ;
        RECT 30.035 34.460 30.355 34.780 ;
        RECT 30.080 33.275 30.310 34.460 ;
        RECT 30.560 33.275 30.790 36.760 ;
        RECT 31.040 34.780 31.270 38.275 ;
        RECT 31.520 37.080 31.750 38.275 ;
        RECT 31.475 36.760 31.795 37.080 ;
        RECT 30.995 34.460 31.315 34.780 ;
        RECT 31.040 33.275 31.270 34.460 ;
        RECT 31.520 33.275 31.750 36.760 ;
        RECT 32.000 34.780 32.230 38.275 ;
        RECT 32.480 37.080 32.710 38.275 ;
        RECT 32.435 36.760 32.755 37.080 ;
        RECT 31.955 34.460 32.275 34.780 ;
        RECT 32.000 33.275 32.230 34.460 ;
        RECT 32.480 33.275 32.710 36.760 ;
        RECT 32.960 34.780 33.190 38.275 ;
        RECT 33.440 37.080 33.670 38.275 ;
        RECT 33.395 36.760 33.715 37.080 ;
        RECT 32.915 34.460 33.235 34.780 ;
        RECT 32.960 33.275 33.190 34.460 ;
        RECT 33.440 33.275 33.670 36.760 ;
        RECT 33.920 34.780 34.150 38.275 ;
        RECT 34.400 37.080 34.630 38.275 ;
        RECT 34.355 36.760 34.675 37.080 ;
        RECT 33.875 34.460 34.195 34.780 ;
        RECT 33.920 33.275 34.150 34.460 ;
        RECT 34.400 33.275 34.630 36.760 ;
        RECT 34.880 34.780 35.110 38.275 ;
        RECT 35.360 37.080 35.590 38.275 ;
        RECT 35.315 36.760 35.635 37.080 ;
        RECT 34.835 34.460 35.155 34.780 ;
        RECT 34.880 33.275 35.110 34.460 ;
        RECT 35.360 33.275 35.590 36.760 ;
        RECT 35.840 34.780 36.070 38.275 ;
        RECT 36.320 37.080 36.550 38.275 ;
        RECT 36.275 36.760 36.595 37.080 ;
        RECT 35.795 34.460 36.115 34.780 ;
        RECT 35.840 33.275 36.070 34.460 ;
        RECT 36.320 33.275 36.550 36.760 ;
        RECT 36.800 34.780 37.030 38.275 ;
        RECT 37.280 37.080 37.510 38.275 ;
        RECT 37.235 36.760 37.555 37.080 ;
        RECT 36.755 34.460 37.075 34.780 ;
        RECT 36.800 33.275 37.030 34.460 ;
        RECT 37.280 33.275 37.510 36.760 ;
        RECT 37.760 34.780 37.990 38.275 ;
        RECT 38.240 37.080 38.470 38.275 ;
        RECT 38.195 36.760 38.515 37.080 ;
        RECT 37.715 34.460 38.035 34.780 ;
        RECT 37.760 33.275 37.990 34.460 ;
        RECT 38.240 33.275 38.470 36.760 ;
        RECT 38.720 34.780 38.950 38.275 ;
        RECT 39.200 37.080 39.430 38.275 ;
        RECT 39.155 36.760 39.475 37.080 ;
        RECT 38.675 34.460 38.995 34.780 ;
        RECT 38.720 33.275 38.950 34.460 ;
        RECT 39.200 33.275 39.430 36.760 ;
        RECT 39.680 34.780 39.910 38.275 ;
        RECT 40.160 37.080 40.390 38.275 ;
        RECT 40.115 36.760 40.435 37.080 ;
        RECT 39.635 34.460 39.955 34.780 ;
        RECT 39.680 33.275 39.910 34.460 ;
        RECT 40.160 33.275 40.390 36.760 ;
        RECT 40.640 34.780 40.870 38.275 ;
        RECT 41.120 37.080 41.350 38.275 ;
        RECT 41.075 36.760 41.395 37.080 ;
        RECT 40.595 34.460 40.915 34.780 ;
        RECT 40.640 33.275 40.870 34.460 ;
        RECT 41.120 33.275 41.350 36.760 ;
        RECT 41.600 34.780 41.830 38.275 ;
        RECT 42.080 37.080 42.310 38.275 ;
        RECT 42.035 36.760 42.355 37.080 ;
        RECT 41.555 34.460 41.875 34.780 ;
        RECT 41.600 33.275 41.830 34.460 ;
        RECT 42.080 33.275 42.310 36.760 ;
        RECT 42.560 34.780 42.790 38.275 ;
        RECT 43.040 37.080 43.270 38.275 ;
        RECT 42.995 36.760 43.315 37.080 ;
        RECT 42.515 34.460 42.835 34.780 ;
        RECT 42.560 33.275 42.790 34.460 ;
        RECT 43.040 33.275 43.270 36.760 ;
        RECT 43.520 34.780 43.750 38.275 ;
        RECT 44.000 37.080 44.230 38.275 ;
        RECT 43.955 36.760 44.275 37.080 ;
        RECT 43.475 34.460 43.795 34.780 ;
        RECT 43.520 33.275 43.750 34.460 ;
        RECT 44.000 33.275 44.230 36.760 ;
        RECT 44.480 34.780 44.710 38.275 ;
        RECT 44.960 37.080 45.190 38.275 ;
        RECT 44.915 36.760 45.235 37.080 ;
        RECT 44.435 34.460 44.755 34.780 ;
        RECT 44.480 33.275 44.710 34.460 ;
        RECT 44.960 33.275 45.190 36.760 ;
        RECT 45.440 34.780 45.670 38.275 ;
        RECT 45.920 37.080 46.150 38.275 ;
        RECT 45.875 36.760 46.195 37.080 ;
        RECT 45.395 34.460 45.715 34.780 ;
        RECT 45.440 33.275 45.670 34.460 ;
        RECT 45.920 33.275 46.150 36.760 ;
        RECT 46.400 34.780 46.630 38.275 ;
        RECT 46.880 37.080 47.110 38.275 ;
        RECT 46.835 36.760 47.155 37.080 ;
        RECT 46.355 34.460 46.675 34.780 ;
        RECT 46.400 33.275 46.630 34.460 ;
        RECT 46.880 33.275 47.110 36.760 ;
        RECT 47.360 34.780 47.590 38.275 ;
        RECT 47.840 37.080 48.070 38.275 ;
        RECT 47.795 36.760 48.115 37.080 ;
        RECT 47.315 34.460 47.635 34.780 ;
        RECT 47.360 33.275 47.590 34.460 ;
        RECT 47.840 33.275 48.070 36.760 ;
        RECT 48.320 34.780 48.550 38.275 ;
        RECT 48.800 37.080 49.030 38.275 ;
        RECT 48.755 36.760 49.075 37.080 ;
        RECT 48.275 34.460 48.595 34.780 ;
        RECT 48.320 33.275 48.550 34.460 ;
        RECT 48.800 33.275 49.030 36.760 ;
        RECT 49.280 34.780 49.510 38.275 ;
        RECT 49.760 37.080 49.990 38.275 ;
        RECT 49.715 36.760 50.035 37.080 ;
        RECT 49.235 34.460 49.555 34.780 ;
        RECT 49.280 33.275 49.510 34.460 ;
        RECT 49.760 33.275 49.990 36.760 ;
        RECT 50.240 34.780 50.470 38.275 ;
        RECT 50.720 37.080 50.950 38.275 ;
        RECT 50.675 36.760 50.995 37.080 ;
        RECT 50.195 34.460 50.515 34.780 ;
        RECT 50.240 33.275 50.470 34.460 ;
        RECT 50.720 33.275 50.950 36.760 ;
        RECT 51.200 34.780 51.430 38.275 ;
        RECT 51.680 37.080 51.910 38.275 ;
        RECT 51.635 36.760 51.955 37.080 ;
        RECT 51.155 34.460 51.475 34.780 ;
        RECT 51.200 33.275 51.430 34.460 ;
        RECT 51.680 33.275 51.910 36.760 ;
        RECT 52.160 34.780 52.390 38.275 ;
        RECT 52.640 37.080 52.870 38.275 ;
        RECT 52.595 36.760 52.915 37.080 ;
        RECT 52.115 34.460 52.435 34.780 ;
        RECT 52.160 33.275 52.390 34.460 ;
        RECT 52.640 33.275 52.870 36.760 ;
        RECT 53.120 34.780 53.350 38.275 ;
        RECT 53.075 34.460 53.395 34.780 ;
        RECT 53.120 33.275 53.350 34.460 ;
        RECT 14.140 33.075 14.460 33.110 ;
        RECT 14.140 32.830 53.140 33.075 ;
        RECT 14.140 32.790 14.460 32.830 ;
        RECT 14.140 32.535 14.460 32.570 ;
        RECT 14.140 32.290 53.140 32.535 ;
        RECT 14.140 32.250 14.460 32.290 ;
        RECT 14.720 28.600 14.950 32.095 ;
        RECT 15.200 30.900 15.430 32.095 ;
        RECT 15.155 30.580 15.475 30.900 ;
        RECT 14.675 28.280 14.995 28.600 ;
        RECT 14.720 27.095 14.950 28.280 ;
        RECT 15.200 27.095 15.430 30.580 ;
        RECT 15.680 28.600 15.910 32.095 ;
        RECT 16.160 30.900 16.390 32.095 ;
        RECT 16.115 30.580 16.435 30.900 ;
        RECT 15.635 28.280 15.955 28.600 ;
        RECT 15.680 27.095 15.910 28.280 ;
        RECT 16.160 27.095 16.390 30.580 ;
        RECT 16.640 28.600 16.870 32.095 ;
        RECT 17.120 30.900 17.350 32.095 ;
        RECT 17.075 30.580 17.395 30.900 ;
        RECT 16.595 28.280 16.915 28.600 ;
        RECT 16.640 27.095 16.870 28.280 ;
        RECT 17.120 27.095 17.350 30.580 ;
        RECT 17.600 28.600 17.830 32.095 ;
        RECT 18.080 30.900 18.310 32.095 ;
        RECT 18.035 30.580 18.355 30.900 ;
        RECT 17.555 28.280 17.875 28.600 ;
        RECT 17.600 27.095 17.830 28.280 ;
        RECT 18.080 27.095 18.310 30.580 ;
        RECT 18.560 28.600 18.790 32.095 ;
        RECT 19.040 30.900 19.270 32.095 ;
        RECT 18.995 30.580 19.315 30.900 ;
        RECT 18.515 28.280 18.835 28.600 ;
        RECT 18.560 27.095 18.790 28.280 ;
        RECT 19.040 27.095 19.270 30.580 ;
        RECT 19.520 28.600 19.750 32.095 ;
        RECT 20.000 30.900 20.230 32.095 ;
        RECT 19.955 30.580 20.275 30.900 ;
        RECT 19.475 28.280 19.795 28.600 ;
        RECT 19.520 27.095 19.750 28.280 ;
        RECT 20.000 27.095 20.230 30.580 ;
        RECT 20.480 28.600 20.710 32.095 ;
        RECT 20.960 30.900 21.190 32.095 ;
        RECT 20.915 30.580 21.235 30.900 ;
        RECT 20.435 28.280 20.755 28.600 ;
        RECT 20.480 27.095 20.710 28.280 ;
        RECT 20.960 27.095 21.190 30.580 ;
        RECT 21.440 28.600 21.670 32.095 ;
        RECT 21.920 30.900 22.150 32.095 ;
        RECT 21.875 30.580 22.195 30.900 ;
        RECT 21.395 28.280 21.715 28.600 ;
        RECT 21.440 27.095 21.670 28.280 ;
        RECT 21.920 27.095 22.150 30.580 ;
        RECT 22.400 28.600 22.630 32.095 ;
        RECT 22.880 30.900 23.110 32.095 ;
        RECT 22.835 30.580 23.155 30.900 ;
        RECT 22.355 28.280 22.675 28.600 ;
        RECT 22.400 27.095 22.630 28.280 ;
        RECT 22.880 27.095 23.110 30.580 ;
        RECT 23.360 28.600 23.590 32.095 ;
        RECT 23.840 30.900 24.070 32.095 ;
        RECT 23.795 30.580 24.115 30.900 ;
        RECT 23.315 28.280 23.635 28.600 ;
        RECT 23.360 27.095 23.590 28.280 ;
        RECT 23.840 27.095 24.070 30.580 ;
        RECT 24.320 28.600 24.550 32.095 ;
        RECT 24.800 30.900 25.030 32.095 ;
        RECT 24.755 30.580 25.075 30.900 ;
        RECT 24.275 28.280 24.595 28.600 ;
        RECT 24.320 27.095 24.550 28.280 ;
        RECT 24.800 27.095 25.030 30.580 ;
        RECT 25.280 28.600 25.510 32.095 ;
        RECT 25.760 30.900 25.990 32.095 ;
        RECT 25.715 30.580 26.035 30.900 ;
        RECT 25.235 28.280 25.555 28.600 ;
        RECT 25.280 27.095 25.510 28.280 ;
        RECT 25.760 27.095 25.990 30.580 ;
        RECT 26.240 28.600 26.470 32.095 ;
        RECT 26.720 30.900 26.950 32.095 ;
        RECT 26.675 30.580 26.995 30.900 ;
        RECT 26.195 28.280 26.515 28.600 ;
        RECT 26.240 27.095 26.470 28.280 ;
        RECT 26.720 27.095 26.950 30.580 ;
        RECT 27.200 28.600 27.430 32.095 ;
        RECT 27.680 30.900 27.910 32.095 ;
        RECT 27.635 30.580 27.955 30.900 ;
        RECT 27.155 28.280 27.475 28.600 ;
        RECT 27.200 27.095 27.430 28.280 ;
        RECT 27.680 27.095 27.910 30.580 ;
        RECT 28.160 28.600 28.390 32.095 ;
        RECT 28.640 30.900 28.870 32.095 ;
        RECT 28.595 30.580 28.915 30.900 ;
        RECT 28.115 28.280 28.435 28.600 ;
        RECT 28.160 27.095 28.390 28.280 ;
        RECT 28.640 27.095 28.870 30.580 ;
        RECT 29.120 28.600 29.350 32.095 ;
        RECT 29.600 30.900 29.830 32.095 ;
        RECT 29.555 30.580 29.875 30.900 ;
        RECT 29.075 28.280 29.395 28.600 ;
        RECT 29.120 27.095 29.350 28.280 ;
        RECT 29.600 27.095 29.830 30.580 ;
        RECT 30.080 28.600 30.310 32.095 ;
        RECT 30.560 30.900 30.790 32.095 ;
        RECT 30.515 30.580 30.835 30.900 ;
        RECT 30.035 28.280 30.355 28.600 ;
        RECT 30.080 27.095 30.310 28.280 ;
        RECT 30.560 27.095 30.790 30.580 ;
        RECT 31.040 28.600 31.270 32.095 ;
        RECT 31.520 30.900 31.750 32.095 ;
        RECT 31.475 30.580 31.795 30.900 ;
        RECT 30.995 28.280 31.315 28.600 ;
        RECT 31.040 27.095 31.270 28.280 ;
        RECT 31.520 27.095 31.750 30.580 ;
        RECT 32.000 28.600 32.230 32.095 ;
        RECT 32.480 30.900 32.710 32.095 ;
        RECT 32.435 30.580 32.755 30.900 ;
        RECT 31.955 28.280 32.275 28.600 ;
        RECT 32.000 27.095 32.230 28.280 ;
        RECT 32.480 27.095 32.710 30.580 ;
        RECT 32.960 28.600 33.190 32.095 ;
        RECT 33.440 30.900 33.670 32.095 ;
        RECT 33.395 30.580 33.715 30.900 ;
        RECT 32.915 28.280 33.235 28.600 ;
        RECT 32.960 27.095 33.190 28.280 ;
        RECT 33.440 27.095 33.670 30.580 ;
        RECT 33.920 28.600 34.150 32.095 ;
        RECT 34.400 30.900 34.630 32.095 ;
        RECT 34.355 30.580 34.675 30.900 ;
        RECT 33.875 28.280 34.195 28.600 ;
        RECT 33.920 27.095 34.150 28.280 ;
        RECT 34.400 27.095 34.630 30.580 ;
        RECT 34.880 28.600 35.110 32.095 ;
        RECT 35.360 30.900 35.590 32.095 ;
        RECT 35.315 30.580 35.635 30.900 ;
        RECT 34.835 28.280 35.155 28.600 ;
        RECT 34.880 27.095 35.110 28.280 ;
        RECT 35.360 27.095 35.590 30.580 ;
        RECT 35.840 28.600 36.070 32.095 ;
        RECT 36.320 30.900 36.550 32.095 ;
        RECT 36.275 30.580 36.595 30.900 ;
        RECT 35.795 28.280 36.115 28.600 ;
        RECT 35.840 27.095 36.070 28.280 ;
        RECT 36.320 27.095 36.550 30.580 ;
        RECT 36.800 28.600 37.030 32.095 ;
        RECT 37.280 30.900 37.510 32.095 ;
        RECT 37.235 30.580 37.555 30.900 ;
        RECT 36.755 28.280 37.075 28.600 ;
        RECT 36.800 27.095 37.030 28.280 ;
        RECT 37.280 27.095 37.510 30.580 ;
        RECT 37.760 28.600 37.990 32.095 ;
        RECT 38.240 30.900 38.470 32.095 ;
        RECT 38.195 30.580 38.515 30.900 ;
        RECT 37.715 28.280 38.035 28.600 ;
        RECT 37.760 27.095 37.990 28.280 ;
        RECT 38.240 27.095 38.470 30.580 ;
        RECT 38.720 28.600 38.950 32.095 ;
        RECT 39.200 30.900 39.430 32.095 ;
        RECT 39.155 30.580 39.475 30.900 ;
        RECT 38.675 28.280 38.995 28.600 ;
        RECT 38.720 27.095 38.950 28.280 ;
        RECT 39.200 27.095 39.430 30.580 ;
        RECT 39.680 28.600 39.910 32.095 ;
        RECT 40.160 30.900 40.390 32.095 ;
        RECT 40.115 30.580 40.435 30.900 ;
        RECT 39.635 28.280 39.955 28.600 ;
        RECT 39.680 27.095 39.910 28.280 ;
        RECT 40.160 27.095 40.390 30.580 ;
        RECT 40.640 28.600 40.870 32.095 ;
        RECT 41.120 30.900 41.350 32.095 ;
        RECT 41.075 30.580 41.395 30.900 ;
        RECT 40.595 28.280 40.915 28.600 ;
        RECT 40.640 27.095 40.870 28.280 ;
        RECT 41.120 27.095 41.350 30.580 ;
        RECT 41.600 28.600 41.830 32.095 ;
        RECT 42.080 30.900 42.310 32.095 ;
        RECT 42.035 30.580 42.355 30.900 ;
        RECT 41.555 28.280 41.875 28.600 ;
        RECT 41.600 27.095 41.830 28.280 ;
        RECT 42.080 27.095 42.310 30.580 ;
        RECT 42.560 28.600 42.790 32.095 ;
        RECT 43.040 30.900 43.270 32.095 ;
        RECT 42.995 30.580 43.315 30.900 ;
        RECT 42.515 28.280 42.835 28.600 ;
        RECT 42.560 27.095 42.790 28.280 ;
        RECT 43.040 27.095 43.270 30.580 ;
        RECT 43.520 28.600 43.750 32.095 ;
        RECT 44.000 30.900 44.230 32.095 ;
        RECT 43.955 30.580 44.275 30.900 ;
        RECT 43.475 28.280 43.795 28.600 ;
        RECT 43.520 27.095 43.750 28.280 ;
        RECT 44.000 27.095 44.230 30.580 ;
        RECT 44.480 28.600 44.710 32.095 ;
        RECT 44.960 30.900 45.190 32.095 ;
        RECT 44.915 30.580 45.235 30.900 ;
        RECT 44.435 28.280 44.755 28.600 ;
        RECT 44.480 27.095 44.710 28.280 ;
        RECT 44.960 27.095 45.190 30.580 ;
        RECT 45.440 28.600 45.670 32.095 ;
        RECT 45.920 30.900 46.150 32.095 ;
        RECT 45.875 30.580 46.195 30.900 ;
        RECT 45.395 28.280 45.715 28.600 ;
        RECT 45.440 27.095 45.670 28.280 ;
        RECT 45.920 27.095 46.150 30.580 ;
        RECT 46.400 28.600 46.630 32.095 ;
        RECT 46.880 30.900 47.110 32.095 ;
        RECT 46.835 30.580 47.155 30.900 ;
        RECT 46.355 28.280 46.675 28.600 ;
        RECT 46.400 27.095 46.630 28.280 ;
        RECT 46.880 27.095 47.110 30.580 ;
        RECT 47.360 28.600 47.590 32.095 ;
        RECT 47.840 30.900 48.070 32.095 ;
        RECT 47.795 30.580 48.115 30.900 ;
        RECT 47.315 28.280 47.635 28.600 ;
        RECT 47.360 27.095 47.590 28.280 ;
        RECT 47.840 27.095 48.070 30.580 ;
        RECT 48.320 28.600 48.550 32.095 ;
        RECT 48.800 30.900 49.030 32.095 ;
        RECT 48.755 30.580 49.075 30.900 ;
        RECT 48.275 28.280 48.595 28.600 ;
        RECT 48.320 27.095 48.550 28.280 ;
        RECT 48.800 27.095 49.030 30.580 ;
        RECT 49.280 28.600 49.510 32.095 ;
        RECT 49.760 30.900 49.990 32.095 ;
        RECT 49.715 30.580 50.035 30.900 ;
        RECT 49.235 28.280 49.555 28.600 ;
        RECT 49.280 27.095 49.510 28.280 ;
        RECT 49.760 27.095 49.990 30.580 ;
        RECT 50.240 28.600 50.470 32.095 ;
        RECT 50.720 30.900 50.950 32.095 ;
        RECT 50.675 30.580 50.995 30.900 ;
        RECT 50.195 28.280 50.515 28.600 ;
        RECT 50.240 27.095 50.470 28.280 ;
        RECT 50.720 27.095 50.950 30.580 ;
        RECT 51.200 28.600 51.430 32.095 ;
        RECT 51.680 30.900 51.910 32.095 ;
        RECT 51.635 30.580 51.955 30.900 ;
        RECT 51.155 28.280 51.475 28.600 ;
        RECT 51.200 27.095 51.430 28.280 ;
        RECT 51.680 27.095 51.910 30.580 ;
        RECT 52.160 28.600 52.390 32.095 ;
        RECT 52.640 30.900 52.870 32.095 ;
        RECT 52.595 30.580 52.915 30.900 ;
        RECT 52.115 28.280 52.435 28.600 ;
        RECT 52.160 27.095 52.390 28.280 ;
        RECT 52.640 27.095 52.870 30.580 ;
        RECT 53.120 28.600 53.350 32.095 ;
        RECT 57.020 30.060 59.830 32.105 ;
        RECT 53.075 28.280 53.395 28.600 ;
        RECT 53.120 27.095 53.350 28.280 ;
        RECT 14.140 26.895 14.460 26.930 ;
        RECT 14.140 26.650 52.665 26.895 ;
        RECT 14.140 26.610 14.460 26.650 ;
        RECT 53.020 26.085 53.380 26.445 ;
        RECT 19.270 24.350 19.650 24.530 ;
        RECT 17.650 24.320 18.110 24.350 ;
        RECT 18.440 24.320 18.900 24.350 ;
        RECT 19.230 24.320 19.690 24.350 ;
        RECT 20.020 24.320 20.480 24.350 ;
        RECT 20.810 24.320 21.270 24.350 ;
        RECT 21.600 24.320 22.060 24.350 ;
        RECT 17.630 24.150 22.080 24.320 ;
        RECT 17.650 24.120 18.110 24.150 ;
        RECT 18.440 24.120 18.900 24.150 ;
        RECT 19.230 24.120 19.690 24.150 ;
        RECT 20.020 24.120 20.480 24.150 ;
        RECT 20.810 24.120 21.270 24.150 ;
        RECT 21.600 24.120 22.060 24.150 ;
        RECT 17.370 23.550 17.600 23.960 ;
        RECT 17.325 23.200 17.645 23.550 ;
        RECT 17.370 18.960 17.600 23.200 ;
        RECT 18.160 19.450 18.390 23.960 ;
        RECT 18.950 23.550 19.180 23.960 ;
        RECT 18.905 23.200 19.225 23.550 ;
        RECT 18.115 19.100 18.435 19.450 ;
        RECT 18.160 18.960 18.390 19.100 ;
        RECT 18.950 18.960 19.180 23.200 ;
        RECT 19.740 19.450 19.970 23.960 ;
        RECT 20.530 23.550 20.760 23.960 ;
        RECT 20.485 23.200 20.805 23.550 ;
        RECT 19.695 19.100 20.015 19.450 ;
        RECT 19.740 18.960 19.970 19.100 ;
        RECT 20.530 18.960 20.760 23.200 ;
        RECT 21.320 19.450 21.550 23.960 ;
        RECT 22.110 23.550 22.340 23.960 ;
        RECT 22.065 23.200 22.385 23.550 ;
        RECT 21.275 19.100 21.595 19.450 ;
        RECT 21.320 18.960 21.550 19.100 ;
        RECT 22.110 18.960 22.340 23.200 ;
        RECT 24.660 22.285 25.970 24.390 ;
        RECT 24.660 18.930 25.970 21.035 ;
        RECT 17.650 18.770 18.110 18.800 ;
        RECT 18.440 18.770 18.900 18.800 ;
        RECT 19.230 18.770 19.690 18.800 ;
        RECT 20.020 18.770 20.480 18.800 ;
        RECT 20.810 18.770 21.270 18.800 ;
        RECT 21.600 18.770 22.060 18.800 ;
        RECT 17.630 18.600 22.080 18.770 ;
        RECT 17.650 18.570 18.110 18.600 ;
        RECT 18.440 18.570 18.900 18.600 ;
        RECT 19.230 18.570 19.690 18.600 ;
        RECT 20.020 18.570 20.480 18.600 ;
        RECT 20.810 18.570 21.270 18.600 ;
        RECT 21.600 18.570 22.060 18.600 ;
        RECT 21.320 18.015 21.680 18.375 ;
      LAYER met2 ;
        RECT 138.270 223.710 142.300 224.090 ;
        RECT 80.190 106.240 80.490 106.300 ;
        RECT 80.155 105.860 80.525 106.240 ;
        RECT 16.215 105.065 16.585 105.445 ;
        RECT 61.665 105.065 62.035 105.445 ;
        RECT 79.440 105.065 79.810 105.445 ;
        RECT 16.250 91.745 16.550 105.065 ;
        RECT 61.700 92.105 62.000 105.065 ;
        RECT 61.120 91.745 62.000 92.105 ;
        RECT 14.150 90.600 61.495 90.950 ;
        RECT 14.150 88.720 14.450 90.600 ;
        RECT 61.700 88.720 62.000 91.745 ;
        RECT 79.475 90.685 79.775 105.065 ;
        RECT 80.190 103.800 80.490 105.860 ;
        RECT 139.415 105.065 139.785 105.445 ;
        RECT 80.155 100.015 80.525 100.385 ;
        RECT 84.965 91.740 85.335 92.110 ;
        RECT 137.415 91.950 137.785 93.110 ;
        RECT 139.450 91.950 139.750 105.065 ;
        RECT 141.415 91.950 141.785 93.110 ;
        RECT 137.415 91.900 141.810 91.950 ;
        RECT 85.000 90.685 85.300 91.740 ;
        RECT 137.440 91.600 141.810 91.900 ;
        RECT 79.440 90.315 87.710 90.685 ;
        RECT 14.115 88.350 14.485 88.720 ;
        RECT 61.665 88.350 62.035 88.720 ;
        RECT 142.000 88.130 142.300 223.710 ;
        RECT 155.990 123.415 156.360 123.785 ;
        RECT 152.550 105.805 153.360 106.195 ;
        RECT 150.425 104.755 150.795 105.125 ;
        RECT 7.850 87.780 142.300 88.130 ;
        RECT 7.850 24.520 8.150 87.780 ;
        RECT 14.115 87.190 14.485 87.560 ;
        RECT 61.665 87.190 62.035 87.560 ;
        RECT 136.645 87.210 137.025 87.590 ;
        RECT 140.650 87.265 141.020 87.635 ;
        RECT 14.150 79.400 14.450 87.190 ;
        RECT 61.700 86.650 62.000 87.190 ;
        RECT 15.465 86.300 62.000 86.650 ;
        RECT 78.650 86.315 88.500 86.685 ;
        RECT 137.115 86.590 137.485 86.960 ;
        RECT 140.685 85.950 140.985 87.265 ;
        RECT 150.460 85.950 150.760 104.755 ;
        RECT 89.390 85.600 150.760 85.950 ;
        RECT 22.650 84.900 23.020 85.270 ;
        RECT 14.150 79.030 58.680 79.400 ;
        RECT 14.150 26.550 14.450 79.030 ;
        RECT 15.250 76.650 36.350 77.020 ;
        RECT 44.200 75.785 44.500 79.030 ;
        RECT 58.320 75.785 58.680 79.030 ;
        RECT 83.165 76.650 83.535 77.020 ;
        RECT 130.100 76.650 140.500 77.020 ;
        RECT 83.200 75.785 83.500 76.650 ;
        RECT 140.685 75.785 140.985 85.600 ;
        RECT 141.410 76.650 141.800 77.020 ;
        RECT 22.675 75.415 25.575 75.785 ;
        RECT 28.675 75.415 44.795 75.785 ;
        RECT 51.465 75.415 58.685 75.785 ;
        RECT 79.940 75.415 85.470 75.785 ;
        RECT 130.940 75.415 131.310 75.785 ;
        RECT 136.675 75.415 138.600 75.785 ;
        RECT 140.675 75.415 142.600 75.785 ;
        RECT 27.160 72.650 27.540 72.660 ;
        RECT 18.675 72.300 58.895 72.650 ;
        RECT 27.160 72.290 27.540 72.300 ;
        RECT 19.940 71.650 20.310 71.660 ;
        RECT 15.950 71.300 44.050 71.650 ;
        RECT 19.940 71.290 20.310 71.300 ;
        RECT 59.760 71.265 86.760 71.635 ;
        RECT 129.670 71.300 141.790 71.650 ;
        RECT 27.160 70.655 27.540 71.035 ;
        RECT 137.420 70.540 152.370 70.950 ;
        RECT 15.300 70.000 133.090 70.370 ;
        RECT 15.130 55.275 15.500 55.645 ;
        RECT 16.090 55.275 16.460 55.645 ;
        RECT 17.050 55.275 17.420 55.645 ;
        RECT 18.010 55.275 18.380 55.645 ;
        RECT 18.970 55.275 19.340 55.645 ;
        RECT 19.930 55.275 20.300 55.645 ;
        RECT 20.890 55.275 21.260 55.645 ;
        RECT 21.850 55.275 22.220 55.645 ;
        RECT 22.810 55.275 23.180 55.645 ;
        RECT 23.770 55.275 24.140 55.645 ;
        RECT 24.730 55.275 25.100 55.645 ;
        RECT 25.690 55.275 26.060 55.645 ;
        RECT 26.650 55.275 27.020 55.645 ;
        RECT 27.610 55.275 27.980 55.645 ;
        RECT 28.570 55.275 28.940 55.645 ;
        RECT 29.530 55.275 29.900 55.645 ;
        RECT 30.490 55.275 30.860 55.645 ;
        RECT 31.450 55.275 31.820 55.645 ;
        RECT 32.410 55.275 32.780 55.645 ;
        RECT 33.370 55.275 33.740 55.645 ;
        RECT 34.330 55.275 34.700 55.645 ;
        RECT 35.290 55.275 35.660 55.645 ;
        RECT 36.250 55.275 36.620 55.645 ;
        RECT 37.210 55.275 37.580 55.645 ;
        RECT 38.170 55.275 38.540 55.645 ;
        RECT 39.130 55.275 39.500 55.645 ;
        RECT 40.090 55.275 40.460 55.645 ;
        RECT 41.050 55.275 41.420 55.645 ;
        RECT 42.010 55.275 42.380 55.645 ;
        RECT 42.970 55.275 43.340 55.645 ;
        RECT 43.930 55.275 44.300 55.645 ;
        RECT 44.890 55.275 45.260 55.645 ;
        RECT 45.850 55.275 46.220 55.645 ;
        RECT 46.810 55.275 47.180 55.645 ;
        RECT 47.770 55.275 48.140 55.645 ;
        RECT 48.730 55.275 49.100 55.645 ;
        RECT 49.690 55.275 50.060 55.645 ;
        RECT 50.650 55.275 51.020 55.645 ;
        RECT 51.610 55.275 51.980 55.645 ;
        RECT 52.570 55.275 52.940 55.645 ;
        RECT 14.650 52.975 15.020 53.345 ;
        RECT 15.610 52.975 15.980 53.345 ;
        RECT 16.570 52.975 16.940 53.345 ;
        RECT 17.530 52.975 17.900 53.345 ;
        RECT 18.490 52.975 18.860 53.345 ;
        RECT 19.450 52.975 19.820 53.345 ;
        RECT 20.410 52.975 20.780 53.345 ;
        RECT 21.370 52.975 21.740 53.345 ;
        RECT 22.330 52.975 22.700 53.345 ;
        RECT 23.290 52.975 23.660 53.345 ;
        RECT 24.250 52.975 24.620 53.345 ;
        RECT 25.210 52.975 25.580 53.345 ;
        RECT 26.170 52.975 26.540 53.345 ;
        RECT 27.130 52.975 27.500 53.345 ;
        RECT 28.090 52.975 28.460 53.345 ;
        RECT 29.050 52.975 29.420 53.345 ;
        RECT 30.010 52.975 30.380 53.345 ;
        RECT 30.970 52.975 31.340 53.345 ;
        RECT 31.930 52.975 32.300 53.345 ;
        RECT 32.890 52.975 33.260 53.345 ;
        RECT 33.850 52.975 34.220 53.345 ;
        RECT 34.810 52.975 35.180 53.345 ;
        RECT 35.770 52.975 36.140 53.345 ;
        RECT 36.730 52.975 37.100 53.345 ;
        RECT 37.690 52.975 38.060 53.345 ;
        RECT 38.650 52.975 39.020 53.345 ;
        RECT 39.610 52.975 39.980 53.345 ;
        RECT 40.570 52.975 40.940 53.345 ;
        RECT 41.530 52.975 41.900 53.345 ;
        RECT 42.490 52.975 42.860 53.345 ;
        RECT 43.450 52.975 43.820 53.345 ;
        RECT 44.410 52.975 44.780 53.345 ;
        RECT 45.370 52.975 45.740 53.345 ;
        RECT 46.330 52.975 46.700 53.345 ;
        RECT 47.290 52.975 47.660 53.345 ;
        RECT 48.250 52.975 48.620 53.345 ;
        RECT 49.210 52.975 49.580 53.345 ;
        RECT 50.170 52.975 50.540 53.345 ;
        RECT 51.130 52.975 51.500 53.345 ;
        RECT 52.090 52.975 52.460 53.345 ;
        RECT 53.050 52.975 53.420 53.345 ;
        RECT 15.130 49.095 15.500 49.465 ;
        RECT 16.090 49.095 16.460 49.465 ;
        RECT 17.050 49.095 17.420 49.465 ;
        RECT 18.010 49.095 18.380 49.465 ;
        RECT 18.970 49.095 19.340 49.465 ;
        RECT 19.930 49.095 20.300 49.465 ;
        RECT 20.890 49.095 21.260 49.465 ;
        RECT 21.850 49.095 22.220 49.465 ;
        RECT 22.810 49.095 23.180 49.465 ;
        RECT 23.770 49.095 24.140 49.465 ;
        RECT 24.730 49.095 25.100 49.465 ;
        RECT 25.690 49.095 26.060 49.465 ;
        RECT 26.650 49.095 27.020 49.465 ;
        RECT 27.610 49.095 27.980 49.465 ;
        RECT 28.570 49.095 28.940 49.465 ;
        RECT 29.530 49.095 29.900 49.465 ;
        RECT 30.490 49.095 30.860 49.465 ;
        RECT 31.450 49.095 31.820 49.465 ;
        RECT 32.410 49.095 32.780 49.465 ;
        RECT 33.370 49.095 33.740 49.465 ;
        RECT 34.330 49.095 34.700 49.465 ;
        RECT 35.290 49.095 35.660 49.465 ;
        RECT 36.250 49.095 36.620 49.465 ;
        RECT 37.210 49.095 37.580 49.465 ;
        RECT 38.170 49.095 38.540 49.465 ;
        RECT 39.130 49.095 39.500 49.465 ;
        RECT 40.090 49.095 40.460 49.465 ;
        RECT 41.050 49.095 41.420 49.465 ;
        RECT 42.010 49.095 42.380 49.465 ;
        RECT 42.970 49.095 43.340 49.465 ;
        RECT 43.930 49.095 44.300 49.465 ;
        RECT 44.890 49.095 45.260 49.465 ;
        RECT 45.850 49.095 46.220 49.465 ;
        RECT 46.810 49.095 47.180 49.465 ;
        RECT 47.770 49.095 48.140 49.465 ;
        RECT 48.730 49.095 49.100 49.465 ;
        RECT 49.690 49.095 50.060 49.465 ;
        RECT 50.650 49.095 51.020 49.465 ;
        RECT 51.610 49.095 51.980 49.465 ;
        RECT 52.570 49.095 52.940 49.465 ;
        RECT 14.650 46.795 15.020 47.165 ;
        RECT 15.610 46.795 15.980 47.165 ;
        RECT 16.570 46.795 16.940 47.165 ;
        RECT 17.530 46.795 17.900 47.165 ;
        RECT 18.490 46.795 18.860 47.165 ;
        RECT 19.450 46.795 19.820 47.165 ;
        RECT 20.410 46.795 20.780 47.165 ;
        RECT 21.370 46.795 21.740 47.165 ;
        RECT 22.330 46.795 22.700 47.165 ;
        RECT 23.290 46.795 23.660 47.165 ;
        RECT 24.250 46.795 24.620 47.165 ;
        RECT 25.210 46.795 25.580 47.165 ;
        RECT 26.170 46.795 26.540 47.165 ;
        RECT 27.130 46.795 27.500 47.165 ;
        RECT 28.090 46.795 28.460 47.165 ;
        RECT 29.050 46.795 29.420 47.165 ;
        RECT 30.010 46.795 30.380 47.165 ;
        RECT 30.970 46.795 31.340 47.165 ;
        RECT 31.930 46.795 32.300 47.165 ;
        RECT 32.890 46.795 33.260 47.165 ;
        RECT 33.850 46.795 34.220 47.165 ;
        RECT 34.810 46.795 35.180 47.165 ;
        RECT 35.770 46.795 36.140 47.165 ;
        RECT 36.730 46.795 37.100 47.165 ;
        RECT 37.690 46.795 38.060 47.165 ;
        RECT 38.650 46.795 39.020 47.165 ;
        RECT 39.610 46.795 39.980 47.165 ;
        RECT 40.570 46.795 40.940 47.165 ;
        RECT 41.530 46.795 41.900 47.165 ;
        RECT 42.490 46.795 42.860 47.165 ;
        RECT 43.450 46.795 43.820 47.165 ;
        RECT 44.410 46.795 44.780 47.165 ;
        RECT 45.370 46.795 45.740 47.165 ;
        RECT 46.330 46.795 46.700 47.165 ;
        RECT 47.290 46.795 47.660 47.165 ;
        RECT 48.250 46.795 48.620 47.165 ;
        RECT 49.210 46.795 49.580 47.165 ;
        RECT 50.170 46.795 50.540 47.165 ;
        RECT 51.130 46.795 51.500 47.165 ;
        RECT 52.090 46.795 52.460 47.165 ;
        RECT 53.050 46.795 53.420 47.165 ;
        RECT 59.420 44.290 59.800 44.660 ;
        RECT 15.130 42.915 15.500 43.285 ;
        RECT 16.090 42.915 16.460 43.285 ;
        RECT 17.050 42.915 17.420 43.285 ;
        RECT 18.010 42.915 18.380 43.285 ;
        RECT 18.970 42.915 19.340 43.285 ;
        RECT 19.930 42.915 20.300 43.285 ;
        RECT 20.890 42.915 21.260 43.285 ;
        RECT 21.850 42.915 22.220 43.285 ;
        RECT 22.810 42.915 23.180 43.285 ;
        RECT 23.770 42.915 24.140 43.285 ;
        RECT 24.730 42.915 25.100 43.285 ;
        RECT 25.690 42.915 26.060 43.285 ;
        RECT 26.650 42.915 27.020 43.285 ;
        RECT 27.610 42.915 27.980 43.285 ;
        RECT 28.570 42.915 28.940 43.285 ;
        RECT 29.530 42.915 29.900 43.285 ;
        RECT 30.490 42.915 30.860 43.285 ;
        RECT 31.450 42.915 31.820 43.285 ;
        RECT 32.410 42.915 32.780 43.285 ;
        RECT 33.370 42.915 33.740 43.285 ;
        RECT 34.330 42.915 34.700 43.285 ;
        RECT 35.290 42.915 35.660 43.285 ;
        RECT 36.250 42.915 36.620 43.285 ;
        RECT 37.210 42.915 37.580 43.285 ;
        RECT 38.170 42.915 38.540 43.285 ;
        RECT 39.130 42.915 39.500 43.285 ;
        RECT 40.090 42.915 40.460 43.285 ;
        RECT 41.050 42.915 41.420 43.285 ;
        RECT 42.010 42.915 42.380 43.285 ;
        RECT 42.970 42.915 43.340 43.285 ;
        RECT 43.930 42.915 44.300 43.285 ;
        RECT 44.890 42.915 45.260 43.285 ;
        RECT 45.850 42.915 46.220 43.285 ;
        RECT 46.810 42.915 47.180 43.285 ;
        RECT 47.770 42.915 48.140 43.285 ;
        RECT 48.730 42.915 49.100 43.285 ;
        RECT 49.690 42.915 50.060 43.285 ;
        RECT 50.650 42.915 51.020 43.285 ;
        RECT 51.610 42.915 51.980 43.285 ;
        RECT 52.570 42.915 52.940 43.285 ;
        RECT 14.650 40.615 15.020 40.985 ;
        RECT 15.610 40.615 15.980 40.985 ;
        RECT 16.570 40.615 16.940 40.985 ;
        RECT 17.530 40.615 17.900 40.985 ;
        RECT 18.490 40.615 18.860 40.985 ;
        RECT 19.450 40.615 19.820 40.985 ;
        RECT 20.410 40.615 20.780 40.985 ;
        RECT 21.370 40.615 21.740 40.985 ;
        RECT 22.330 40.615 22.700 40.985 ;
        RECT 23.290 40.615 23.660 40.985 ;
        RECT 24.250 40.615 24.620 40.985 ;
        RECT 25.210 40.615 25.580 40.985 ;
        RECT 26.170 40.615 26.540 40.985 ;
        RECT 27.130 40.615 27.500 40.985 ;
        RECT 28.090 40.615 28.460 40.985 ;
        RECT 29.050 40.615 29.420 40.985 ;
        RECT 30.010 40.615 30.380 40.985 ;
        RECT 30.970 40.615 31.340 40.985 ;
        RECT 31.930 40.615 32.300 40.985 ;
        RECT 32.890 40.615 33.260 40.985 ;
        RECT 33.850 40.615 34.220 40.985 ;
        RECT 34.810 40.615 35.180 40.985 ;
        RECT 35.770 40.615 36.140 40.985 ;
        RECT 36.730 40.615 37.100 40.985 ;
        RECT 37.690 40.615 38.060 40.985 ;
        RECT 38.650 40.615 39.020 40.985 ;
        RECT 39.610 40.615 39.980 40.985 ;
        RECT 40.570 40.615 40.940 40.985 ;
        RECT 41.530 40.615 41.900 40.985 ;
        RECT 42.490 40.615 42.860 40.985 ;
        RECT 43.450 40.615 43.820 40.985 ;
        RECT 44.410 40.615 44.780 40.985 ;
        RECT 45.370 40.615 45.740 40.985 ;
        RECT 46.330 40.615 46.700 40.985 ;
        RECT 47.290 40.615 47.660 40.985 ;
        RECT 48.250 40.615 48.620 40.985 ;
        RECT 49.210 40.615 49.580 40.985 ;
        RECT 50.170 40.615 50.540 40.985 ;
        RECT 51.130 40.615 51.500 40.985 ;
        RECT 52.090 40.615 52.460 40.985 ;
        RECT 53.050 40.615 53.420 40.985 ;
        RECT 15.130 36.735 15.500 37.105 ;
        RECT 16.090 36.735 16.460 37.105 ;
        RECT 17.050 36.735 17.420 37.105 ;
        RECT 18.010 36.735 18.380 37.105 ;
        RECT 18.970 36.735 19.340 37.105 ;
        RECT 19.930 36.735 20.300 37.105 ;
        RECT 20.890 36.735 21.260 37.105 ;
        RECT 21.850 36.735 22.220 37.105 ;
        RECT 22.810 36.735 23.180 37.105 ;
        RECT 23.770 36.735 24.140 37.105 ;
        RECT 24.730 36.735 25.100 37.105 ;
        RECT 25.690 36.735 26.060 37.105 ;
        RECT 26.650 36.735 27.020 37.105 ;
        RECT 27.610 36.735 27.980 37.105 ;
        RECT 28.570 36.735 28.940 37.105 ;
        RECT 29.530 36.735 29.900 37.105 ;
        RECT 30.490 36.735 30.860 37.105 ;
        RECT 31.450 36.735 31.820 37.105 ;
        RECT 32.410 36.735 32.780 37.105 ;
        RECT 33.370 36.735 33.740 37.105 ;
        RECT 34.330 36.735 34.700 37.105 ;
        RECT 35.290 36.735 35.660 37.105 ;
        RECT 36.250 36.735 36.620 37.105 ;
        RECT 37.210 36.735 37.580 37.105 ;
        RECT 38.170 36.735 38.540 37.105 ;
        RECT 39.130 36.735 39.500 37.105 ;
        RECT 40.090 36.735 40.460 37.105 ;
        RECT 41.050 36.735 41.420 37.105 ;
        RECT 42.010 36.735 42.380 37.105 ;
        RECT 42.970 36.735 43.340 37.105 ;
        RECT 43.930 36.735 44.300 37.105 ;
        RECT 44.890 36.735 45.260 37.105 ;
        RECT 45.850 36.735 46.220 37.105 ;
        RECT 46.810 36.735 47.180 37.105 ;
        RECT 47.770 36.735 48.140 37.105 ;
        RECT 48.730 36.735 49.100 37.105 ;
        RECT 49.690 36.735 50.060 37.105 ;
        RECT 50.650 36.735 51.020 37.105 ;
        RECT 51.610 36.735 51.980 37.105 ;
        RECT 52.570 36.735 52.940 37.105 ;
        RECT 14.650 34.435 15.020 34.805 ;
        RECT 15.610 34.435 15.980 34.805 ;
        RECT 16.570 34.435 16.940 34.805 ;
        RECT 17.530 34.435 17.900 34.805 ;
        RECT 18.490 34.435 18.860 34.805 ;
        RECT 19.450 34.435 19.820 34.805 ;
        RECT 20.410 34.435 20.780 34.805 ;
        RECT 21.370 34.435 21.740 34.805 ;
        RECT 22.330 34.435 22.700 34.805 ;
        RECT 23.290 34.435 23.660 34.805 ;
        RECT 24.250 34.435 24.620 34.805 ;
        RECT 25.210 34.435 25.580 34.805 ;
        RECT 26.170 34.435 26.540 34.805 ;
        RECT 27.130 34.435 27.500 34.805 ;
        RECT 28.090 34.435 28.460 34.805 ;
        RECT 29.050 34.435 29.420 34.805 ;
        RECT 30.010 34.435 30.380 34.805 ;
        RECT 30.970 34.435 31.340 34.805 ;
        RECT 31.930 34.435 32.300 34.805 ;
        RECT 32.890 34.435 33.260 34.805 ;
        RECT 33.850 34.435 34.220 34.805 ;
        RECT 34.810 34.435 35.180 34.805 ;
        RECT 35.770 34.435 36.140 34.805 ;
        RECT 36.730 34.435 37.100 34.805 ;
        RECT 37.690 34.435 38.060 34.805 ;
        RECT 38.650 34.435 39.020 34.805 ;
        RECT 39.610 34.435 39.980 34.805 ;
        RECT 40.570 34.435 40.940 34.805 ;
        RECT 41.530 34.435 41.900 34.805 ;
        RECT 42.490 34.435 42.860 34.805 ;
        RECT 43.450 34.435 43.820 34.805 ;
        RECT 44.410 34.435 44.780 34.805 ;
        RECT 45.370 34.435 45.740 34.805 ;
        RECT 46.330 34.435 46.700 34.805 ;
        RECT 47.290 34.435 47.660 34.805 ;
        RECT 48.250 34.435 48.620 34.805 ;
        RECT 49.210 34.435 49.580 34.805 ;
        RECT 50.170 34.435 50.540 34.805 ;
        RECT 51.130 34.435 51.500 34.805 ;
        RECT 52.090 34.435 52.460 34.805 ;
        RECT 53.050 34.435 53.420 34.805 ;
        RECT 15.130 30.555 15.500 30.925 ;
        RECT 16.090 30.555 16.460 30.925 ;
        RECT 17.050 30.555 17.420 30.925 ;
        RECT 18.010 30.555 18.380 30.925 ;
        RECT 18.970 30.555 19.340 30.925 ;
        RECT 19.930 30.555 20.300 30.925 ;
        RECT 20.890 30.555 21.260 30.925 ;
        RECT 21.850 30.555 22.220 30.925 ;
        RECT 22.810 30.555 23.180 30.925 ;
        RECT 23.770 30.555 24.140 30.925 ;
        RECT 24.730 30.555 25.100 30.925 ;
        RECT 25.690 30.555 26.060 30.925 ;
        RECT 26.650 30.555 27.020 30.925 ;
        RECT 27.610 30.555 27.980 30.925 ;
        RECT 28.570 30.555 28.940 30.925 ;
        RECT 29.530 30.555 29.900 30.925 ;
        RECT 30.490 30.555 30.860 30.925 ;
        RECT 31.450 30.555 31.820 30.925 ;
        RECT 32.410 30.555 32.780 30.925 ;
        RECT 33.370 30.555 33.740 30.925 ;
        RECT 34.330 30.555 34.700 30.925 ;
        RECT 35.290 30.555 35.660 30.925 ;
        RECT 36.250 30.555 36.620 30.925 ;
        RECT 37.210 30.555 37.580 30.925 ;
        RECT 38.170 30.555 38.540 30.925 ;
        RECT 39.130 30.555 39.500 30.925 ;
        RECT 40.090 30.555 40.460 30.925 ;
        RECT 41.050 30.555 41.420 30.925 ;
        RECT 42.010 30.555 42.380 30.925 ;
        RECT 42.970 30.555 43.340 30.925 ;
        RECT 43.930 30.555 44.300 30.925 ;
        RECT 44.890 30.555 45.260 30.925 ;
        RECT 45.850 30.555 46.220 30.925 ;
        RECT 46.810 30.555 47.180 30.925 ;
        RECT 47.770 30.555 48.140 30.925 ;
        RECT 48.730 30.555 49.100 30.925 ;
        RECT 49.690 30.555 50.060 30.925 ;
        RECT 50.650 30.555 51.020 30.925 ;
        RECT 51.610 30.555 51.980 30.925 ;
        RECT 52.570 30.555 52.940 30.925 ;
        RECT 14.650 28.255 15.020 28.625 ;
        RECT 15.610 28.255 15.980 28.625 ;
        RECT 16.570 28.255 16.940 28.625 ;
        RECT 17.530 28.255 17.900 28.625 ;
        RECT 18.490 28.255 18.860 28.625 ;
        RECT 19.450 28.255 19.820 28.625 ;
        RECT 20.410 28.255 20.780 28.625 ;
        RECT 21.370 28.255 21.740 28.625 ;
        RECT 22.330 28.255 22.700 28.625 ;
        RECT 23.290 28.255 23.660 28.625 ;
        RECT 24.250 28.255 24.620 28.625 ;
        RECT 25.210 28.255 25.580 28.625 ;
        RECT 26.170 28.255 26.540 28.625 ;
        RECT 27.130 28.255 27.500 28.625 ;
        RECT 28.090 28.255 28.460 28.625 ;
        RECT 29.050 28.255 29.420 28.625 ;
        RECT 30.010 28.255 30.380 28.625 ;
        RECT 30.970 28.255 31.340 28.625 ;
        RECT 31.930 28.255 32.300 28.625 ;
        RECT 32.890 28.255 33.260 28.625 ;
        RECT 33.850 28.255 34.220 28.625 ;
        RECT 34.810 28.255 35.180 28.625 ;
        RECT 35.770 28.255 36.140 28.625 ;
        RECT 36.730 28.255 37.100 28.625 ;
        RECT 37.690 28.255 38.060 28.625 ;
        RECT 38.650 28.255 39.020 28.625 ;
        RECT 39.610 28.255 39.980 28.625 ;
        RECT 40.570 28.255 40.940 28.625 ;
        RECT 41.530 28.255 41.900 28.625 ;
        RECT 42.490 28.255 42.860 28.625 ;
        RECT 43.450 28.255 43.820 28.625 ;
        RECT 44.410 28.255 44.780 28.625 ;
        RECT 45.370 28.255 45.740 28.625 ;
        RECT 46.330 28.255 46.700 28.625 ;
        RECT 47.290 28.255 47.660 28.625 ;
        RECT 48.250 28.255 48.620 28.625 ;
        RECT 49.210 28.255 49.580 28.625 ;
        RECT 50.170 28.255 50.540 28.625 ;
        RECT 51.130 28.255 51.500 28.625 ;
        RECT 52.090 28.255 52.460 28.625 ;
        RECT 53.050 28.255 53.420 28.625 ;
        RECT 53.015 26.080 53.385 26.450 ;
        RECT 7.850 24.160 19.640 24.520 ;
        RECT 17.325 23.200 26.020 23.550 ;
        RECT 18.115 19.100 21.595 19.450 ;
        RECT 19.705 16.050 20.005 19.100 ;
        RECT 25.130 19.055 25.500 19.445 ;
        RECT 58.240 19.200 58.610 30.450 ;
        RECT 21.315 16.050 21.685 18.375 ;
        RECT 59.460 16.050 59.760 44.290 ;
        RECT 132.790 0.250 133.090 70.000 ;
        RECT 152.070 0.300 152.370 70.540 ;
        RECT 152.550 19.480 152.850 105.805 ;
        RECT 152.515 19.050 152.885 19.480 ;
      LAYER met3 ;
        RECT 138.200 223.640 138.720 224.160 ;
        RECT 12.000 187.800 34.160 213.200 ;
        RECT 37.490 187.800 59.650 213.200 ;
        RECT 62.980 187.800 85.140 213.200 ;
        RECT 88.470 187.800 110.630 213.200 ;
        RECT 113.960 187.800 136.120 213.200 ;
        RECT 12.000 160.800 34.160 186.200 ;
        RECT 37.490 160.800 59.650 186.200 ;
        RECT 62.980 160.800 85.140 186.200 ;
        RECT 88.470 160.800 110.630 186.200 ;
        RECT 113.960 160.800 136.120 186.200 ;
        RECT 137.525 160.900 159.685 186.300 ;
        RECT 12.000 146.420 34.160 159.200 ;
        RECT 37.490 146.420 59.650 159.200 ;
        RECT 62.980 146.420 85.140 159.200 ;
        RECT 88.470 146.420 110.630 159.200 ;
        RECT 113.960 146.420 136.120 159.200 ;
        RECT 137.525 146.420 159.685 159.300 ;
        RECT 12.000 145.190 159.685 146.420 ;
        RECT 12.000 133.800 34.160 145.190 ;
        RECT 37.490 133.800 59.650 145.190 ;
        RECT 62.980 133.800 85.140 145.190 ;
        RECT 88.470 133.800 110.630 145.190 ;
        RECT 113.960 133.800 136.120 145.190 ;
        RECT 137.525 133.900 159.685 145.190 ;
        RECT 12.000 106.800 34.160 132.200 ;
        RECT 37.490 106.800 59.650 132.200 ;
        RECT 62.980 106.800 85.140 132.200 ;
        RECT 88.470 106.800 110.630 132.200 ;
        RECT 113.960 106.800 136.120 132.200 ;
        RECT 156.100 123.900 156.600 124.700 ;
        RECT 155.950 123.300 156.600 123.900 ;
        RECT 80.130 105.800 80.550 106.800 ;
        RECT 1.600 105.000 150.000 105.500 ;
        RECT 150.360 104.720 150.860 105.450 ;
        RECT 156.100 104.400 156.600 123.300 ;
        RECT 1.600 103.600 156.600 104.400 ;
        RECT 14.050 87.170 14.550 88.740 ;
        RECT 19.875 71.270 20.375 103.600 ;
        RECT 78.585 99.950 80.650 100.450 ;
        RECT 61.600 87.170 62.100 88.740 ;
        RECT 22.585 75.400 23.085 85.350 ;
        RECT 27.100 70.600 27.600 72.720 ;
        RECT 78.585 71.220 79.085 99.950 ;
        RECT 81.350 77.500 81.750 103.600 ;
        RECT 79.900 77.000 81.750 77.500 ;
        RECT 79.900 75.390 80.350 77.000 ;
        RECT 130.875 75.390 131.375 103.600 ;
        RECT 136.585 86.980 137.085 87.600 ;
        RECT 136.585 86.570 137.650 86.980 ;
        RECT 136.585 75.415 137.085 86.570 ;
        RECT 140.050 76.630 141.900 77.040 ;
        RECT 1.600 55.210 53.735 55.710 ;
        RECT 14.335 52.910 55.000 53.410 ;
        RECT 1.600 49.030 53.735 49.530 ;
        RECT 54.500 47.230 55.000 52.910 ;
        RECT 14.335 46.730 55.000 47.230 ;
        RECT 1.600 42.850 53.735 43.350 ;
        RECT 54.500 41.050 55.000 46.730 ;
        RECT 14.335 40.550 55.000 41.050 ;
        RECT 1.600 36.670 53.735 37.170 ;
        RECT 54.500 34.870 55.000 40.550 ;
        RECT 14.335 34.370 55.000 34.870 ;
        RECT 1.600 30.490 53.735 30.990 ;
        RECT 13.500 26.550 14.000 30.490 ;
        RECT 54.500 28.690 55.000 34.370 ;
        RECT 14.335 28.190 55.000 28.690 ;
        RECT 13.500 26.050 53.500 26.550 ;
        RECT 54.500 19.600 55.000 28.190 ;
        RECT 24.900 17.100 152.950 19.600 ;
        RECT 4.000 15.900 60.000 16.600 ;
        RECT 113.320 0.300 113.920 17.100 ;
        RECT 132.680 0.190 133.200 0.710 ;
        RECT 151.960 0.240 152.460 0.760 ;
      LAYER met4 ;
        RECT 30.670 217.800 30.970 224.760 ;
        RECT 33.430 217.800 33.730 224.760 ;
        RECT 36.190 217.800 36.490 224.760 ;
        RECT 38.950 217.800 39.250 224.760 ;
        RECT 41.710 217.800 42.010 224.760 ;
        RECT 44.470 217.800 44.770 224.760 ;
        RECT 47.230 217.800 47.530 224.760 ;
        RECT 49.990 217.800 50.290 224.760 ;
        RECT 52.750 217.800 53.050 224.760 ;
        RECT 55.510 217.800 55.810 224.760 ;
        RECT 58.270 217.800 58.570 224.760 ;
        RECT 61.030 217.800 61.330 224.760 ;
        RECT 63.790 217.800 64.090 224.760 ;
        RECT 66.550 217.800 66.850 224.760 ;
        RECT 69.310 217.800 69.610 224.760 ;
        RECT 72.070 217.800 72.370 224.760 ;
        RECT 74.830 217.800 75.130 224.760 ;
        RECT 77.590 217.800 77.890 224.760 ;
        RECT 80.350 217.800 80.650 224.760 ;
        RECT 83.110 217.800 83.410 224.760 ;
        RECT 85.870 217.800 86.170 224.760 ;
        RECT 88.630 217.800 88.930 224.760 ;
        RECT 91.390 217.800 91.690 224.760 ;
        RECT 94.150 217.800 94.450 224.760 ;
        RECT 138.310 224.150 138.610 224.760 ;
        RECT 138.210 223.650 138.710 224.150 ;
        RECT 6.000 217.000 95.000 217.800 ;
        RECT 21.940 212.805 22.460 214.000 ;
        RECT 12.395 188.195 32.005 212.805 ;
        RECT 21.940 185.805 22.460 188.195 ;
        RECT 12.395 161.195 32.005 185.805 ;
        RECT 21.940 158.805 22.460 161.195 ;
        RECT 12.395 134.195 32.005 158.805 ;
        RECT 21.940 131.805 22.460 134.195 ;
        RECT 12.395 107.195 32.005 131.805 ;
        RECT 21.940 106.000 22.460 107.195 ;
        RECT 33.640 106.000 34.160 214.000 ;
        RECT 47.430 212.805 47.950 214.000 ;
        RECT 37.885 188.195 57.495 212.805 ;
        RECT 47.430 185.805 47.950 188.195 ;
        RECT 37.885 161.195 57.495 185.805 ;
        RECT 47.430 158.805 47.950 161.195 ;
        RECT 37.885 134.195 57.495 158.805 ;
        RECT 47.430 131.805 47.950 134.195 ;
        RECT 37.885 107.195 57.495 131.805 ;
        RECT 47.430 106.000 47.950 107.195 ;
        RECT 59.130 106.000 59.650 214.000 ;
        RECT 72.920 212.805 73.440 214.000 ;
        RECT 63.375 188.195 82.985 212.805 ;
        RECT 72.920 185.805 73.440 188.195 ;
        RECT 63.375 161.195 82.985 185.805 ;
        RECT 72.920 158.805 73.440 161.195 ;
        RECT 63.375 134.195 82.985 158.805 ;
        RECT 72.920 131.805 73.440 134.195 ;
        RECT 63.375 107.195 82.985 131.805 ;
        RECT 72.920 106.000 73.440 107.195 ;
        RECT 84.620 106.000 85.140 214.000 ;
        RECT 98.410 212.805 98.930 214.000 ;
        RECT 88.865 188.195 108.475 212.805 ;
        RECT 98.410 185.805 98.930 188.195 ;
        RECT 88.865 161.195 108.475 185.805 ;
        RECT 98.410 158.805 98.930 161.195 ;
        RECT 88.865 134.195 108.475 158.805 ;
        RECT 98.410 131.805 98.930 134.195 ;
        RECT 88.865 107.195 108.475 131.805 ;
        RECT 98.410 106.000 98.930 107.195 ;
        RECT 110.110 106.000 110.630 214.000 ;
        RECT 123.900 212.805 124.420 214.000 ;
        RECT 114.355 188.195 133.965 212.805 ;
        RECT 123.900 185.805 124.420 188.195 ;
        RECT 114.355 161.195 133.965 185.805 ;
        RECT 123.900 158.805 124.420 161.195 ;
        RECT 114.355 134.195 133.965 158.805 ;
        RECT 123.900 131.805 124.420 134.195 ;
        RECT 114.355 107.195 133.965 131.805 ;
        RECT 123.900 106.000 124.420 107.195 ;
        RECT 135.600 106.000 136.120 214.000 ;
        RECT 147.465 185.905 147.985 187.100 ;
        RECT 137.920 161.295 157.530 185.905 ;
        RECT 147.465 158.905 147.985 161.295 ;
        RECT 137.920 134.295 157.530 158.905 ;
        RECT 147.465 133.100 147.985 134.295 ;
        RECT 159.165 133.100 159.685 187.100 ;
        RECT 21.990 105.410 22.430 106.000 ;
        RECT 47.460 105.410 47.900 106.000 ;
        RECT 72.960 105.410 73.400 106.000 ;
        RECT 98.440 105.410 98.880 106.000 ;
        RECT 123.950 105.410 124.390 106.000 ;
        RECT 147.520 105.410 147.930 133.100 ;
        RECT 21.910 104.920 151.000 105.410 ;
  END
END tt_um_ogggggish_ota_ldo
END LIBRARY

